VERSION 5.7 ;
  NOWIREEXTENSIONATPIN ON ;
  DIVIDERCHAR "/" ;
  BUSBITCHARS "[]" ;
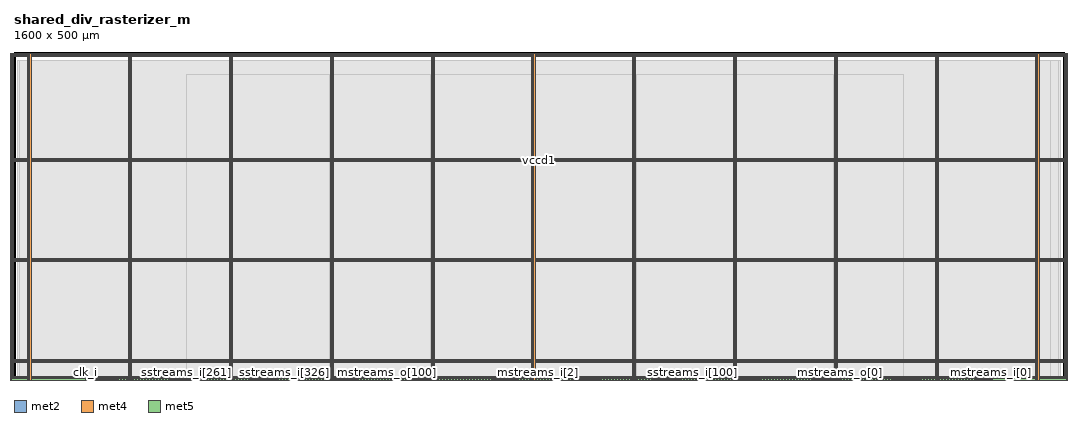
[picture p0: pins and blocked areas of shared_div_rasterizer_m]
MACRO shared_div_rasterizer_m
  CLASS BLOCK ;
  FOREIGN shared_div_rasterizer_m ;
  ORIGIN 0.000 0.000 ;
  SIZE 1600.000 BY 500.000 ;
  PIN clk_i
    DIRECTION INPUT ;
    USE SIGNAL ;
    ANTENNAGATEAREA 0.852000 ;
    PORT
      LAYER met2 ;
        RECT 108.650 0.000 108.930 4.000 ;
    END
  END clk_i
  PIN mstreams_i[0]
    DIRECTION INPUT ;
    USE SIGNAL ;
    ANTENNAGATEAREA 0.196500 ;
    PORT
      LAYER met2 ;
        RECT 1488.650 0.000 1488.930 4.000 ;
    END
  END mstreams_i[0]
  PIN mstreams_i[1]
    DIRECTION INPUT ;
    USE SIGNAL ;
    ANTENNAGATEAREA 0.196500 ;
    PORT
      LAYER met2 ;
        RECT 1490.950 0.000 1491.230 4.000 ;
    END
  END mstreams_i[1]
  PIN mstreams_i[2]
    DIRECTION INPUT ;
    USE SIGNAL ;
    ANTENNAGATEAREA 0.196500 ;
    PORT
      LAYER met2 ;
        RECT 798.650 0.000 798.930 4.000 ;
    END
  END mstreams_i[2]
  PIN mstreams_i[3]
    DIRECTION INPUT ;
    USE SIGNAL ;
    ANTENNAGATEAREA 0.196500 ;
    PORT
      LAYER met2 ;
        RECT 800.950 0.000 801.230 4.000 ;
    END
  END mstreams_i[3]
  PIN mstreams_o[0]
    DIRECTION OUTPUT TRISTATE ;
    USE SIGNAL ;
    ANTENNADIFFAREA 0.795200 ;
    PORT
      LAYER met2 ;
        RECT 1258.650 0.000 1258.930 4.000 ;
    END
  END mstreams_o[0]
  PIN mstreams_o[100]
    DIRECTION OUTPUT TRISTATE ;
    USE SIGNAL ;
    ANTENNADIFFAREA 0.795200 ;
    PORT
      LAYER met2 ;
        RECT 568.650 0.000 568.930 4.000 ;
    END
  END mstreams_o[100]
  PIN mstreams_o[101]
    DIRECTION OUTPUT TRISTATE ;
    USE SIGNAL ;
    ANTENNADIFFAREA 0.795200 ;
    PORT
      LAYER met2 ;
        RECT 570.950 0.000 571.230 4.000 ;
    END
  END mstreams_o[101]
  PIN mstreams_o[102]
    DIRECTION OUTPUT TRISTATE ;
    USE SIGNAL ;
    ANTENNADIFFAREA 0.795200 ;
    PORT
      LAYER met2 ;
        RECT 573.250 0.000 573.530 4.000 ;
    END
  END mstreams_o[102]
  PIN mstreams_o[103]
    DIRECTION OUTPUT TRISTATE ;
    USE SIGNAL ;
    ANTENNADIFFAREA 0.795200 ;
    PORT
      LAYER met2 ;
        RECT 575.550 0.000 575.830 4.000 ;
    END
  END mstreams_o[103]
  PIN mstreams_o[104]
    DIRECTION OUTPUT TRISTATE ;
    USE SIGNAL ;
    ANTENNADIFFAREA 0.795200 ;
    PORT
      LAYER met2 ;
        RECT 577.850 0.000 578.130 4.000 ;
    END
  END mstreams_o[104]
  PIN mstreams_o[105]
    DIRECTION OUTPUT TRISTATE ;
    USE SIGNAL ;
    ANTENNADIFFAREA 0.795200 ;
    PORT
      LAYER met2 ;
        RECT 580.150 0.000 580.430 4.000 ;
    END
  END mstreams_o[105]
  PIN mstreams_o[106]
    DIRECTION OUTPUT TRISTATE ;
    USE SIGNAL ;
    ANTENNADIFFAREA 0.795200 ;
    PORT
      LAYER met2 ;
        RECT 582.450 0.000 582.730 4.000 ;
    END
  END mstreams_o[106]
  PIN mstreams_o[107]
    DIRECTION OUTPUT TRISTATE ;
    USE SIGNAL ;
    ANTENNADIFFAREA 0.795200 ;
    PORT
      LAYER met2 ;
        RECT 584.750 0.000 585.030 4.000 ;
    END
  END mstreams_o[107]
  PIN mstreams_o[108]
    DIRECTION OUTPUT TRISTATE ;
    USE SIGNAL ;
    ANTENNADIFFAREA 0.795200 ;
    PORT
      LAYER met2 ;
        RECT 587.050 0.000 587.330 4.000 ;
    END
  END mstreams_o[108]
  PIN mstreams_o[109]
    DIRECTION OUTPUT TRISTATE ;
    USE SIGNAL ;
    ANTENNADIFFAREA 0.795200 ;
    PORT
      LAYER met2 ;
        RECT 589.350 0.000 589.630 4.000 ;
    END
  END mstreams_o[109]
  PIN mstreams_o[10]
    DIRECTION OUTPUT TRISTATE ;
    USE SIGNAL ;
    ANTENNADIFFAREA 0.795200 ;
    PORT
      LAYER met2 ;
        RECT 1281.650 0.000 1281.930 4.000 ;
    END
  END mstreams_o[10]
  PIN mstreams_o[110]
    DIRECTION OUTPUT TRISTATE ;
    USE SIGNAL ;
    ANTENNADIFFAREA 0.795200 ;
    PORT
      LAYER met2 ;
        RECT 591.650 0.000 591.930 4.000 ;
    END
  END mstreams_o[110]
  PIN mstreams_o[111]
    DIRECTION OUTPUT TRISTATE ;
    USE SIGNAL ;
    ANTENNADIFFAREA 0.795200 ;
    PORT
      LAYER met2 ;
        RECT 593.950 0.000 594.230 4.000 ;
    END
  END mstreams_o[111]
  PIN mstreams_o[112]
    DIRECTION OUTPUT TRISTATE ;
    USE SIGNAL ;
    ANTENNADIFFAREA 0.795200 ;
    PORT
      LAYER met2 ;
        RECT 596.250 0.000 596.530 4.000 ;
    END
  END mstreams_o[112]
  PIN mstreams_o[113]
    DIRECTION OUTPUT TRISTATE ;
    USE SIGNAL ;
    ANTENNADIFFAREA 0.795200 ;
    PORT
      LAYER met2 ;
        RECT 598.550 0.000 598.830 4.000 ;
    END
  END mstreams_o[113]
  PIN mstreams_o[114]
    DIRECTION OUTPUT TRISTATE ;
    USE SIGNAL ;
    ANTENNADIFFAREA 0.795200 ;
    PORT
      LAYER met2 ;
        RECT 600.850 0.000 601.130 4.000 ;
    END
  END mstreams_o[114]
  PIN mstreams_o[115]
    DIRECTION OUTPUT TRISTATE ;
    USE SIGNAL ;
    ANTENNADIFFAREA 0.795200 ;
    PORT
      LAYER met2 ;
        RECT 603.150 0.000 603.430 4.000 ;
    END
  END mstreams_o[115]
  PIN mstreams_o[116]
    DIRECTION OUTPUT TRISTATE ;
    USE SIGNAL ;
    ANTENNADIFFAREA 0.795200 ;
    PORT
      LAYER met2 ;
        RECT 605.450 0.000 605.730 4.000 ;
    END
  END mstreams_o[116]
  PIN mstreams_o[117]
    DIRECTION OUTPUT TRISTATE ;
    USE SIGNAL ;
    ANTENNADIFFAREA 0.795200 ;
    PORT
      LAYER met2 ;
        RECT 607.750 0.000 608.030 4.000 ;
    END
  END mstreams_o[117]
  PIN mstreams_o[118]
    DIRECTION OUTPUT TRISTATE ;
    USE SIGNAL ;
    ANTENNADIFFAREA 0.795200 ;
    PORT
      LAYER met2 ;
        RECT 610.050 0.000 610.330 4.000 ;
    END
  END mstreams_o[118]
  PIN mstreams_o[119]
    DIRECTION OUTPUT TRISTATE ;
    USE SIGNAL ;
    ANTENNADIFFAREA 0.795200 ;
    PORT
      LAYER met2 ;
        RECT 612.350 0.000 612.630 4.000 ;
    END
  END mstreams_o[119]
  PIN mstreams_o[11]
    DIRECTION OUTPUT TRISTATE ;
    USE SIGNAL ;
    ANTENNADIFFAREA 0.795200 ;
    PORT
      LAYER met2 ;
        RECT 1283.950 0.000 1284.230 4.000 ;
    END
  END mstreams_o[11]
  PIN mstreams_o[120]
    DIRECTION OUTPUT TRISTATE ;
    USE SIGNAL ;
    ANTENNADIFFAREA 0.795200 ;
    PORT
      LAYER met2 ;
        RECT 614.650 0.000 614.930 4.000 ;
    END
  END mstreams_o[120]
  PIN mstreams_o[121]
    DIRECTION OUTPUT TRISTATE ;
    USE SIGNAL ;
    ANTENNADIFFAREA 0.795200 ;
    PORT
      LAYER met2 ;
        RECT 616.950 0.000 617.230 4.000 ;
    END
  END mstreams_o[121]
  PIN mstreams_o[122]
    DIRECTION OUTPUT TRISTATE ;
    USE SIGNAL ;
    ANTENNADIFFAREA 0.795200 ;
    PORT
      LAYER met2 ;
        RECT 619.250 0.000 619.530 4.000 ;
    END
  END mstreams_o[122]
  PIN mstreams_o[123]
    DIRECTION OUTPUT TRISTATE ;
    USE SIGNAL ;
    ANTENNADIFFAREA 0.795200 ;
    PORT
      LAYER met2 ;
        RECT 621.550 0.000 621.830 4.000 ;
    END
  END mstreams_o[123]
  PIN mstreams_o[124]
    DIRECTION OUTPUT TRISTATE ;
    USE SIGNAL ;
    ANTENNADIFFAREA 0.795200 ;
    PORT
      LAYER met2 ;
        RECT 623.850 0.000 624.130 4.000 ;
    END
  END mstreams_o[124]
  PIN mstreams_o[125]
    DIRECTION OUTPUT TRISTATE ;
    USE SIGNAL ;
    ANTENNADIFFAREA 0.795200 ;
    PORT
      LAYER met2 ;
        RECT 626.150 0.000 626.430 4.000 ;
    END
  END mstreams_o[125]
  PIN mstreams_o[126]
    DIRECTION OUTPUT TRISTATE ;
    USE SIGNAL ;
    ANTENNADIFFAREA 0.795200 ;
    PORT
      LAYER met2 ;
        RECT 628.450 0.000 628.730 4.000 ;
    END
  END mstreams_o[126]
  PIN mstreams_o[127]
    DIRECTION OUTPUT TRISTATE ;
    USE SIGNAL ;
    ANTENNADIFFAREA 0.795200 ;
    PORT
      LAYER met2 ;
        RECT 630.750 0.000 631.030 4.000 ;
    END
  END mstreams_o[127]
  PIN mstreams_o[128]
    DIRECTION OUTPUT TRISTATE ;
    USE SIGNAL ;
    ANTENNADIFFAREA 0.795200 ;
    PORT
      LAYER met2 ;
        RECT 633.050 0.000 633.330 4.000 ;
    END
  END mstreams_o[128]
  PIN mstreams_o[129]
    DIRECTION OUTPUT TRISTATE ;
    USE SIGNAL ;
    ANTENNADIFFAREA 0.795200 ;
    PORT
      LAYER met2 ;
        RECT 635.350 0.000 635.630 4.000 ;
    END
  END mstreams_o[129]
  PIN mstreams_o[12]
    DIRECTION OUTPUT TRISTATE ;
    USE SIGNAL ;
    ANTENNADIFFAREA 0.795200 ;
    PORT
      LAYER met2 ;
        RECT 1286.250 0.000 1286.530 4.000 ;
    END
  END mstreams_o[12]
  PIN mstreams_o[130]
    DIRECTION OUTPUT TRISTATE ;
    USE SIGNAL ;
    ANTENNADIFFAREA 0.795200 ;
    PORT
      LAYER met2 ;
        RECT 637.650 0.000 637.930 4.000 ;
    END
  END mstreams_o[130]
  PIN mstreams_o[131]
    DIRECTION OUTPUT TRISTATE ;
    USE SIGNAL ;
    ANTENNADIFFAREA 0.795200 ;
    PORT
      LAYER met2 ;
        RECT 639.950 0.000 640.230 4.000 ;
    END
  END mstreams_o[131]
  PIN mstreams_o[132]
    DIRECTION OUTPUT TRISTATE ;
    USE SIGNAL ;
    ANTENNADIFFAREA 0.795200 ;
    PORT
      LAYER met2 ;
        RECT 642.250 0.000 642.530 4.000 ;
    END
  END mstreams_o[132]
  PIN mstreams_o[133]
    DIRECTION OUTPUT TRISTATE ;
    USE SIGNAL ;
    ANTENNADIFFAREA 0.795200 ;
    PORT
      LAYER met2 ;
        RECT 644.550 0.000 644.830 4.000 ;
    END
  END mstreams_o[133]
  PIN mstreams_o[134]
    DIRECTION OUTPUT TRISTATE ;
    USE SIGNAL ;
    ANTENNADIFFAREA 0.795200 ;
    PORT
      LAYER met2 ;
        RECT 646.850 0.000 647.130 4.000 ;
    END
  END mstreams_o[134]
  PIN mstreams_o[135]
    DIRECTION OUTPUT TRISTATE ;
    USE SIGNAL ;
    ANTENNADIFFAREA 0.795200 ;
    PORT
      LAYER met2 ;
        RECT 649.150 0.000 649.430 4.000 ;
    END
  END mstreams_o[135]
  PIN mstreams_o[136]
    DIRECTION OUTPUT TRISTATE ;
    USE SIGNAL ;
    ANTENNADIFFAREA 0.795200 ;
    PORT
      LAYER met2 ;
        RECT 651.450 0.000 651.730 4.000 ;
    END
  END mstreams_o[136]
  PIN mstreams_o[137]
    DIRECTION OUTPUT TRISTATE ;
    USE SIGNAL ;
    ANTENNADIFFAREA 0.795200 ;
    PORT
      LAYER met2 ;
        RECT 653.750 0.000 654.030 4.000 ;
    END
  END mstreams_o[137]
  PIN mstreams_o[138]
    DIRECTION OUTPUT TRISTATE ;
    USE SIGNAL ;
    ANTENNADIFFAREA 0.795200 ;
    PORT
      LAYER met2 ;
        RECT 656.050 0.000 656.330 4.000 ;
    END
  END mstreams_o[138]
  PIN mstreams_o[139]
    DIRECTION OUTPUT TRISTATE ;
    USE SIGNAL ;
    ANTENNADIFFAREA 0.795200 ;
    PORT
      LAYER met2 ;
        RECT 658.350 0.000 658.630 4.000 ;
    END
  END mstreams_o[139]
  PIN mstreams_o[13]
    DIRECTION OUTPUT TRISTATE ;
    USE SIGNAL ;
    ANTENNADIFFAREA 0.795200 ;
    PORT
      LAYER met2 ;
        RECT 1288.550 0.000 1288.830 4.000 ;
    END
  END mstreams_o[13]
  PIN mstreams_o[140]
    DIRECTION OUTPUT TRISTATE ;
    USE SIGNAL ;
    ANTENNADIFFAREA 0.795200 ;
    PORT
      LAYER met2 ;
        RECT 660.650 0.000 660.930 4.000 ;
    END
  END mstreams_o[140]
  PIN mstreams_o[141]
    DIRECTION OUTPUT TRISTATE ;
    USE SIGNAL ;
    ANTENNADIFFAREA 0.795200 ;
    PORT
      LAYER met2 ;
        RECT 662.950 0.000 663.230 4.000 ;
    END
  END mstreams_o[141]
  PIN mstreams_o[142]
    DIRECTION OUTPUT TRISTATE ;
    USE SIGNAL ;
    ANTENNADIFFAREA 0.795200 ;
    PORT
      LAYER met2 ;
        RECT 665.250 0.000 665.530 4.000 ;
    END
  END mstreams_o[142]
  PIN mstreams_o[143]
    DIRECTION OUTPUT TRISTATE ;
    USE SIGNAL ;
    ANTENNADIFFAREA 0.795200 ;
    PORT
      LAYER met2 ;
        RECT 667.550 0.000 667.830 4.000 ;
    END
  END mstreams_o[143]
  PIN mstreams_o[144]
    DIRECTION OUTPUT TRISTATE ;
    USE SIGNAL ;
    ANTENNADIFFAREA 0.795200 ;
    PORT
      LAYER met2 ;
        RECT 669.850 0.000 670.130 4.000 ;
    END
  END mstreams_o[144]
  PIN mstreams_o[145]
    DIRECTION OUTPUT TRISTATE ;
    USE SIGNAL ;
    ANTENNADIFFAREA 0.795200 ;
    PORT
      LAYER met2 ;
        RECT 672.150 0.000 672.430 4.000 ;
    END
  END mstreams_o[145]
  PIN mstreams_o[146]
    DIRECTION OUTPUT TRISTATE ;
    USE SIGNAL ;
    ANTENNADIFFAREA 0.795200 ;
    PORT
      LAYER met2 ;
        RECT 674.450 0.000 674.730 4.000 ;
    END
  END mstreams_o[146]
  PIN mstreams_o[147]
    DIRECTION OUTPUT TRISTATE ;
    USE SIGNAL ;
    ANTENNADIFFAREA 0.795200 ;
    PORT
      LAYER met2 ;
        RECT 676.750 0.000 677.030 4.000 ;
    END
  END mstreams_o[147]
  PIN mstreams_o[148]
    DIRECTION OUTPUT TRISTATE ;
    USE SIGNAL ;
    ANTENNADIFFAREA 0.795200 ;
    PORT
      LAYER met2 ;
        RECT 679.050 0.000 679.330 4.000 ;
    END
  END mstreams_o[148]
  PIN mstreams_o[149]
    DIRECTION OUTPUT TRISTATE ;
    USE SIGNAL ;
    PORT
      LAYER met2 ;
        RECT 681.350 0.000 681.630 4.000 ;
    END
  END mstreams_o[149]
  PIN mstreams_o[14]
    DIRECTION OUTPUT TRISTATE ;
    USE SIGNAL ;
    ANTENNADIFFAREA 0.795200 ;
    PORT
      LAYER met2 ;
        RECT 1290.850 0.000 1291.130 4.000 ;
    END
  END mstreams_o[14]
  PIN mstreams_o[150]
    DIRECTION OUTPUT TRISTATE ;
    USE SIGNAL ;
    ANTENNADIFFAREA 0.795200 ;
    PORT
      LAYER met2 ;
        RECT 683.650 0.000 683.930 4.000 ;
    END
  END mstreams_o[150]
  PIN mstreams_o[151]
    DIRECTION OUTPUT TRISTATE ;
    USE SIGNAL ;
    ANTENNADIFFAREA 0.795200 ;
    PORT
      LAYER met2 ;
        RECT 685.950 0.000 686.230 4.000 ;
    END
  END mstreams_o[151]
  PIN mstreams_o[152]
    DIRECTION OUTPUT TRISTATE ;
    USE SIGNAL ;
    ANTENNADIFFAREA 0.795200 ;
    PORT
      LAYER met2 ;
        RECT 688.250 0.000 688.530 4.000 ;
    END
  END mstreams_o[152]
  PIN mstreams_o[153]
    DIRECTION OUTPUT TRISTATE ;
    USE SIGNAL ;
    ANTENNADIFFAREA 0.795200 ;
    PORT
      LAYER met2 ;
        RECT 690.550 0.000 690.830 4.000 ;
    END
  END mstreams_o[153]
  PIN mstreams_o[154]
    DIRECTION OUTPUT TRISTATE ;
    USE SIGNAL ;
    ANTENNADIFFAREA 0.795200 ;
    PORT
      LAYER met2 ;
        RECT 692.850 0.000 693.130 4.000 ;
    END
  END mstreams_o[154]
  PIN mstreams_o[155]
    DIRECTION OUTPUT TRISTATE ;
    USE SIGNAL ;
    ANTENNADIFFAREA 0.795200 ;
    PORT
      LAYER met2 ;
        RECT 695.150 0.000 695.430 4.000 ;
    END
  END mstreams_o[155]
  PIN mstreams_o[156]
    DIRECTION OUTPUT TRISTATE ;
    USE SIGNAL ;
    ANTENNADIFFAREA 0.795200 ;
    PORT
      LAYER met2 ;
        RECT 697.450 0.000 697.730 4.000 ;
    END
  END mstreams_o[156]
  PIN mstreams_o[157]
    DIRECTION OUTPUT TRISTATE ;
    USE SIGNAL ;
    ANTENNADIFFAREA 0.795200 ;
    PORT
      LAYER met2 ;
        RECT 699.750 0.000 700.030 4.000 ;
    END
  END mstreams_o[157]
  PIN mstreams_o[158]
    DIRECTION OUTPUT TRISTATE ;
    USE SIGNAL ;
    ANTENNADIFFAREA 0.795200 ;
    PORT
      LAYER met2 ;
        RECT 702.050 0.000 702.330 4.000 ;
    END
  END mstreams_o[158]
  PIN mstreams_o[159]
    DIRECTION OUTPUT TRISTATE ;
    USE SIGNAL ;
    ANTENNADIFFAREA 0.795200 ;
    PORT
      LAYER met2 ;
        RECT 704.350 0.000 704.630 4.000 ;
    END
  END mstreams_o[159]
  PIN mstreams_o[15]
    DIRECTION OUTPUT TRISTATE ;
    USE SIGNAL ;
    ANTENNADIFFAREA 0.795200 ;
    PORT
      LAYER met2 ;
        RECT 1293.150 0.000 1293.430 4.000 ;
    END
  END mstreams_o[15]
  PIN mstreams_o[160]
    DIRECTION OUTPUT TRISTATE ;
    USE SIGNAL ;
    ANTENNADIFFAREA 0.795200 ;
    PORT
      LAYER met2 ;
        RECT 706.650 0.000 706.930 4.000 ;
    END
  END mstreams_o[160]
  PIN mstreams_o[161]
    DIRECTION OUTPUT TRISTATE ;
    USE SIGNAL ;
    ANTENNADIFFAREA 0.795200 ;
    PORT
      LAYER met2 ;
        RECT 708.950 0.000 709.230 4.000 ;
    END
  END mstreams_o[161]
  PIN mstreams_o[162]
    DIRECTION OUTPUT TRISTATE ;
    USE SIGNAL ;
    ANTENNADIFFAREA 0.795200 ;
    PORT
      LAYER met2 ;
        RECT 711.250 0.000 711.530 4.000 ;
    END
  END mstreams_o[162]
  PIN mstreams_o[163]
    DIRECTION OUTPUT TRISTATE ;
    USE SIGNAL ;
    ANTENNADIFFAREA 0.795200 ;
    PORT
      LAYER met2 ;
        RECT 713.550 0.000 713.830 4.000 ;
    END
  END mstreams_o[163]
  PIN mstreams_o[164]
    DIRECTION OUTPUT TRISTATE ;
    USE SIGNAL ;
    ANTENNADIFFAREA 0.795200 ;
    PORT
      LAYER met2 ;
        RECT 715.850 0.000 716.130 4.000 ;
    END
  END mstreams_o[164]
  PIN mstreams_o[165]
    DIRECTION OUTPUT TRISTATE ;
    USE SIGNAL ;
    ANTENNADIFFAREA 0.795200 ;
    PORT
      LAYER met2 ;
        RECT 718.150 0.000 718.430 4.000 ;
    END
  END mstreams_o[165]
  PIN mstreams_o[166]
    DIRECTION OUTPUT TRISTATE ;
    USE SIGNAL ;
    ANTENNADIFFAREA 0.795200 ;
    PORT
      LAYER met2 ;
        RECT 720.450 0.000 720.730 4.000 ;
    END
  END mstreams_o[166]
  PIN mstreams_o[167]
    DIRECTION OUTPUT TRISTATE ;
    USE SIGNAL ;
    ANTENNADIFFAREA 0.795200 ;
    PORT
      LAYER met2 ;
        RECT 722.750 0.000 723.030 4.000 ;
    END
  END mstreams_o[167]
  PIN mstreams_o[168]
    DIRECTION OUTPUT TRISTATE ;
    USE SIGNAL ;
    ANTENNADIFFAREA 0.795200 ;
    PORT
      LAYER met2 ;
        RECT 725.050 0.000 725.330 4.000 ;
    END
  END mstreams_o[168]
  PIN mstreams_o[169]
    DIRECTION OUTPUT TRISTATE ;
    USE SIGNAL ;
    ANTENNADIFFAREA 0.795200 ;
    PORT
      LAYER met2 ;
        RECT 727.350 0.000 727.630 4.000 ;
    END
  END mstreams_o[169]
  PIN mstreams_o[16]
    DIRECTION OUTPUT TRISTATE ;
    USE SIGNAL ;
    ANTENNADIFFAREA 0.795200 ;
    PORT
      LAYER met2 ;
        RECT 1295.450 0.000 1295.730 4.000 ;
    END
  END mstreams_o[16]
  PIN mstreams_o[170]
    DIRECTION OUTPUT TRISTATE ;
    USE SIGNAL ;
    ANTENNADIFFAREA 0.795200 ;
    PORT
      LAYER met2 ;
        RECT 729.650 0.000 729.930 4.000 ;
    END
  END mstreams_o[170]
  PIN mstreams_o[171]
    DIRECTION OUTPUT TRISTATE ;
    USE SIGNAL ;
    ANTENNADIFFAREA 0.795200 ;
    PORT
      LAYER met2 ;
        RECT 731.950 0.000 732.230 4.000 ;
    END
  END mstreams_o[171]
  PIN mstreams_o[172]
    DIRECTION OUTPUT TRISTATE ;
    USE SIGNAL ;
    ANTENNADIFFAREA 0.795200 ;
    PORT
      LAYER met2 ;
        RECT 734.250 0.000 734.530 4.000 ;
    END
  END mstreams_o[172]
  PIN mstreams_o[173]
    DIRECTION OUTPUT TRISTATE ;
    USE SIGNAL ;
    ANTENNADIFFAREA 0.795200 ;
    PORT
      LAYER met2 ;
        RECT 736.550 0.000 736.830 4.000 ;
    END
  END mstreams_o[173]
  PIN mstreams_o[174]
    DIRECTION OUTPUT TRISTATE ;
    USE SIGNAL ;
    ANTENNADIFFAREA 0.795200 ;
    PORT
      LAYER met2 ;
        RECT 738.850 0.000 739.130 4.000 ;
    END
  END mstreams_o[174]
  PIN mstreams_o[175]
    DIRECTION OUTPUT TRISTATE ;
    USE SIGNAL ;
    ANTENNADIFFAREA 0.795200 ;
    PORT
      LAYER met2 ;
        RECT 741.150 0.000 741.430 4.000 ;
    END
  END mstreams_o[175]
  PIN mstreams_o[176]
    DIRECTION OUTPUT TRISTATE ;
    USE SIGNAL ;
    ANTENNADIFFAREA 0.795200 ;
    PORT
      LAYER met2 ;
        RECT 743.450 0.000 743.730 4.000 ;
    END
  END mstreams_o[176]
  PIN mstreams_o[177]
    DIRECTION OUTPUT TRISTATE ;
    USE SIGNAL ;
    ANTENNADIFFAREA 0.795200 ;
    PORT
      LAYER met2 ;
        RECT 745.750 0.000 746.030 4.000 ;
    END
  END mstreams_o[177]
  PIN mstreams_o[178]
    DIRECTION OUTPUT TRISTATE ;
    USE SIGNAL ;
    ANTENNADIFFAREA 0.795200 ;
    PORT
      LAYER met2 ;
        RECT 748.050 0.000 748.330 4.000 ;
    END
  END mstreams_o[178]
  PIN mstreams_o[179]
    DIRECTION OUTPUT TRISTATE ;
    USE SIGNAL ;
    ANTENNADIFFAREA 0.795200 ;
    PORT
      LAYER met2 ;
        RECT 750.350 0.000 750.630 4.000 ;
    END
  END mstreams_o[179]
  PIN mstreams_o[17]
    DIRECTION OUTPUT TRISTATE ;
    USE SIGNAL ;
    ANTENNADIFFAREA 0.795200 ;
    PORT
      LAYER met2 ;
        RECT 1297.750 0.000 1298.030 4.000 ;
    END
  END mstreams_o[17]
  PIN mstreams_o[180]
    DIRECTION OUTPUT TRISTATE ;
    USE SIGNAL ;
    ANTENNADIFFAREA 0.795200 ;
    PORT
      LAYER met2 ;
        RECT 752.650 0.000 752.930 4.000 ;
    END
  END mstreams_o[180]
  PIN mstreams_o[181]
    DIRECTION OUTPUT TRISTATE ;
    USE SIGNAL ;
    ANTENNADIFFAREA 0.795200 ;
    PORT
      LAYER met2 ;
        RECT 754.950 0.000 755.230 4.000 ;
    END
  END mstreams_o[181]
  PIN mstreams_o[182]
    DIRECTION OUTPUT TRISTATE ;
    USE SIGNAL ;
    ANTENNADIFFAREA 0.795200 ;
    PORT
      LAYER met2 ;
        RECT 757.250 0.000 757.530 4.000 ;
    END
  END mstreams_o[182]
  PIN mstreams_o[183]
    DIRECTION OUTPUT TRISTATE ;
    USE SIGNAL ;
    ANTENNADIFFAREA 0.795200 ;
    PORT
      LAYER met2 ;
        RECT 759.550 0.000 759.830 4.000 ;
    END
  END mstreams_o[183]
  PIN mstreams_o[184]
    DIRECTION OUTPUT TRISTATE ;
    USE SIGNAL ;
    ANTENNADIFFAREA 0.795200 ;
    PORT
      LAYER met2 ;
        RECT 761.850 0.000 762.130 4.000 ;
    END
  END mstreams_o[184]
  PIN mstreams_o[185]
    DIRECTION OUTPUT TRISTATE ;
    USE SIGNAL ;
    ANTENNADIFFAREA 0.795200 ;
    PORT
      LAYER met2 ;
        RECT 764.150 0.000 764.430 4.000 ;
    END
  END mstreams_o[185]
  PIN mstreams_o[186]
    DIRECTION OUTPUT TRISTATE ;
    USE SIGNAL ;
    ANTENNADIFFAREA 0.795200 ;
    PORT
      LAYER met2 ;
        RECT 766.450 0.000 766.730 4.000 ;
    END
  END mstreams_o[186]
  PIN mstreams_o[187]
    DIRECTION OUTPUT TRISTATE ;
    USE SIGNAL ;
    ANTENNADIFFAREA 0.795200 ;
    PORT
      LAYER met2 ;
        RECT 768.750 0.000 769.030 4.000 ;
    END
  END mstreams_o[187]
  PIN mstreams_o[188]
    DIRECTION OUTPUT TRISTATE ;
    USE SIGNAL ;
    ANTENNADIFFAREA 0.795200 ;
    PORT
      LAYER met2 ;
        RECT 771.050 0.000 771.330 4.000 ;
    END
  END mstreams_o[188]
  PIN mstreams_o[189]
    DIRECTION OUTPUT TRISTATE ;
    USE SIGNAL ;
    ANTENNADIFFAREA 0.795200 ;
    PORT
      LAYER met2 ;
        RECT 773.350 0.000 773.630 4.000 ;
    END
  END mstreams_o[189]
  PIN mstreams_o[18]
    DIRECTION OUTPUT TRISTATE ;
    USE SIGNAL ;
    ANTENNADIFFAREA 0.795200 ;
    PORT
      LAYER met2 ;
        RECT 1300.050 0.000 1300.330 4.000 ;
    END
  END mstreams_o[18]
  PIN mstreams_o[190]
    DIRECTION OUTPUT TRISTATE ;
    USE SIGNAL ;
    ANTENNADIFFAREA 0.795200 ;
    PORT
      LAYER met2 ;
        RECT 775.650 0.000 775.930 4.000 ;
    END
  END mstreams_o[190]
  PIN mstreams_o[191]
    DIRECTION OUTPUT TRISTATE ;
    USE SIGNAL ;
    ANTENNADIFFAREA 0.795200 ;
    PORT
      LAYER met2 ;
        RECT 777.950 0.000 778.230 4.000 ;
    END
  END mstreams_o[191]
  PIN mstreams_o[192]
    DIRECTION OUTPUT TRISTATE ;
    USE SIGNAL ;
    ANTENNADIFFAREA 0.795200 ;
    PORT
      LAYER met2 ;
        RECT 780.250 0.000 780.530 4.000 ;
    END
  END mstreams_o[192]
  PIN mstreams_o[193]
    DIRECTION OUTPUT TRISTATE ;
    USE SIGNAL ;
    ANTENNADIFFAREA 0.795200 ;
    PORT
      LAYER met2 ;
        RECT 782.550 0.000 782.830 4.000 ;
    END
  END mstreams_o[193]
  PIN mstreams_o[194]
    DIRECTION OUTPUT TRISTATE ;
    USE SIGNAL ;
    ANTENNADIFFAREA 0.795200 ;
    PORT
      LAYER met2 ;
        RECT 784.850 0.000 785.130 4.000 ;
    END
  END mstreams_o[194]
  PIN mstreams_o[195]
    DIRECTION OUTPUT TRISTATE ;
    USE SIGNAL ;
    ANTENNADIFFAREA 0.795200 ;
    PORT
      LAYER met2 ;
        RECT 787.150 0.000 787.430 4.000 ;
    END
  END mstreams_o[195]
  PIN mstreams_o[196]
    DIRECTION OUTPUT TRISTATE ;
    USE SIGNAL ;
    ANTENNADIFFAREA 0.795200 ;
    PORT
      LAYER met2 ;
        RECT 789.450 0.000 789.730 4.000 ;
    END
  END mstreams_o[196]
  PIN mstreams_o[197]
    DIRECTION OUTPUT TRISTATE ;
    USE SIGNAL ;
    ANTENNADIFFAREA 0.795200 ;
    PORT
      LAYER met2 ;
        RECT 791.750 0.000 792.030 4.000 ;
    END
  END mstreams_o[197]
  PIN mstreams_o[198]
    DIRECTION OUTPUT TRISTATE ;
    USE SIGNAL ;
    ANTENNADIFFAREA 0.795200 ;
    PORT
      LAYER met2 ;
        RECT 794.050 0.000 794.330 4.000 ;
    END
  END mstreams_o[198]
  PIN mstreams_o[199]
    DIRECTION OUTPUT TRISTATE ;
    USE SIGNAL ;
    PORT
      LAYER met2 ;
        RECT 796.350 0.000 796.630 4.000 ;
    END
  END mstreams_o[199]
  PIN mstreams_o[19]
    DIRECTION OUTPUT TRISTATE ;
    USE SIGNAL ;
    ANTENNADIFFAREA 0.795200 ;
    PORT
      LAYER met2 ;
        RECT 1302.350 0.000 1302.630 4.000 ;
    END
  END mstreams_o[19]
  PIN mstreams_o[1]
    DIRECTION OUTPUT TRISTATE ;
    USE SIGNAL ;
    ANTENNADIFFAREA 0.795200 ;
    PORT
      LAYER met2 ;
        RECT 1260.950 0.000 1261.230 4.000 ;
    END
  END mstreams_o[1]
  PIN mstreams_o[20]
    DIRECTION OUTPUT TRISTATE ;
    USE SIGNAL ;
    ANTENNADIFFAREA 0.795200 ;
    PORT
      LAYER met2 ;
        RECT 1304.650 0.000 1304.930 4.000 ;
    END
  END mstreams_o[20]
  PIN mstreams_o[21]
    DIRECTION OUTPUT TRISTATE ;
    USE SIGNAL ;
    ANTENNADIFFAREA 0.795200 ;
    PORT
      LAYER met2 ;
        RECT 1306.950 0.000 1307.230 4.000 ;
    END
  END mstreams_o[21]
  PIN mstreams_o[22]
    DIRECTION OUTPUT TRISTATE ;
    USE SIGNAL ;
    ANTENNADIFFAREA 0.795200 ;
    PORT
      LAYER met2 ;
        RECT 1309.250 0.000 1309.530 4.000 ;
    END
  END mstreams_o[22]
  PIN mstreams_o[23]
    DIRECTION OUTPUT TRISTATE ;
    USE SIGNAL ;
    ANTENNADIFFAREA 0.795200 ;
    PORT
      LAYER met2 ;
        RECT 1311.550 0.000 1311.830 4.000 ;
    END
  END mstreams_o[23]
  PIN mstreams_o[24]
    DIRECTION OUTPUT TRISTATE ;
    USE SIGNAL ;
    ANTENNADIFFAREA 0.795200 ;
    PORT
      LAYER met2 ;
        RECT 1313.850 0.000 1314.130 4.000 ;
    END
  END mstreams_o[24]
  PIN mstreams_o[25]
    DIRECTION OUTPUT TRISTATE ;
    USE SIGNAL ;
    ANTENNADIFFAREA 0.795200 ;
    PORT
      LAYER met2 ;
        RECT 1316.150 0.000 1316.430 4.000 ;
    END
  END mstreams_o[25]
  PIN mstreams_o[26]
    DIRECTION OUTPUT TRISTATE ;
    USE SIGNAL ;
    ANTENNADIFFAREA 0.795200 ;
    PORT
      LAYER met2 ;
        RECT 1318.450 0.000 1318.730 4.000 ;
    END
  END mstreams_o[26]
  PIN mstreams_o[27]
    DIRECTION OUTPUT TRISTATE ;
    USE SIGNAL ;
    ANTENNADIFFAREA 0.795200 ;
    PORT
      LAYER met2 ;
        RECT 1320.750 0.000 1321.030 4.000 ;
    END
  END mstreams_o[27]
  PIN mstreams_o[28]
    DIRECTION OUTPUT TRISTATE ;
    USE SIGNAL ;
    ANTENNADIFFAREA 0.795200 ;
    PORT
      LAYER met2 ;
        RECT 1323.050 0.000 1323.330 4.000 ;
    END
  END mstreams_o[28]
  PIN mstreams_o[29]
    DIRECTION OUTPUT TRISTATE ;
    USE SIGNAL ;
    ANTENNADIFFAREA 0.795200 ;
    PORT
      LAYER met2 ;
        RECT 1325.350 0.000 1325.630 4.000 ;
    END
  END mstreams_o[29]
  PIN mstreams_o[2]
    DIRECTION OUTPUT TRISTATE ;
    USE SIGNAL ;
    ANTENNADIFFAREA 0.795200 ;
    PORT
      LAYER met2 ;
        RECT 1263.250 0.000 1263.530 4.000 ;
    END
  END mstreams_o[2]
  PIN mstreams_o[30]
    DIRECTION OUTPUT TRISTATE ;
    USE SIGNAL ;
    ANTENNADIFFAREA 0.795200 ;
    PORT
      LAYER met2 ;
        RECT 1327.650 0.000 1327.930 4.000 ;
    END
  END mstreams_o[30]
  PIN mstreams_o[31]
    DIRECTION OUTPUT TRISTATE ;
    USE SIGNAL ;
    ANTENNADIFFAREA 0.795200 ;
    PORT
      LAYER met2 ;
        RECT 1329.950 0.000 1330.230 4.000 ;
    END
  END mstreams_o[31]
  PIN mstreams_o[32]
    DIRECTION OUTPUT TRISTATE ;
    USE SIGNAL ;
    ANTENNADIFFAREA 0.795200 ;
    PORT
      LAYER met2 ;
        RECT 1332.250 0.000 1332.530 4.000 ;
    END
  END mstreams_o[32]
  PIN mstreams_o[33]
    DIRECTION OUTPUT TRISTATE ;
    USE SIGNAL ;
    ANTENNADIFFAREA 0.795200 ;
    PORT
      LAYER met2 ;
        RECT 1334.550 0.000 1334.830 4.000 ;
    END
  END mstreams_o[33]
  PIN mstreams_o[34]
    DIRECTION OUTPUT TRISTATE ;
    USE SIGNAL ;
    ANTENNADIFFAREA 0.795200 ;
    PORT
      LAYER met2 ;
        RECT 1336.850 0.000 1337.130 4.000 ;
    END
  END mstreams_o[34]
  PIN mstreams_o[35]
    DIRECTION OUTPUT TRISTATE ;
    USE SIGNAL ;
    ANTENNADIFFAREA 0.795200 ;
    PORT
      LAYER met2 ;
        RECT 1339.150 0.000 1339.430 4.000 ;
    END
  END mstreams_o[35]
  PIN mstreams_o[36]
    DIRECTION OUTPUT TRISTATE ;
    USE SIGNAL ;
    ANTENNADIFFAREA 0.795200 ;
    PORT
      LAYER met2 ;
        RECT 1341.450 0.000 1341.730 4.000 ;
    END
  END mstreams_o[36]
  PIN mstreams_o[37]
    DIRECTION OUTPUT TRISTATE ;
    USE SIGNAL ;
    ANTENNADIFFAREA 0.795200 ;
    PORT
      LAYER met2 ;
        RECT 1343.750 0.000 1344.030 4.000 ;
    END
  END mstreams_o[37]
  PIN mstreams_o[38]
    DIRECTION OUTPUT TRISTATE ;
    USE SIGNAL ;
    ANTENNADIFFAREA 0.795200 ;
    PORT
      LAYER met2 ;
        RECT 1346.050 0.000 1346.330 4.000 ;
    END
  END mstreams_o[38]
  PIN mstreams_o[39]
    DIRECTION OUTPUT TRISTATE ;
    USE SIGNAL ;
    ANTENNADIFFAREA 0.795200 ;
    PORT
      LAYER met2 ;
        RECT 1348.350 0.000 1348.630 4.000 ;
    END
  END mstreams_o[39]
  PIN mstreams_o[3]
    DIRECTION OUTPUT TRISTATE ;
    USE SIGNAL ;
    ANTENNADIFFAREA 0.795200 ;
    PORT
      LAYER met2 ;
        RECT 1265.550 0.000 1265.830 4.000 ;
    END
  END mstreams_o[3]
  PIN mstreams_o[40]
    DIRECTION OUTPUT TRISTATE ;
    USE SIGNAL ;
    ANTENNADIFFAREA 0.795200 ;
    PORT
      LAYER met2 ;
        RECT 1350.650 0.000 1350.930 4.000 ;
    END
  END mstreams_o[40]
  PIN mstreams_o[41]
    DIRECTION OUTPUT TRISTATE ;
    USE SIGNAL ;
    ANTENNADIFFAREA 0.795200 ;
    PORT
      LAYER met2 ;
        RECT 1352.950 0.000 1353.230 4.000 ;
    END
  END mstreams_o[41]
  PIN mstreams_o[42]
    DIRECTION OUTPUT TRISTATE ;
    USE SIGNAL ;
    ANTENNADIFFAREA 0.795200 ;
    PORT
      LAYER met2 ;
        RECT 1355.250 0.000 1355.530 4.000 ;
    END
  END mstreams_o[42]
  PIN mstreams_o[43]
    DIRECTION OUTPUT TRISTATE ;
    USE SIGNAL ;
    ANTENNADIFFAREA 0.795200 ;
    PORT
      LAYER met2 ;
        RECT 1357.550 0.000 1357.830 4.000 ;
    END
  END mstreams_o[43]
  PIN mstreams_o[44]
    DIRECTION OUTPUT TRISTATE ;
    USE SIGNAL ;
    ANTENNADIFFAREA 0.795200 ;
    PORT
      LAYER met2 ;
        RECT 1359.850 0.000 1360.130 4.000 ;
    END
  END mstreams_o[44]
  PIN mstreams_o[45]
    DIRECTION OUTPUT TRISTATE ;
    USE SIGNAL ;
    ANTENNADIFFAREA 0.795200 ;
    PORT
      LAYER met2 ;
        RECT 1362.150 0.000 1362.430 4.000 ;
    END
  END mstreams_o[45]
  PIN mstreams_o[46]
    DIRECTION OUTPUT TRISTATE ;
    USE SIGNAL ;
    ANTENNADIFFAREA 0.795200 ;
    PORT
      LAYER met2 ;
        RECT 1364.450 0.000 1364.730 4.000 ;
    END
  END mstreams_o[46]
  PIN mstreams_o[47]
    DIRECTION OUTPUT TRISTATE ;
    USE SIGNAL ;
    ANTENNADIFFAREA 0.795200 ;
    PORT
      LAYER met2 ;
        RECT 1366.750 0.000 1367.030 4.000 ;
    END
  END mstreams_o[47]
  PIN mstreams_o[48]
    DIRECTION OUTPUT TRISTATE ;
    USE SIGNAL ;
    ANTENNADIFFAREA 0.795200 ;
    PORT
      LAYER met2 ;
        RECT 1369.050 0.000 1369.330 4.000 ;
    END
  END mstreams_o[48]
  PIN mstreams_o[49]
    DIRECTION OUTPUT TRISTATE ;
    USE SIGNAL ;
    PORT
      LAYER met2 ;
        RECT 1371.350 0.000 1371.630 4.000 ;
    END
  END mstreams_o[49]
  PIN mstreams_o[4]
    DIRECTION OUTPUT TRISTATE ;
    USE SIGNAL ;
    ANTENNADIFFAREA 0.795200 ;
    PORT
      LAYER met2 ;
        RECT 1267.850 0.000 1268.130 4.000 ;
    END
  END mstreams_o[4]
  PIN mstreams_o[50]
    DIRECTION OUTPUT TRISTATE ;
    USE SIGNAL ;
    ANTENNADIFFAREA 0.795200 ;
    PORT
      LAYER met2 ;
        RECT 1373.650 0.000 1373.930 4.000 ;
    END
  END mstreams_o[50]
  PIN mstreams_o[51]
    DIRECTION OUTPUT TRISTATE ;
    USE SIGNAL ;
    ANTENNADIFFAREA 0.795200 ;
    PORT
      LAYER met2 ;
        RECT 1375.950 0.000 1376.230 4.000 ;
    END
  END mstreams_o[51]
  PIN mstreams_o[52]
    DIRECTION OUTPUT TRISTATE ;
    USE SIGNAL ;
    ANTENNADIFFAREA 0.795200 ;
    PORT
      LAYER met2 ;
        RECT 1378.250 0.000 1378.530 4.000 ;
    END
  END mstreams_o[52]
  PIN mstreams_o[53]
    DIRECTION OUTPUT TRISTATE ;
    USE SIGNAL ;
    ANTENNADIFFAREA 0.795200 ;
    PORT
      LAYER met2 ;
        RECT 1380.550 0.000 1380.830 4.000 ;
    END
  END mstreams_o[53]
  PIN mstreams_o[54]
    DIRECTION OUTPUT TRISTATE ;
    USE SIGNAL ;
    ANTENNADIFFAREA 0.795200 ;
    PORT
      LAYER met2 ;
        RECT 1382.850 0.000 1383.130 4.000 ;
    END
  END mstreams_o[54]
  PIN mstreams_o[55]
    DIRECTION OUTPUT TRISTATE ;
    USE SIGNAL ;
    ANTENNADIFFAREA 0.795200 ;
    PORT
      LAYER met2 ;
        RECT 1385.150 0.000 1385.430 4.000 ;
    END
  END mstreams_o[55]
  PIN mstreams_o[56]
    DIRECTION OUTPUT TRISTATE ;
    USE SIGNAL ;
    ANTENNADIFFAREA 0.795200 ;
    PORT
      LAYER met2 ;
        RECT 1387.450 0.000 1387.730 4.000 ;
    END
  END mstreams_o[56]
  PIN mstreams_o[57]
    DIRECTION OUTPUT TRISTATE ;
    USE SIGNAL ;
    ANTENNADIFFAREA 0.795200 ;
    PORT
      LAYER met2 ;
        RECT 1389.750 0.000 1390.030 4.000 ;
    END
  END mstreams_o[57]
  PIN mstreams_o[58]
    DIRECTION OUTPUT TRISTATE ;
    USE SIGNAL ;
    ANTENNADIFFAREA 0.795200 ;
    PORT
      LAYER met2 ;
        RECT 1392.050 0.000 1392.330 4.000 ;
    END
  END mstreams_o[58]
  PIN mstreams_o[59]
    DIRECTION OUTPUT TRISTATE ;
    USE SIGNAL ;
    ANTENNADIFFAREA 0.795200 ;
    PORT
      LAYER met2 ;
        RECT 1394.350 0.000 1394.630 4.000 ;
    END
  END mstreams_o[59]
  PIN mstreams_o[5]
    DIRECTION OUTPUT TRISTATE ;
    USE SIGNAL ;
    ANTENNADIFFAREA 0.795200 ;
    PORT
      LAYER met2 ;
        RECT 1270.150 0.000 1270.430 4.000 ;
    END
  END mstreams_o[5]
  PIN mstreams_o[60]
    DIRECTION OUTPUT TRISTATE ;
    USE SIGNAL ;
    ANTENNADIFFAREA 0.795200 ;
    PORT
      LAYER met2 ;
        RECT 1396.650 0.000 1396.930 4.000 ;
    END
  END mstreams_o[60]
  PIN mstreams_o[61]
    DIRECTION OUTPUT TRISTATE ;
    USE SIGNAL ;
    ANTENNADIFFAREA 0.795200 ;
    PORT
      LAYER met2 ;
        RECT 1398.950 0.000 1399.230 4.000 ;
    END
  END mstreams_o[61]
  PIN mstreams_o[62]
    DIRECTION OUTPUT TRISTATE ;
    USE SIGNAL ;
    ANTENNADIFFAREA 0.795200 ;
    PORT
      LAYER met2 ;
        RECT 1401.250 0.000 1401.530 4.000 ;
    END
  END mstreams_o[62]
  PIN mstreams_o[63]
    DIRECTION OUTPUT TRISTATE ;
    USE SIGNAL ;
    ANTENNADIFFAREA 0.795200 ;
    PORT
      LAYER met2 ;
        RECT 1403.550 0.000 1403.830 4.000 ;
    END
  END mstreams_o[63]
  PIN mstreams_o[64]
    DIRECTION OUTPUT TRISTATE ;
    USE SIGNAL ;
    ANTENNADIFFAREA 0.795200 ;
    PORT
      LAYER met2 ;
        RECT 1405.850 0.000 1406.130 4.000 ;
    END
  END mstreams_o[64]
  PIN mstreams_o[65]
    DIRECTION OUTPUT TRISTATE ;
    USE SIGNAL ;
    ANTENNADIFFAREA 0.795200 ;
    PORT
      LAYER met2 ;
        RECT 1408.150 0.000 1408.430 4.000 ;
    END
  END mstreams_o[65]
  PIN mstreams_o[66]
    DIRECTION OUTPUT TRISTATE ;
    USE SIGNAL ;
    ANTENNADIFFAREA 0.795200 ;
    PORT
      LAYER met2 ;
        RECT 1410.450 0.000 1410.730 4.000 ;
    END
  END mstreams_o[66]
  PIN mstreams_o[67]
    DIRECTION OUTPUT TRISTATE ;
    USE SIGNAL ;
    ANTENNADIFFAREA 0.795200 ;
    PORT
      LAYER met2 ;
        RECT 1412.750 0.000 1413.030 4.000 ;
    END
  END mstreams_o[67]
  PIN mstreams_o[68]
    DIRECTION OUTPUT TRISTATE ;
    USE SIGNAL ;
    ANTENNADIFFAREA 0.795200 ;
    PORT
      LAYER met2 ;
        RECT 1415.050 0.000 1415.330 4.000 ;
    END
  END mstreams_o[68]
  PIN mstreams_o[69]
    DIRECTION OUTPUT TRISTATE ;
    USE SIGNAL ;
    ANTENNADIFFAREA 0.795200 ;
    PORT
      LAYER met2 ;
        RECT 1417.350 0.000 1417.630 4.000 ;
    END
  END mstreams_o[69]
  PIN mstreams_o[6]
    DIRECTION OUTPUT TRISTATE ;
    USE SIGNAL ;
    ANTENNADIFFAREA 0.795200 ;
    PORT
      LAYER met2 ;
        RECT 1272.450 0.000 1272.730 4.000 ;
    END
  END mstreams_o[6]
  PIN mstreams_o[70]
    DIRECTION OUTPUT TRISTATE ;
    USE SIGNAL ;
    ANTENNADIFFAREA 0.795200 ;
    PORT
      LAYER met2 ;
        RECT 1419.650 0.000 1419.930 4.000 ;
    END
  END mstreams_o[70]
  PIN mstreams_o[71]
    DIRECTION OUTPUT TRISTATE ;
    USE SIGNAL ;
    ANTENNADIFFAREA 0.795200 ;
    PORT
      LAYER met2 ;
        RECT 1421.950 0.000 1422.230 4.000 ;
    END
  END mstreams_o[71]
  PIN mstreams_o[72]
    DIRECTION OUTPUT TRISTATE ;
    USE SIGNAL ;
    ANTENNADIFFAREA 0.795200 ;
    PORT
      LAYER met2 ;
        RECT 1424.250 0.000 1424.530 4.000 ;
    END
  END mstreams_o[72]
  PIN mstreams_o[73]
    DIRECTION OUTPUT TRISTATE ;
    USE SIGNAL ;
    ANTENNADIFFAREA 0.795200 ;
    PORT
      LAYER met2 ;
        RECT 1426.550 0.000 1426.830 4.000 ;
    END
  END mstreams_o[73]
  PIN mstreams_o[74]
    DIRECTION OUTPUT TRISTATE ;
    USE SIGNAL ;
    ANTENNADIFFAREA 0.795200 ;
    PORT
      LAYER met2 ;
        RECT 1428.850 0.000 1429.130 4.000 ;
    END
  END mstreams_o[74]
  PIN mstreams_o[75]
    DIRECTION OUTPUT TRISTATE ;
    USE SIGNAL ;
    ANTENNADIFFAREA 0.795200 ;
    PORT
      LAYER met2 ;
        RECT 1431.150 0.000 1431.430 4.000 ;
    END
  END mstreams_o[75]
  PIN mstreams_o[76]
    DIRECTION OUTPUT TRISTATE ;
    USE SIGNAL ;
    ANTENNADIFFAREA 0.795200 ;
    PORT
      LAYER met2 ;
        RECT 1433.450 0.000 1433.730 4.000 ;
    END
  END mstreams_o[76]
  PIN mstreams_o[77]
    DIRECTION OUTPUT TRISTATE ;
    USE SIGNAL ;
    ANTENNADIFFAREA 0.795200 ;
    PORT
      LAYER met2 ;
        RECT 1435.750 0.000 1436.030 4.000 ;
    END
  END mstreams_o[77]
  PIN mstreams_o[78]
    DIRECTION OUTPUT TRISTATE ;
    USE SIGNAL ;
    ANTENNADIFFAREA 0.795200 ;
    PORT
      LAYER met2 ;
        RECT 1438.050 0.000 1438.330 4.000 ;
    END
  END mstreams_o[78]
  PIN mstreams_o[79]
    DIRECTION OUTPUT TRISTATE ;
    USE SIGNAL ;
    ANTENNADIFFAREA 0.795200 ;
    PORT
      LAYER met2 ;
        RECT 1440.350 0.000 1440.630 4.000 ;
    END
  END mstreams_o[79]
  PIN mstreams_o[7]
    DIRECTION OUTPUT TRISTATE ;
    USE SIGNAL ;
    ANTENNADIFFAREA 0.795200 ;
    PORT
      LAYER met2 ;
        RECT 1274.750 0.000 1275.030 4.000 ;
    END
  END mstreams_o[7]
  PIN mstreams_o[80]
    DIRECTION OUTPUT TRISTATE ;
    USE SIGNAL ;
    ANTENNADIFFAREA 0.795200 ;
    PORT
      LAYER met2 ;
        RECT 1442.650 0.000 1442.930 4.000 ;
    END
  END mstreams_o[80]
  PIN mstreams_o[81]
    DIRECTION OUTPUT TRISTATE ;
    USE SIGNAL ;
    ANTENNADIFFAREA 0.795200 ;
    PORT
      LAYER met2 ;
        RECT 1444.950 0.000 1445.230 4.000 ;
    END
  END mstreams_o[81]
  PIN mstreams_o[82]
    DIRECTION OUTPUT TRISTATE ;
    USE SIGNAL ;
    ANTENNADIFFAREA 0.795200 ;
    PORT
      LAYER met2 ;
        RECT 1447.250 0.000 1447.530 4.000 ;
    END
  END mstreams_o[82]
  PIN mstreams_o[83]
    DIRECTION OUTPUT TRISTATE ;
    USE SIGNAL ;
    ANTENNADIFFAREA 0.795200 ;
    PORT
      LAYER met2 ;
        RECT 1449.550 0.000 1449.830 4.000 ;
    END
  END mstreams_o[83]
  PIN mstreams_o[84]
    DIRECTION OUTPUT TRISTATE ;
    USE SIGNAL ;
    ANTENNADIFFAREA 0.795200 ;
    PORT
      LAYER met2 ;
        RECT 1451.850 0.000 1452.130 4.000 ;
    END
  END mstreams_o[84]
  PIN mstreams_o[85]
    DIRECTION OUTPUT TRISTATE ;
    USE SIGNAL ;
    ANTENNADIFFAREA 0.795200 ;
    PORT
      LAYER met2 ;
        RECT 1454.150 0.000 1454.430 4.000 ;
    END
  END mstreams_o[85]
  PIN mstreams_o[86]
    DIRECTION OUTPUT TRISTATE ;
    USE SIGNAL ;
    ANTENNADIFFAREA 0.795200 ;
    PORT
      LAYER met2 ;
        RECT 1456.450 0.000 1456.730 4.000 ;
    END
  END mstreams_o[86]
  PIN mstreams_o[87]
    DIRECTION OUTPUT TRISTATE ;
    USE SIGNAL ;
    ANTENNADIFFAREA 0.795200 ;
    PORT
      LAYER met2 ;
        RECT 1458.750 0.000 1459.030 4.000 ;
    END
  END mstreams_o[87]
  PIN mstreams_o[88]
    DIRECTION OUTPUT TRISTATE ;
    USE SIGNAL ;
    ANTENNADIFFAREA 0.795200 ;
    PORT
      LAYER met2 ;
        RECT 1461.050 0.000 1461.330 4.000 ;
    END
  END mstreams_o[88]
  PIN mstreams_o[89]
    DIRECTION OUTPUT TRISTATE ;
    USE SIGNAL ;
    ANTENNADIFFAREA 0.795200 ;
    PORT
      LAYER met2 ;
        RECT 1463.350 0.000 1463.630 4.000 ;
    END
  END mstreams_o[89]
  PIN mstreams_o[8]
    DIRECTION OUTPUT TRISTATE ;
    USE SIGNAL ;
    ANTENNADIFFAREA 0.795200 ;
    PORT
      LAYER met2 ;
        RECT 1277.050 0.000 1277.330 4.000 ;
    END
  END mstreams_o[8]
  PIN mstreams_o[90]
    DIRECTION OUTPUT TRISTATE ;
    USE SIGNAL ;
    ANTENNADIFFAREA 0.795200 ;
    PORT
      LAYER met2 ;
        RECT 1465.650 0.000 1465.930 4.000 ;
    END
  END mstreams_o[90]
  PIN mstreams_o[91]
    DIRECTION OUTPUT TRISTATE ;
    USE SIGNAL ;
    ANTENNADIFFAREA 0.795200 ;
    PORT
      LAYER met2 ;
        RECT 1467.950 0.000 1468.230 4.000 ;
    END
  END mstreams_o[91]
  PIN mstreams_o[92]
    DIRECTION OUTPUT TRISTATE ;
    USE SIGNAL ;
    ANTENNADIFFAREA 0.795200 ;
    PORT
      LAYER met2 ;
        RECT 1470.250 0.000 1470.530 4.000 ;
    END
  END mstreams_o[92]
  PIN mstreams_o[93]
    DIRECTION OUTPUT TRISTATE ;
    USE SIGNAL ;
    ANTENNADIFFAREA 0.795200 ;
    PORT
      LAYER met2 ;
        RECT 1472.550 0.000 1472.830 4.000 ;
    END
  END mstreams_o[93]
  PIN mstreams_o[94]
    DIRECTION OUTPUT TRISTATE ;
    USE SIGNAL ;
    ANTENNADIFFAREA 0.795200 ;
    PORT
      LAYER met2 ;
        RECT 1474.850 0.000 1475.130 4.000 ;
    END
  END mstreams_o[94]
  PIN mstreams_o[95]
    DIRECTION OUTPUT TRISTATE ;
    USE SIGNAL ;
    ANTENNADIFFAREA 0.795200 ;
    PORT
      LAYER met2 ;
        RECT 1477.150 0.000 1477.430 4.000 ;
    END
  END mstreams_o[95]
  PIN mstreams_o[96]
    DIRECTION OUTPUT TRISTATE ;
    USE SIGNAL ;
    ANTENNADIFFAREA 0.795200 ;
    PORT
      LAYER met2 ;
        RECT 1479.450 0.000 1479.730 4.000 ;
    END
  END mstreams_o[96]
  PIN mstreams_o[97]
    DIRECTION OUTPUT TRISTATE ;
    USE SIGNAL ;
    ANTENNADIFFAREA 0.795200 ;
    PORT
      LAYER met2 ;
        RECT 1481.750 0.000 1482.030 4.000 ;
    END
  END mstreams_o[97]
  PIN mstreams_o[98]
    DIRECTION OUTPUT TRISTATE ;
    USE SIGNAL ;
    ANTENNADIFFAREA 0.795200 ;
    PORT
      LAYER met2 ;
        RECT 1484.050 0.000 1484.330 4.000 ;
    END
  END mstreams_o[98]
  PIN mstreams_o[99]
    DIRECTION OUTPUT TRISTATE ;
    USE SIGNAL ;
    PORT
      LAYER met2 ;
        RECT 1486.350 0.000 1486.630 4.000 ;
    END
  END mstreams_o[99]
  PIN mstreams_o[9]
    DIRECTION OUTPUT TRISTATE ;
    USE SIGNAL ;
    ANTENNADIFFAREA 0.795200 ;
    PORT
      LAYER met2 ;
        RECT 1279.350 0.000 1279.630 4.000 ;
    END
  END mstreams_o[9]
  PIN nrst_i
    DIRECTION INPUT ;
    USE SIGNAL ;
    ANTENNAGATEAREA 0.852000 ;
    PORT
      LAYER met2 ;
        RECT 110.950 0.000 111.230 4.000 ;
    END
  END nrst_i
  PIN sstreams_i[0]
    DIRECTION INPUT ;
    USE SIGNAL ;
    ANTENNAGATEAREA 0.196500 ;
    PORT
      LAYER met2 ;
        RECT 803.250 0.000 803.530 4.000 ;
    END
  END sstreams_i[0]
  PIN sstreams_i[100]
    DIRECTION INPUT ;
    USE SIGNAL ;
    ANTENNAGATEAREA 0.426000 ;
    PORT
      LAYER met2 ;
        RECT 1033.250 0.000 1033.530 4.000 ;
    END
  END sstreams_i[100]
  PIN sstreams_i[101]
    DIRECTION INPUT ;
    USE SIGNAL ;
    ANTENNAGATEAREA 0.426000 ;
    PORT
      LAYER met2 ;
        RECT 1035.550 0.000 1035.830 4.000 ;
    END
  END sstreams_i[101]
  PIN sstreams_i[102]
    DIRECTION INPUT ;
    USE SIGNAL ;
    ANTENNAGATEAREA 0.426000 ;
    PORT
      LAYER met2 ;
        RECT 1037.850 0.000 1038.130 4.000 ;
    END
  END sstreams_i[102]
  PIN sstreams_i[103]
    DIRECTION INPUT ;
    USE SIGNAL ;
    ANTENNAGATEAREA 0.426000 ;
    PORT
      LAYER met2 ;
        RECT 1040.150 0.000 1040.430 4.000 ;
    END
  END sstreams_i[103]
  PIN sstreams_i[104]
    DIRECTION INPUT ;
    USE SIGNAL ;
    ANTENNAGATEAREA 0.495000 ;
    PORT
      LAYER met2 ;
        RECT 1042.450 0.000 1042.730 4.000 ;
    END
  END sstreams_i[104]
  PIN sstreams_i[105]
    DIRECTION INPUT ;
    USE SIGNAL ;
    ANTENNAGATEAREA 0.426000 ;
    PORT
      LAYER met2 ;
        RECT 1044.750 0.000 1045.030 4.000 ;
    END
  END sstreams_i[105]
  PIN sstreams_i[106]
    DIRECTION INPUT ;
    USE SIGNAL ;
    ANTENNAGATEAREA 0.426000 ;
    PORT
      LAYER met2 ;
        RECT 1047.050 0.000 1047.330 4.000 ;
    END
  END sstreams_i[106]
  PIN sstreams_i[107]
    DIRECTION INPUT ;
    USE SIGNAL ;
    ANTENNAGATEAREA 0.426000 ;
    PORT
      LAYER met2 ;
        RECT 1049.350 0.000 1049.630 4.000 ;
    END
  END sstreams_i[107]
  PIN sstreams_i[108]
    DIRECTION INPUT ;
    USE SIGNAL ;
    ANTENNAGATEAREA 0.426000 ;
    PORT
      LAYER met2 ;
        RECT 1051.650 0.000 1051.930 4.000 ;
    END
  END sstreams_i[108]
  PIN sstreams_i[109]
    DIRECTION INPUT ;
    USE SIGNAL ;
    ANTENNAGATEAREA 0.426000 ;
    PORT
      LAYER met2 ;
        RECT 1053.950 0.000 1054.230 4.000 ;
    END
  END sstreams_i[109]
  PIN sstreams_i[10]
    DIRECTION INPUT ;
    USE SIGNAL ;
    ANTENNAGATEAREA 0.196500 ;
    PORT
      LAYER met2 ;
        RECT 826.250 0.000 826.530 4.000 ;
    END
  END sstreams_i[10]
  PIN sstreams_i[110]
    DIRECTION INPUT ;
    USE SIGNAL ;
    ANTENNAGATEAREA 0.426000 ;
    PORT
      LAYER met2 ;
        RECT 1056.250 0.000 1056.530 4.000 ;
    END
  END sstreams_i[110]
  PIN sstreams_i[111]
    DIRECTION INPUT ;
    USE SIGNAL ;
    ANTENNAGATEAREA 0.426000 ;
    PORT
      LAYER met2 ;
        RECT 1058.550 0.000 1058.830 4.000 ;
    END
  END sstreams_i[111]
  PIN sstreams_i[112]
    DIRECTION INPUT ;
    USE SIGNAL ;
    ANTENNAGATEAREA 0.426000 ;
    PORT
      LAYER met2 ;
        RECT 1060.850 0.000 1061.130 4.000 ;
    END
  END sstreams_i[112]
  PIN sstreams_i[113]
    DIRECTION INPUT ;
    USE SIGNAL ;
    ANTENNAGATEAREA 0.426000 ;
    PORT
      LAYER met2 ;
        RECT 1063.150 0.000 1063.430 4.000 ;
    END
  END sstreams_i[113]
  PIN sstreams_i[114]
    DIRECTION INPUT ;
    USE SIGNAL ;
    ANTENNAGATEAREA 0.426000 ;
    PORT
      LAYER met2 ;
        RECT 1065.450 0.000 1065.730 4.000 ;
    END
  END sstreams_i[114]
  PIN sstreams_i[115]
    DIRECTION INPUT ;
    USE SIGNAL ;
    ANTENNAGATEAREA 0.426000 ;
    PORT
      LAYER met2 ;
        RECT 1067.750 0.000 1068.030 4.000 ;
    END
  END sstreams_i[115]
  PIN sstreams_i[116]
    DIRECTION INPUT ;
    USE SIGNAL ;
    ANTENNAGATEAREA 0.426000 ;
    PORT
      LAYER met2 ;
        RECT 1070.050 0.000 1070.330 4.000 ;
    END
  END sstreams_i[116]
  PIN sstreams_i[117]
    DIRECTION INPUT ;
    USE SIGNAL ;
    ANTENNAGATEAREA 0.426000 ;
    PORT
      LAYER met2 ;
        RECT 1072.350 0.000 1072.630 4.000 ;
    END
  END sstreams_i[117]
  PIN sstreams_i[118]
    DIRECTION INPUT ;
    USE SIGNAL ;
    ANTENNAGATEAREA 0.426000 ;
    PORT
      LAYER met2 ;
        RECT 1074.650 0.000 1074.930 4.000 ;
    END
  END sstreams_i[118]
  PIN sstreams_i[119]
    DIRECTION INPUT ;
    USE SIGNAL ;
    ANTENNAGATEAREA 0.426000 ;
    PORT
      LAYER met2 ;
        RECT 1076.950 0.000 1077.230 4.000 ;
    END
  END sstreams_i[119]
  PIN sstreams_i[11]
    DIRECTION INPUT ;
    USE SIGNAL ;
    ANTENNAGATEAREA 0.196500 ;
    PORT
      LAYER met2 ;
        RECT 828.550 0.000 828.830 4.000 ;
    END
  END sstreams_i[11]
  PIN sstreams_i[120]
    DIRECTION INPUT ;
    USE SIGNAL ;
    ANTENNAGATEAREA 0.426000 ;
    PORT
      LAYER met2 ;
        RECT 1079.250 0.000 1079.530 4.000 ;
    END
  END sstreams_i[120]
  PIN sstreams_i[121]
    DIRECTION INPUT ;
    USE SIGNAL ;
    ANTENNAGATEAREA 0.426000 ;
    PORT
      LAYER met2 ;
        RECT 1081.550 0.000 1081.830 4.000 ;
    END
  END sstreams_i[121]
  PIN sstreams_i[122]
    DIRECTION INPUT ;
    USE SIGNAL ;
    ANTENNAGATEAREA 0.426000 ;
    PORT
      LAYER met2 ;
        RECT 1083.850 0.000 1084.130 4.000 ;
    END
  END sstreams_i[122]
  PIN sstreams_i[123]
    DIRECTION INPUT ;
    USE SIGNAL ;
    ANTENNAGATEAREA 0.426000 ;
    PORT
      LAYER met2 ;
        RECT 1086.150 0.000 1086.430 4.000 ;
    END
  END sstreams_i[123]
  PIN sstreams_i[124]
    DIRECTION INPUT ;
    USE SIGNAL ;
    ANTENNAGATEAREA 0.426000 ;
    PORT
      LAYER met2 ;
        RECT 1088.450 0.000 1088.730 4.000 ;
    END
  END sstreams_i[124]
  PIN sstreams_i[125]
    DIRECTION INPUT ;
    USE SIGNAL ;
    ANTENNAGATEAREA 0.426000 ;
    PORT
      LAYER met2 ;
        RECT 1090.750 0.000 1091.030 4.000 ;
    END
  END sstreams_i[125]
  PIN sstreams_i[126]
    DIRECTION INPUT ;
    USE SIGNAL ;
    ANTENNAGATEAREA 0.426000 ;
    PORT
      LAYER met2 ;
        RECT 1093.050 0.000 1093.330 4.000 ;
    END
  END sstreams_i[126]
  PIN sstreams_i[127]
    DIRECTION INPUT ;
    USE SIGNAL ;
    ANTENNAGATEAREA 0.426000 ;
    PORT
      LAYER met2 ;
        RECT 1095.350 0.000 1095.630 4.000 ;
    END
  END sstreams_i[127]
  PIN sstreams_i[128]
    DIRECTION INPUT ;
    USE SIGNAL ;
    ANTENNAGATEAREA 0.247500 ;
    PORT
      LAYER met2 ;
        RECT 1097.650 0.000 1097.930 4.000 ;
    END
  END sstreams_i[128]
  PIN sstreams_i[129]
    DIRECTION INPUT ;
    USE SIGNAL ;
    ANTENNAGATEAREA 0.426000 ;
    PORT
      LAYER met2 ;
        RECT 1099.950 0.000 1100.230 4.000 ;
    END
  END sstreams_i[129]
  PIN sstreams_i[12]
    DIRECTION INPUT ;
    USE SIGNAL ;
    ANTENNAGATEAREA 0.196500 ;
    PORT
      LAYER met2 ;
        RECT 830.850 0.000 831.130 4.000 ;
    END
  END sstreams_i[12]
  PIN sstreams_i[130]
    DIRECTION INPUT ;
    USE SIGNAL ;
    ANTENNAGATEAREA 0.426000 ;
    PORT
      LAYER met2 ;
        RECT 1102.250 0.000 1102.530 4.000 ;
    END
  END sstreams_i[130]
  PIN sstreams_i[131]
    DIRECTION INPUT ;
    USE SIGNAL ;
    ANTENNAGATEAREA 0.426000 ;
    PORT
      LAYER met2 ;
        RECT 1104.550 0.000 1104.830 4.000 ;
    END
  END sstreams_i[131]
  PIN sstreams_i[132]
    DIRECTION INPUT ;
    USE SIGNAL ;
    ANTENNAGATEAREA 0.426000 ;
    PORT
      LAYER met2 ;
        RECT 1106.850 0.000 1107.130 4.000 ;
    END
  END sstreams_i[132]
  PIN sstreams_i[133]
    DIRECTION INPUT ;
    USE SIGNAL ;
    ANTENNAGATEAREA 0.426000 ;
    PORT
      LAYER met2 ;
        RECT 1109.150 0.000 1109.430 4.000 ;
    END
  END sstreams_i[133]
  PIN sstreams_i[134]
    DIRECTION INPUT ;
    USE SIGNAL ;
    ANTENNAGATEAREA 0.426000 ;
    PORT
      LAYER met2 ;
        RECT 1111.450 0.000 1111.730 4.000 ;
    END
  END sstreams_i[134]
  PIN sstreams_i[135]
    DIRECTION INPUT ;
    USE SIGNAL ;
    ANTENNAGATEAREA 0.426000 ;
    PORT
      LAYER met2 ;
        RECT 1113.750 0.000 1114.030 4.000 ;
    END
  END sstreams_i[135]
  PIN sstreams_i[136]
    DIRECTION INPUT ;
    USE SIGNAL ;
    ANTENNAGATEAREA 0.426000 ;
    PORT
      LAYER met2 ;
        RECT 1116.050 0.000 1116.330 4.000 ;
    END
  END sstreams_i[136]
  PIN sstreams_i[137]
    DIRECTION INPUT ;
    USE SIGNAL ;
    ANTENNAGATEAREA 0.426000 ;
    PORT
      LAYER met2 ;
        RECT 1118.350 0.000 1118.630 4.000 ;
    END
  END sstreams_i[137]
  PIN sstreams_i[138]
    DIRECTION INPUT ;
    USE SIGNAL ;
    ANTENNAGATEAREA 0.247500 ;
    PORT
      LAYER met2 ;
        RECT 1120.650 0.000 1120.930 4.000 ;
    END
  END sstreams_i[138]
  PIN sstreams_i[139]
    DIRECTION INPUT ;
    USE SIGNAL ;
    ANTENNAGATEAREA 0.426000 ;
    PORT
      LAYER met2 ;
        RECT 1122.950 0.000 1123.230 4.000 ;
    END
  END sstreams_i[139]
  PIN sstreams_i[13]
    DIRECTION INPUT ;
    USE SIGNAL ;
    ANTENNAGATEAREA 0.196500 ;
    PORT
      LAYER met2 ;
        RECT 833.150 0.000 833.430 4.000 ;
    END
  END sstreams_i[13]
  PIN sstreams_i[140]
    DIRECTION INPUT ;
    USE SIGNAL ;
    ANTENNAGATEAREA 0.426000 ;
    PORT
      LAYER met2 ;
        RECT 1125.250 0.000 1125.530 4.000 ;
    END
  END sstreams_i[140]
  PIN sstreams_i[141]
    DIRECTION INPUT ;
    USE SIGNAL ;
    ANTENNAGATEAREA 0.426000 ;
    PORT
      LAYER met2 ;
        RECT 1127.550 0.000 1127.830 4.000 ;
    END
  END sstreams_i[141]
  PIN sstreams_i[142]
    DIRECTION INPUT ;
    USE SIGNAL ;
    ANTENNAGATEAREA 0.426000 ;
    PORT
      LAYER met2 ;
        RECT 1129.850 0.000 1130.130 4.000 ;
    END
  END sstreams_i[142]
  PIN sstreams_i[143]
    DIRECTION INPUT ;
    USE SIGNAL ;
    ANTENNAGATEAREA 0.426000 ;
    PORT
      LAYER met2 ;
        RECT 1132.150 0.000 1132.430 4.000 ;
    END
  END sstreams_i[143]
  PIN sstreams_i[144]
    DIRECTION INPUT ;
    USE SIGNAL ;
    ANTENNAGATEAREA 0.426000 ;
    PORT
      LAYER met2 ;
        RECT 1134.450 0.000 1134.730 4.000 ;
    END
  END sstreams_i[144]
  PIN sstreams_i[145]
    DIRECTION INPUT ;
    USE SIGNAL ;
    ANTENNAGATEAREA 0.426000 ;
    PORT
      LAYER met2 ;
        RECT 1136.750 0.000 1137.030 4.000 ;
    END
  END sstreams_i[145]
  PIN sstreams_i[146]
    DIRECTION INPUT ;
    USE SIGNAL ;
    ANTENNAGATEAREA 0.213000 ;
    PORT
      LAYER met2 ;
        RECT 1139.050 0.000 1139.330 4.000 ;
    END
  END sstreams_i[146]
  PIN sstreams_i[147]
    DIRECTION INPUT ;
    USE SIGNAL ;
    ANTENNAGATEAREA 0.213000 ;
    PORT
      LAYER met2 ;
        RECT 1141.350 0.000 1141.630 4.000 ;
    END
  END sstreams_i[147]
  PIN sstreams_i[148]
    DIRECTION INPUT ;
    USE SIGNAL ;
    ANTENNAGATEAREA 0.213000 ;
    PORT
      LAYER met2 ;
        RECT 1143.650 0.000 1143.930 4.000 ;
    END
  END sstreams_i[148]
  PIN sstreams_i[149]
    DIRECTION INPUT ;
    USE SIGNAL ;
    ANTENNAGATEAREA 0.213000 ;
    PORT
      LAYER met2 ;
        RECT 1145.950 0.000 1146.230 4.000 ;
    END
  END sstreams_i[149]
  PIN sstreams_i[14]
    DIRECTION INPUT ;
    USE SIGNAL ;
    ANTENNAGATEAREA 0.196500 ;
    PORT
      LAYER met2 ;
        RECT 835.450 0.000 835.730 4.000 ;
    END
  END sstreams_i[14]
  PIN sstreams_i[150]
    DIRECTION INPUT ;
    USE SIGNAL ;
    ANTENNAGATEAREA 0.213000 ;
    PORT
      LAYER met2 ;
        RECT 1148.250 0.000 1148.530 4.000 ;
    END
  END sstreams_i[150]
  PIN sstreams_i[151]
    DIRECTION INPUT ;
    USE SIGNAL ;
    ANTENNAGATEAREA 0.213000 ;
    PORT
      LAYER met2 ;
        RECT 1150.550 0.000 1150.830 4.000 ;
    END
  END sstreams_i[151]
  PIN sstreams_i[152]
    DIRECTION INPUT ;
    USE SIGNAL ;
    ANTENNAGATEAREA 0.213000 ;
    PORT
      LAYER met2 ;
        RECT 1152.850 0.000 1153.130 4.000 ;
    END
  END sstreams_i[152]
  PIN sstreams_i[153]
    DIRECTION INPUT ;
    USE SIGNAL ;
    ANTENNAGATEAREA 0.213000 ;
    PORT
      LAYER met2 ;
        RECT 1155.150 0.000 1155.430 4.000 ;
    END
  END sstreams_i[153]
  PIN sstreams_i[154]
    DIRECTION INPUT ;
    USE SIGNAL ;
    ANTENNAGATEAREA 0.213000 ;
    PORT
      LAYER met2 ;
        RECT 1157.450 0.000 1157.730 4.000 ;
    END
  END sstreams_i[154]
  PIN sstreams_i[155]
    DIRECTION INPUT ;
    USE SIGNAL ;
    ANTENNAGATEAREA 0.213000 ;
    PORT
      LAYER met2 ;
        RECT 1159.750 0.000 1160.030 4.000 ;
    END
  END sstreams_i[155]
  PIN sstreams_i[156]
    DIRECTION INPUT ;
    USE SIGNAL ;
    ANTENNAGATEAREA 0.213000 ;
    PORT
      LAYER met2 ;
        RECT 1162.050 0.000 1162.330 4.000 ;
    END
  END sstreams_i[156]
  PIN sstreams_i[157]
    DIRECTION INPUT ;
    USE SIGNAL ;
    ANTENNAGATEAREA 0.213000 ;
    PORT
      LAYER met2 ;
        RECT 1164.350 0.000 1164.630 4.000 ;
    END
  END sstreams_i[157]
  PIN sstreams_i[158]
    DIRECTION INPUT ;
    USE SIGNAL ;
    ANTENNAGATEAREA 0.213000 ;
    PORT
      LAYER met2 ;
        RECT 1166.650 0.000 1166.930 4.000 ;
    END
  END sstreams_i[158]
  PIN sstreams_i[159]
    DIRECTION INPUT ;
    USE SIGNAL ;
    ANTENNAGATEAREA 0.247500 ;
    PORT
      LAYER met2 ;
        RECT 1168.950 0.000 1169.230 4.000 ;
    END
  END sstreams_i[159]
  PIN sstreams_i[15]
    DIRECTION INPUT ;
    USE SIGNAL ;
    ANTENNAGATEAREA 0.196500 ;
    PORT
      LAYER met2 ;
        RECT 837.750 0.000 838.030 4.000 ;
    END
  END sstreams_i[15]
  PIN sstreams_i[160]
    DIRECTION INPUT ;
    USE SIGNAL ;
    ANTENNAGATEAREA 0.247500 ;
    PORT
      LAYER met2 ;
        RECT 1171.250 0.000 1171.530 4.000 ;
    END
  END sstreams_i[160]
  PIN sstreams_i[161]
    DIRECTION INPUT ;
    USE SIGNAL ;
    ANTENNAGATEAREA 0.247500 ;
    PORT
      LAYER met2 ;
        RECT 1173.550 0.000 1173.830 4.000 ;
    END
  END sstreams_i[161]
  PIN sstreams_i[162]
    DIRECTION INPUT ;
    USE SIGNAL ;
    ANTENNAGATEAREA 0.247500 ;
    PORT
      LAYER met2 ;
        RECT 1175.850 0.000 1176.130 4.000 ;
    END
  END sstreams_i[162]
  PIN sstreams_i[163]
    DIRECTION INPUT ;
    USE SIGNAL ;
    ANTENNAGATEAREA 0.247500 ;
    PORT
      LAYER met2 ;
        RECT 1178.150 0.000 1178.430 4.000 ;
    END
  END sstreams_i[163]
  PIN sstreams_i[164]
    DIRECTION INPUT ;
    USE SIGNAL ;
    ANTENNAGATEAREA 0.247500 ;
    PORT
      LAYER met2 ;
        RECT 1180.450 0.000 1180.730 4.000 ;
    END
  END sstreams_i[164]
  PIN sstreams_i[165]
    DIRECTION INPUT ;
    USE SIGNAL ;
    ANTENNAGATEAREA 0.247500 ;
    PORT
      LAYER met2 ;
        RECT 1182.750 0.000 1183.030 4.000 ;
    END
  END sstreams_i[165]
  PIN sstreams_i[166]
    DIRECTION INPUT ;
    USE SIGNAL ;
    ANTENNAGATEAREA 0.247500 ;
    PORT
      LAYER met2 ;
        RECT 1185.050 0.000 1185.330 4.000 ;
    END
  END sstreams_i[166]
  PIN sstreams_i[167]
    DIRECTION INPUT ;
    USE SIGNAL ;
    ANTENNAGATEAREA 0.247500 ;
    PORT
      LAYER met2 ;
        RECT 1187.350 0.000 1187.630 4.000 ;
    END
  END sstreams_i[167]
  PIN sstreams_i[168]
    DIRECTION INPUT ;
    USE SIGNAL ;
    ANTENNAGATEAREA 0.247500 ;
    PORT
      LAYER met2 ;
        RECT 1189.650 0.000 1189.930 4.000 ;
    END
  END sstreams_i[168]
  PIN sstreams_i[169]
    DIRECTION INPUT ;
    USE SIGNAL ;
    ANTENNAGATEAREA 0.247500 ;
    PORT
      LAYER met2 ;
        RECT 1191.950 0.000 1192.230 4.000 ;
    END
  END sstreams_i[169]
  PIN sstreams_i[16]
    DIRECTION INPUT ;
    USE SIGNAL ;
    ANTENNAGATEAREA 0.196500 ;
    PORT
      LAYER met2 ;
        RECT 840.050 0.000 840.330 4.000 ;
    END
  END sstreams_i[16]
  PIN sstreams_i[170]
    DIRECTION INPUT ;
    USE SIGNAL ;
    ANTENNAGATEAREA 0.247500 ;
    PORT
      LAYER met2 ;
        RECT 1194.250 0.000 1194.530 4.000 ;
    END
  END sstreams_i[170]
  PIN sstreams_i[171]
    DIRECTION INPUT ;
    USE SIGNAL ;
    ANTENNAGATEAREA 0.426000 ;
    PORT
      LAYER met2 ;
        RECT 1196.550 0.000 1196.830 4.000 ;
    END
  END sstreams_i[171]
  PIN sstreams_i[172]
    DIRECTION INPUT ;
    USE SIGNAL ;
    ANTENNAGATEAREA 0.426000 ;
    PORT
      LAYER met2 ;
        RECT 1198.850 0.000 1199.130 4.000 ;
    END
  END sstreams_i[172]
  PIN sstreams_i[173]
    DIRECTION INPUT ;
    USE SIGNAL ;
    ANTENNAGATEAREA 0.426000 ;
    PORT
      LAYER met2 ;
        RECT 1201.150 0.000 1201.430 4.000 ;
    END
  END sstreams_i[173]
  PIN sstreams_i[174]
    DIRECTION INPUT ;
    USE SIGNAL ;
    ANTENNAGATEAREA 0.247500 ;
    PORT
      LAYER met2 ;
        RECT 1203.450 0.000 1203.730 4.000 ;
    END
  END sstreams_i[174]
  PIN sstreams_i[175]
    DIRECTION INPUT ;
    USE SIGNAL ;
    ANTENNAGATEAREA 0.426000 ;
    PORT
      LAYER met2 ;
        RECT 1205.750 0.000 1206.030 4.000 ;
    END
  END sstreams_i[175]
  PIN sstreams_i[176]
    DIRECTION INPUT ;
    USE SIGNAL ;
    ANTENNAGATEAREA 0.247500 ;
    PORT
      LAYER met2 ;
        RECT 1208.050 0.000 1208.330 4.000 ;
    END
  END sstreams_i[176]
  PIN sstreams_i[177]
    DIRECTION INPUT ;
    USE SIGNAL ;
    ANTENNAGATEAREA 0.426000 ;
    PORT
      LAYER met2 ;
        RECT 1210.350 0.000 1210.630 4.000 ;
    END
  END sstreams_i[177]
  PIN sstreams_i[178]
    DIRECTION INPUT ;
    USE SIGNAL ;
    ANTENNAGATEAREA 0.426000 ;
    PORT
      LAYER met2 ;
        RECT 1212.650 0.000 1212.930 4.000 ;
    END
  END sstreams_i[178]
  PIN sstreams_i[179]
    DIRECTION INPUT ;
    USE SIGNAL ;
    ANTENNAGATEAREA 0.426000 ;
    PORT
      LAYER met2 ;
        RECT 1214.950 0.000 1215.230 4.000 ;
    END
  END sstreams_i[179]
  PIN sstreams_i[17]
    DIRECTION INPUT ;
    USE SIGNAL ;
    ANTENNAGATEAREA 0.196500 ;
    PORT
      LAYER met2 ;
        RECT 842.350 0.000 842.630 4.000 ;
    END
  END sstreams_i[17]
  PIN sstreams_i[180]
    DIRECTION INPUT ;
    USE SIGNAL ;
    ANTENNAGATEAREA 0.247500 ;
    PORT
      LAYER met2 ;
        RECT 1217.250 0.000 1217.530 4.000 ;
    END
  END sstreams_i[180]
  PIN sstreams_i[181]
    DIRECTION INPUT ;
    USE SIGNAL ;
    ANTENNAGATEAREA 0.247500 ;
    PORT
      LAYER met2 ;
        RECT 1219.550 0.000 1219.830 4.000 ;
    END
  END sstreams_i[181]
  PIN sstreams_i[182]
    DIRECTION INPUT ;
    USE SIGNAL ;
    ANTENNAGATEAREA 0.247500 ;
    PORT
      LAYER met2 ;
        RECT 1221.850 0.000 1222.130 4.000 ;
    END
  END sstreams_i[182]
  PIN sstreams_i[183]
    DIRECTION INPUT ;
    USE SIGNAL ;
    ANTENNAGATEAREA 0.247500 ;
    PORT
      LAYER met2 ;
        RECT 1224.150 0.000 1224.430 4.000 ;
    END
  END sstreams_i[183]
  PIN sstreams_i[184]
    DIRECTION INPUT ;
    USE SIGNAL ;
    ANTENNAGATEAREA 0.247500 ;
    PORT
      LAYER met2 ;
        RECT 1226.450 0.000 1226.730 4.000 ;
    END
  END sstreams_i[184]
  PIN sstreams_i[185]
    DIRECTION INPUT ;
    USE SIGNAL ;
    ANTENNAGATEAREA 0.426000 ;
    PORT
      LAYER met2 ;
        RECT 1228.750 0.000 1229.030 4.000 ;
    END
  END sstreams_i[185]
  PIN sstreams_i[186]
    DIRECTION INPUT ;
    USE SIGNAL ;
    ANTENNAGATEAREA 0.247500 ;
    PORT
      LAYER met2 ;
        RECT 1231.050 0.000 1231.330 4.000 ;
    END
  END sstreams_i[186]
  PIN sstreams_i[187]
    DIRECTION INPUT ;
    USE SIGNAL ;
    ANTENNAGATEAREA 0.426000 ;
    PORT
      LAYER met2 ;
        RECT 1233.350 0.000 1233.630 4.000 ;
    END
  END sstreams_i[187]
  PIN sstreams_i[188]
    DIRECTION INPUT ;
    USE SIGNAL ;
    ANTENNAGATEAREA 0.426000 ;
    PORT
      LAYER met2 ;
        RECT 1235.650 0.000 1235.930 4.000 ;
    END
  END sstreams_i[188]
  PIN sstreams_i[189]
    DIRECTION INPUT ;
    USE SIGNAL ;
    ANTENNAGATEAREA 0.426000 ;
    PORT
      LAYER met2 ;
        RECT 1237.950 0.000 1238.230 4.000 ;
    END
  END sstreams_i[189]
  PIN sstreams_i[18]
    DIRECTION INPUT ;
    USE SIGNAL ;
    ANTENNAGATEAREA 0.196500 ;
    PORT
      LAYER met2 ;
        RECT 844.650 0.000 844.930 4.000 ;
    END
  END sstreams_i[18]
  PIN sstreams_i[190]
    DIRECTION INPUT ;
    USE SIGNAL ;
    ANTENNAGATEAREA 0.426000 ;
    PORT
      LAYER met2 ;
        RECT 1240.250 0.000 1240.530 4.000 ;
    END
  END sstreams_i[190]
  PIN sstreams_i[191]
    DIRECTION INPUT ;
    USE SIGNAL ;
    ANTENNAGATEAREA 0.426000 ;
    PORT
      LAYER met2 ;
        RECT 1242.550 0.000 1242.830 4.000 ;
    END
  END sstreams_i[191]
  PIN sstreams_i[192]
    DIRECTION INPUT ;
    USE SIGNAL ;
    ANTENNAGATEAREA 0.426000 ;
    PORT
      LAYER met2 ;
        RECT 1244.850 0.000 1245.130 4.000 ;
    END
  END sstreams_i[192]
  PIN sstreams_i[193]
    DIRECTION INPUT ;
    USE SIGNAL ;
    ANTENNAGATEAREA 0.426000 ;
    PORT
      LAYER met2 ;
        RECT 1247.150 0.000 1247.430 4.000 ;
    END
  END sstreams_i[193]
  PIN sstreams_i[194]
    DIRECTION INPUT ;
    USE SIGNAL ;
    ANTENNAGATEAREA 0.990000 ;
    PORT
      LAYER met2 ;
        RECT 1249.450 0.000 1249.730 4.000 ;
    END
  END sstreams_i[194]
  PIN sstreams_i[195]
    DIRECTION INPUT ;
    USE SIGNAL ;
    ANTENNAGATEAREA 0.426000 ;
    PORT
      LAYER met2 ;
        RECT 1251.750 0.000 1252.030 4.000 ;
    END
  END sstreams_i[195]
  PIN sstreams_i[196]
    DIRECTION INPUT ;
    USE SIGNAL ;
    ANTENNAGATEAREA 0.213000 ;
    PORT
      LAYER met2 ;
        RECT 113.250 0.000 113.530 4.000 ;
    END
  END sstreams_i[196]
  PIN sstreams_i[197]
    DIRECTION INPUT ;
    USE SIGNAL ;
    ANTENNAGATEAREA 0.213000 ;
    PORT
      LAYER met2 ;
        RECT 115.550 0.000 115.830 4.000 ;
    END
  END sstreams_i[197]
  PIN sstreams_i[198]
    DIRECTION INPUT ;
    USE SIGNAL ;
    ANTENNAGATEAREA 0.126000 ;
    PORT
      LAYER met2 ;
        RECT 117.850 0.000 118.130 4.000 ;
    END
  END sstreams_i[198]
  PIN sstreams_i[199]
    DIRECTION INPUT ;
    USE SIGNAL ;
    ANTENNAGATEAREA 0.213000 ;
    PORT
      LAYER met2 ;
        RECT 120.150 0.000 120.430 4.000 ;
    END
  END sstreams_i[199]
  PIN sstreams_i[19]
    DIRECTION INPUT ;
    USE SIGNAL ;
    ANTENNAGATEAREA 0.196500 ;
    PORT
      LAYER met2 ;
        RECT 846.950 0.000 847.230 4.000 ;
    END
  END sstreams_i[19]
  PIN sstreams_i[1]
    DIRECTION INPUT ;
    USE SIGNAL ;
    ANTENNAGATEAREA 0.196500 ;
    PORT
      LAYER met2 ;
        RECT 805.550 0.000 805.830 4.000 ;
    END
  END sstreams_i[1]
  PIN sstreams_i[200]
    DIRECTION INPUT ;
    USE SIGNAL ;
    ANTENNAGATEAREA 0.213000 ;
    PORT
      LAYER met2 ;
        RECT 122.450 0.000 122.730 4.000 ;
    END
  END sstreams_i[200]
  PIN sstreams_i[201]
    DIRECTION INPUT ;
    USE SIGNAL ;
    ANTENNAGATEAREA 0.213000 ;
    PORT
      LAYER met2 ;
        RECT 124.750 0.000 125.030 4.000 ;
    END
  END sstreams_i[201]
  PIN sstreams_i[202]
    DIRECTION INPUT ;
    USE SIGNAL ;
    ANTENNAGATEAREA 0.213000 ;
    PORT
      LAYER met2 ;
        RECT 127.050 0.000 127.330 4.000 ;
    END
  END sstreams_i[202]
  PIN sstreams_i[203]
    DIRECTION INPUT ;
    USE SIGNAL ;
    ANTENNAGATEAREA 0.213000 ;
    PORT
      LAYER met2 ;
        RECT 129.350 0.000 129.630 4.000 ;
    END
  END sstreams_i[203]
  PIN sstreams_i[204]
    DIRECTION INPUT ;
    USE SIGNAL ;
    ANTENNAGATEAREA 0.213000 ;
    PORT
      LAYER met2 ;
        RECT 131.650 0.000 131.930 4.000 ;
    END
  END sstreams_i[204]
  PIN sstreams_i[205]
    DIRECTION INPUT ;
    USE SIGNAL ;
    ANTENNAGATEAREA 0.213000 ;
    PORT
      LAYER met2 ;
        RECT 133.950 0.000 134.230 4.000 ;
    END
  END sstreams_i[205]
  PIN sstreams_i[206]
    DIRECTION INPUT ;
    USE SIGNAL ;
    ANTENNAGATEAREA 0.213000 ;
    PORT
      LAYER met2 ;
        RECT 136.250 0.000 136.530 4.000 ;
    END
  END sstreams_i[206]
  PIN sstreams_i[207]
    DIRECTION INPUT ;
    USE SIGNAL ;
    ANTENNAGATEAREA 0.213000 ;
    PORT
      LAYER met2 ;
        RECT 138.550 0.000 138.830 4.000 ;
    END
  END sstreams_i[207]
  PIN sstreams_i[208]
    DIRECTION INPUT ;
    USE SIGNAL ;
    ANTENNAGATEAREA 0.213000 ;
    PORT
      LAYER met2 ;
        RECT 140.850 0.000 141.130 4.000 ;
    END
  END sstreams_i[208]
  PIN sstreams_i[209]
    DIRECTION INPUT ;
    USE SIGNAL ;
    ANTENNAGATEAREA 0.213000 ;
    PORT
      LAYER met2 ;
        RECT 143.150 0.000 143.430 4.000 ;
    END
  END sstreams_i[209]
  PIN sstreams_i[20]
    DIRECTION INPUT ;
    USE SIGNAL ;
    ANTENNAGATEAREA 0.196500 ;
    PORT
      LAYER met2 ;
        RECT 849.250 0.000 849.530 4.000 ;
    END
  END sstreams_i[20]
  PIN sstreams_i[210]
    DIRECTION INPUT ;
    USE SIGNAL ;
    ANTENNAGATEAREA 0.213000 ;
    PORT
      LAYER met2 ;
        RECT 145.450 0.000 145.730 4.000 ;
    END
  END sstreams_i[210]
  PIN sstreams_i[211]
    DIRECTION INPUT ;
    USE SIGNAL ;
    ANTENNAGATEAREA 0.213000 ;
    PORT
      LAYER met2 ;
        RECT 147.750 0.000 148.030 4.000 ;
    END
  END sstreams_i[211]
  PIN sstreams_i[212]
    DIRECTION INPUT ;
    USE SIGNAL ;
    ANTENNAGATEAREA 0.213000 ;
    PORT
      LAYER met2 ;
        RECT 150.050 0.000 150.330 4.000 ;
    END
  END sstreams_i[212]
  PIN sstreams_i[213]
    DIRECTION INPUT ;
    USE SIGNAL ;
    ANTENNAGATEAREA 0.213000 ;
    PORT
      LAYER met2 ;
        RECT 152.350 0.000 152.630 4.000 ;
    END
  END sstreams_i[213]
  PIN sstreams_i[214]
    DIRECTION INPUT ;
    USE SIGNAL ;
    ANTENNAGATEAREA 0.213000 ;
    PORT
      LAYER met2 ;
        RECT 154.650 0.000 154.930 4.000 ;
    END
  END sstreams_i[214]
  PIN sstreams_i[215]
    DIRECTION INPUT ;
    USE SIGNAL ;
    ANTENNAGATEAREA 0.213000 ;
    PORT
      LAYER met2 ;
        RECT 156.950 0.000 157.230 4.000 ;
    END
  END sstreams_i[215]
  PIN sstreams_i[216]
    DIRECTION INPUT ;
    USE SIGNAL ;
    ANTENNAGATEAREA 0.213000 ;
    PORT
      LAYER met2 ;
        RECT 159.250 0.000 159.530 4.000 ;
    END
  END sstreams_i[216]
  PIN sstreams_i[217]
    DIRECTION INPUT ;
    USE SIGNAL ;
    ANTENNAGATEAREA 0.213000 ;
    PORT
      LAYER met2 ;
        RECT 161.550 0.000 161.830 4.000 ;
    END
  END sstreams_i[217]
  PIN sstreams_i[218]
    DIRECTION INPUT ;
    USE SIGNAL ;
    ANTENNAGATEAREA 0.213000 ;
    PORT
      LAYER met2 ;
        RECT 163.850 0.000 164.130 4.000 ;
    END
  END sstreams_i[218]
  PIN sstreams_i[219]
    DIRECTION INPUT ;
    USE SIGNAL ;
    ANTENNAGATEAREA 0.213000 ;
    PORT
      LAYER met2 ;
        RECT 166.150 0.000 166.430 4.000 ;
    END
  END sstreams_i[219]
  PIN sstreams_i[21]
    DIRECTION INPUT ;
    USE SIGNAL ;
    ANTENNAGATEAREA 0.196500 ;
    PORT
      LAYER met2 ;
        RECT 851.550 0.000 851.830 4.000 ;
    END
  END sstreams_i[21]
  PIN sstreams_i[220]
    DIRECTION INPUT ;
    USE SIGNAL ;
    ANTENNAGATEAREA 0.213000 ;
    PORT
      LAYER met2 ;
        RECT 168.450 0.000 168.730 4.000 ;
    END
  END sstreams_i[220]
  PIN sstreams_i[221]
    DIRECTION INPUT ;
    USE SIGNAL ;
    ANTENNAGATEAREA 0.213000 ;
    PORT
      LAYER met2 ;
        RECT 170.750 0.000 171.030 4.000 ;
    END
  END sstreams_i[221]
  PIN sstreams_i[222]
    DIRECTION INPUT ;
    USE SIGNAL ;
    ANTENNAGATEAREA 0.213000 ;
    PORT
      LAYER met2 ;
        RECT 173.050 0.000 173.330 4.000 ;
    END
  END sstreams_i[222]
  PIN sstreams_i[223]
    DIRECTION INPUT ;
    USE SIGNAL ;
    ANTENNAGATEAREA 0.213000 ;
    PORT
      LAYER met2 ;
        RECT 175.350 0.000 175.630 4.000 ;
    END
  END sstreams_i[223]
  PIN sstreams_i[224]
    DIRECTION INPUT ;
    USE SIGNAL ;
    ANTENNAGATEAREA 0.213000 ;
    PORT
      LAYER met2 ;
        RECT 177.650 0.000 177.930 4.000 ;
    END
  END sstreams_i[224]
  PIN sstreams_i[225]
    DIRECTION INPUT ;
    USE SIGNAL ;
    ANTENNAGATEAREA 0.213000 ;
    PORT
      LAYER met2 ;
        RECT 179.950 0.000 180.230 4.000 ;
    END
  END sstreams_i[225]
  PIN sstreams_i[226]
    DIRECTION INPUT ;
    USE SIGNAL ;
    ANTENNAGATEAREA 0.213000 ;
    PORT
      LAYER met2 ;
        RECT 182.250 0.000 182.530 4.000 ;
    END
  END sstreams_i[226]
  PIN sstreams_i[227]
    DIRECTION INPUT ;
    USE SIGNAL ;
    ANTENNAGATEAREA 0.213000 ;
    PORT
      LAYER met2 ;
        RECT 184.550 0.000 184.830 4.000 ;
    END
  END sstreams_i[227]
  PIN sstreams_i[228]
    DIRECTION INPUT ;
    USE SIGNAL ;
    ANTENNAGATEAREA 0.213000 ;
    PORT
      LAYER met2 ;
        RECT 186.850 0.000 187.130 4.000 ;
    END
  END sstreams_i[228]
  PIN sstreams_i[229]
    DIRECTION INPUT ;
    USE SIGNAL ;
    ANTENNAGATEAREA 0.213000 ;
    PORT
      LAYER met2 ;
        RECT 189.150 0.000 189.430 4.000 ;
    END
  END sstreams_i[229]
  PIN sstreams_i[22]
    DIRECTION INPUT ;
    USE SIGNAL ;
    ANTENNAGATEAREA 0.196500 ;
    PORT
      LAYER met2 ;
        RECT 853.850 0.000 854.130 4.000 ;
    END
  END sstreams_i[22]
  PIN sstreams_i[230]
    DIRECTION INPUT ;
    USE SIGNAL ;
    ANTENNAGATEAREA 0.213000 ;
    PORT
      LAYER met2 ;
        RECT 191.450 0.000 191.730 4.000 ;
    END
  END sstreams_i[230]
  PIN sstreams_i[231]
    DIRECTION INPUT ;
    USE SIGNAL ;
    ANTENNAGATEAREA 0.213000 ;
    PORT
      LAYER met2 ;
        RECT 193.750 0.000 194.030 4.000 ;
    END
  END sstreams_i[231]
  PIN sstreams_i[232]
    DIRECTION INPUT ;
    USE SIGNAL ;
    ANTENNAGATEAREA 0.213000 ;
    PORT
      LAYER met2 ;
        RECT 196.050 0.000 196.330 4.000 ;
    END
  END sstreams_i[232]
  PIN sstreams_i[233]
    DIRECTION INPUT ;
    USE SIGNAL ;
    ANTENNAGATEAREA 0.213000 ;
    PORT
      LAYER met2 ;
        RECT 198.350 0.000 198.630 4.000 ;
    END
  END sstreams_i[233]
  PIN sstreams_i[234]
    DIRECTION INPUT ;
    USE SIGNAL ;
    ANTENNAGATEAREA 0.213000 ;
    PORT
      LAYER met2 ;
        RECT 200.650 0.000 200.930 4.000 ;
    END
  END sstreams_i[234]
  PIN sstreams_i[235]
    DIRECTION INPUT ;
    USE SIGNAL ;
    ANTENNAGATEAREA 0.213000 ;
    PORT
      LAYER met2 ;
        RECT 202.950 0.000 203.230 4.000 ;
    END
  END sstreams_i[235]
  PIN sstreams_i[236]
    DIRECTION INPUT ;
    USE SIGNAL ;
    ANTENNAGATEAREA 0.159000 ;
    PORT
      LAYER met2 ;
        RECT 205.250 0.000 205.530 4.000 ;
    END
  END sstreams_i[236]
  PIN sstreams_i[237]
    DIRECTION INPUT ;
    USE SIGNAL ;
    ANTENNAGATEAREA 0.159000 ;
    PORT
      LAYER met2 ;
        RECT 207.550 0.000 207.830 4.000 ;
    END
  END sstreams_i[237]
  PIN sstreams_i[238]
    DIRECTION INPUT ;
    USE SIGNAL ;
    ANTENNAGATEAREA 0.159000 ;
    PORT
      LAYER met2 ;
        RECT 209.850 0.000 210.130 4.000 ;
    END
  END sstreams_i[238]
  PIN sstreams_i[239]
    DIRECTION INPUT ;
    USE SIGNAL ;
    ANTENNAGATEAREA 0.213000 ;
    PORT
      LAYER met2 ;
        RECT 212.150 0.000 212.430 4.000 ;
    END
  END sstreams_i[239]
  PIN sstreams_i[23]
    DIRECTION INPUT ;
    USE SIGNAL ;
    ANTENNAGATEAREA 0.196500 ;
    PORT
      LAYER met2 ;
        RECT 856.150 0.000 856.430 4.000 ;
    END
  END sstreams_i[23]
  PIN sstreams_i[240]
    DIRECTION INPUT ;
    USE SIGNAL ;
    ANTENNAGATEAREA 0.159000 ;
    PORT
      LAYER met2 ;
        RECT 214.450 0.000 214.730 4.000 ;
    END
  END sstreams_i[240]
  PIN sstreams_i[241]
    DIRECTION INPUT ;
    USE SIGNAL ;
    ANTENNAGATEAREA 0.213000 ;
    PORT
      LAYER met2 ;
        RECT 216.750 0.000 217.030 4.000 ;
    END
  END sstreams_i[241]
  PIN sstreams_i[242]
    DIRECTION INPUT ;
    USE SIGNAL ;
    ANTENNAGATEAREA 0.159000 ;
    PORT
      LAYER met2 ;
        RECT 219.050 0.000 219.330 4.000 ;
    END
  END sstreams_i[242]
  PIN sstreams_i[243]
    DIRECTION INPUT ;
    USE SIGNAL ;
    ANTENNAGATEAREA 0.159000 ;
    PORT
      LAYER met2 ;
        RECT 221.350 0.000 221.630 4.000 ;
    END
  END sstreams_i[243]
  PIN sstreams_i[244]
    DIRECTION INPUT ;
    USE SIGNAL ;
    ANTENNAGATEAREA 0.247500 ;
    PORT
      LAYER met2 ;
        RECT 223.650 0.000 223.930 4.000 ;
    END
  END sstreams_i[244]
  PIN sstreams_i[245]
    DIRECTION INPUT ;
    USE SIGNAL ;
    ANTENNAGATEAREA 0.247500 ;
    PORT
      LAYER met2 ;
        RECT 225.950 0.000 226.230 4.000 ;
    END
  END sstreams_i[245]
  PIN sstreams_i[246]
    DIRECTION INPUT ;
    USE SIGNAL ;
    ANTENNAGATEAREA 0.247500 ;
    PORT
      LAYER met2 ;
        RECT 228.250 0.000 228.530 4.000 ;
    END
  END sstreams_i[246]
  PIN sstreams_i[247]
    DIRECTION INPUT ;
    USE SIGNAL ;
    ANTENNAGATEAREA 0.247500 ;
    PORT
      LAYER met2 ;
        RECT 230.550 0.000 230.830 4.000 ;
    END
  END sstreams_i[247]
  PIN sstreams_i[248]
    DIRECTION INPUT ;
    USE SIGNAL ;
    ANTENNAGATEAREA 0.247500 ;
    PORT
      LAYER met2 ;
        RECT 232.850 0.000 233.130 4.000 ;
    END
  END sstreams_i[248]
  PIN sstreams_i[249]
    DIRECTION INPUT ;
    USE SIGNAL ;
    ANTENNAGATEAREA 0.247500 ;
    PORT
      LAYER met2 ;
        RECT 235.150 0.000 235.430 4.000 ;
    END
  END sstreams_i[249]
  PIN sstreams_i[24]
    DIRECTION INPUT ;
    USE SIGNAL ;
    ANTENNAGATEAREA 0.196500 ;
    PORT
      LAYER met2 ;
        RECT 858.450 0.000 858.730 4.000 ;
    END
  END sstreams_i[24]
  PIN sstreams_i[250]
    DIRECTION INPUT ;
    USE SIGNAL ;
    ANTENNAGATEAREA 0.247500 ;
    PORT
      LAYER met2 ;
        RECT 237.450 0.000 237.730 4.000 ;
    END
  END sstreams_i[250]
  PIN sstreams_i[251]
    DIRECTION INPUT ;
    USE SIGNAL ;
    ANTENNAGATEAREA 0.247500 ;
    PORT
      LAYER met2 ;
        RECT 239.750 0.000 240.030 4.000 ;
    END
  END sstreams_i[251]
  PIN sstreams_i[252]
    DIRECTION INPUT ;
    USE SIGNAL ;
    ANTENNAGATEAREA 0.213000 ;
    PORT
      LAYER met2 ;
        RECT 242.050 0.000 242.330 4.000 ;
    END
  END sstreams_i[252]
  PIN sstreams_i[253]
    DIRECTION INPUT ;
    USE SIGNAL ;
    ANTENNAGATEAREA 0.213000 ;
    PORT
      LAYER met2 ;
        RECT 244.350 0.000 244.630 4.000 ;
    END
  END sstreams_i[253]
  PIN sstreams_i[254]
    DIRECTION INPUT ;
    USE SIGNAL ;
    ANTENNAGATEAREA 0.213000 ;
    PORT
      LAYER met2 ;
        RECT 246.650 0.000 246.930 4.000 ;
    END
  END sstreams_i[254]
  PIN sstreams_i[255]
    DIRECTION INPUT ;
    USE SIGNAL ;
    ANTENNAGATEAREA 0.213000 ;
    PORT
      LAYER met2 ;
        RECT 248.950 0.000 249.230 4.000 ;
    END
  END sstreams_i[255]
  PIN sstreams_i[256]
    DIRECTION INPUT ;
    USE SIGNAL ;
    ANTENNAGATEAREA 0.213000 ;
    PORT
      LAYER met2 ;
        RECT 251.250 0.000 251.530 4.000 ;
    END
  END sstreams_i[256]
  PIN sstreams_i[257]
    DIRECTION INPUT ;
    USE SIGNAL ;
    ANTENNAGATEAREA 0.213000 ;
    PORT
      LAYER met2 ;
        RECT 253.550 0.000 253.830 4.000 ;
    END
  END sstreams_i[257]
  PIN sstreams_i[258]
    DIRECTION INPUT ;
    USE SIGNAL ;
    ANTENNAGATEAREA 0.213000 ;
    PORT
      LAYER met2 ;
        RECT 255.850 0.000 256.130 4.000 ;
    END
  END sstreams_i[258]
  PIN sstreams_i[259]
    DIRECTION INPUT ;
    USE SIGNAL ;
    ANTENNAGATEAREA 0.213000 ;
    PORT
      LAYER met2 ;
        RECT 258.150 0.000 258.430 4.000 ;
    END
  END sstreams_i[259]
  PIN sstreams_i[25]
    DIRECTION INPUT ;
    USE SIGNAL ;
    ANTENNAGATEAREA 0.196500 ;
    PORT
      LAYER met2 ;
        RECT 860.750 0.000 861.030 4.000 ;
    END
  END sstreams_i[25]
  PIN sstreams_i[260]
    DIRECTION INPUT ;
    USE SIGNAL ;
    ANTENNAGATEAREA 0.213000 ;
    PORT
      LAYER met2 ;
        RECT 260.450 0.000 260.730 4.000 ;
    END
  END sstreams_i[260]
  PIN sstreams_i[261]
    DIRECTION INPUT ;
    USE SIGNAL ;
    ANTENNAGATEAREA 0.159000 ;
    PORT
      LAYER met2 ;
        RECT 262.750 0.000 263.030 4.000 ;
    END
  END sstreams_i[261]
  PIN sstreams_i[262]
    DIRECTION INPUT ;
    USE SIGNAL ;
    ANTENNAGATEAREA 0.159000 ;
    PORT
      LAYER met2 ;
        RECT 265.050 0.000 265.330 4.000 ;
    END
  END sstreams_i[262]
  PIN sstreams_i[263]
    DIRECTION INPUT ;
    USE SIGNAL ;
    ANTENNAGATEAREA 0.159000 ;
    PORT
      LAYER met2 ;
        RECT 267.350 0.000 267.630 4.000 ;
    END
  END sstreams_i[263]
  PIN sstreams_i[264]
    DIRECTION INPUT ;
    USE SIGNAL ;
    ANTENNAGATEAREA 0.159000 ;
    PORT
      LAYER met2 ;
        RECT 269.650 0.000 269.930 4.000 ;
    END
  END sstreams_i[264]
  PIN sstreams_i[265]
    DIRECTION INPUT ;
    USE SIGNAL ;
    ANTENNAGATEAREA 0.213000 ;
    PORT
      LAYER met2 ;
        RECT 271.950 0.000 272.230 4.000 ;
    END
  END sstreams_i[265]
  PIN sstreams_i[266]
    DIRECTION INPUT ;
    USE SIGNAL ;
    ANTENNAGATEAREA 0.159000 ;
    PORT
      LAYER met2 ;
        RECT 274.250 0.000 274.530 4.000 ;
    END
  END sstreams_i[266]
  PIN sstreams_i[267]
    DIRECTION INPUT ;
    USE SIGNAL ;
    ANTENNAGATEAREA 0.159000 ;
    PORT
      LAYER met2 ;
        RECT 276.550 0.000 276.830 4.000 ;
    END
  END sstreams_i[267]
  PIN sstreams_i[268]
    DIRECTION INPUT ;
    USE SIGNAL ;
    ANTENNAGATEAREA 0.213000 ;
    PORT
      LAYER met2 ;
        RECT 278.850 0.000 279.130 4.000 ;
    END
  END sstreams_i[268]
  PIN sstreams_i[269]
    DIRECTION INPUT ;
    USE SIGNAL ;
    ANTENNAGATEAREA 0.213000 ;
    PORT
      LAYER met2 ;
        RECT 281.150 0.000 281.430 4.000 ;
    END
  END sstreams_i[269]
  PIN sstreams_i[26]
    DIRECTION INPUT ;
    USE SIGNAL ;
    ANTENNAGATEAREA 0.196500 ;
    PORT
      LAYER met2 ;
        RECT 863.050 0.000 863.330 4.000 ;
    END
  END sstreams_i[26]
  PIN sstreams_i[270]
    DIRECTION INPUT ;
    USE SIGNAL ;
    ANTENNAGATEAREA 0.213000 ;
    PORT
      LAYER met2 ;
        RECT 283.450 0.000 283.730 4.000 ;
    END
  END sstreams_i[270]
  PIN sstreams_i[271]
    DIRECTION INPUT ;
    USE SIGNAL ;
    ANTENNAGATEAREA 0.213000 ;
    PORT
      LAYER met2 ;
        RECT 285.750 0.000 286.030 4.000 ;
    END
  END sstreams_i[271]
  PIN sstreams_i[272]
    DIRECTION INPUT ;
    USE SIGNAL ;
    ANTENNAGATEAREA 0.213000 ;
    PORT
      LAYER met2 ;
        RECT 288.050 0.000 288.330 4.000 ;
    END
  END sstreams_i[272]
  PIN sstreams_i[273]
    DIRECTION INPUT ;
    USE SIGNAL ;
    ANTENNAGATEAREA 0.213000 ;
    PORT
      LAYER met2 ;
        RECT 290.350 0.000 290.630 4.000 ;
    END
  END sstreams_i[273]
  PIN sstreams_i[274]
    DIRECTION INPUT ;
    USE SIGNAL ;
    ANTENNAGATEAREA 0.213000 ;
    PORT
      LAYER met2 ;
        RECT 292.650 0.000 292.930 4.000 ;
    END
  END sstreams_i[274]
  PIN sstreams_i[275]
    DIRECTION INPUT ;
    USE SIGNAL ;
    ANTENNAGATEAREA 0.213000 ;
    PORT
      LAYER met2 ;
        RECT 294.950 0.000 295.230 4.000 ;
    END
  END sstreams_i[275]
  PIN sstreams_i[276]
    DIRECTION INPUT ;
    USE SIGNAL ;
    ANTENNAGATEAREA 0.213000 ;
    PORT
      LAYER met2 ;
        RECT 297.250 0.000 297.530 4.000 ;
    END
  END sstreams_i[276]
  PIN sstreams_i[277]
    DIRECTION INPUT ;
    USE SIGNAL ;
    ANTENNAGATEAREA 0.213000 ;
    PORT
      LAYER met2 ;
        RECT 299.550 0.000 299.830 4.000 ;
    END
  END sstreams_i[277]
  PIN sstreams_i[278]
    DIRECTION INPUT ;
    USE SIGNAL ;
    ANTENNAGATEAREA 0.213000 ;
    PORT
      LAYER met2 ;
        RECT 301.850 0.000 302.130 4.000 ;
    END
  END sstreams_i[278]
  PIN sstreams_i[279]
    DIRECTION INPUT ;
    USE SIGNAL ;
    ANTENNAGATEAREA 0.213000 ;
    PORT
      LAYER met2 ;
        RECT 304.150 0.000 304.430 4.000 ;
    END
  END sstreams_i[279]
  PIN sstreams_i[27]
    DIRECTION INPUT ;
    USE SIGNAL ;
    ANTENNAGATEAREA 0.196500 ;
    PORT
      LAYER met2 ;
        RECT 865.350 0.000 865.630 4.000 ;
    END
  END sstreams_i[27]
  PIN sstreams_i[280]
    DIRECTION INPUT ;
    USE SIGNAL ;
    ANTENNAGATEAREA 0.213000 ;
    PORT
      LAYER met2 ;
        RECT 306.450 0.000 306.730 4.000 ;
    END
  END sstreams_i[280]
  PIN sstreams_i[281]
    DIRECTION INPUT ;
    USE SIGNAL ;
    ANTENNAGATEAREA 0.213000 ;
    PORT
      LAYER met2 ;
        RECT 308.750 0.000 309.030 4.000 ;
    END
  END sstreams_i[281]
  PIN sstreams_i[282]
    DIRECTION INPUT ;
    USE SIGNAL ;
    ANTENNAGATEAREA 0.213000 ;
    PORT
      LAYER met2 ;
        RECT 311.050 0.000 311.330 4.000 ;
    END
  END sstreams_i[282]
  PIN sstreams_i[283]
    DIRECTION INPUT ;
    USE SIGNAL ;
    ANTENNAGATEAREA 0.213000 ;
    PORT
      LAYER met2 ;
        RECT 313.350 0.000 313.630 4.000 ;
    END
  END sstreams_i[283]
  PIN sstreams_i[284]
    DIRECTION INPUT ;
    USE SIGNAL ;
    ANTENNAGATEAREA 0.126000 ;
    PORT
      LAYER met2 ;
        RECT 315.650 0.000 315.930 4.000 ;
    END
  END sstreams_i[284]
  PIN sstreams_i[285]
    DIRECTION INPUT ;
    USE SIGNAL ;
    ANTENNAGATEAREA 0.213000 ;
    PORT
      LAYER met2 ;
        RECT 317.950 0.000 318.230 4.000 ;
    END
  END sstreams_i[285]
  PIN sstreams_i[286]
    DIRECTION INPUT ;
    USE SIGNAL ;
    ANTENNAGATEAREA 0.159000 ;
    PORT
      LAYER met2 ;
        RECT 320.250 0.000 320.530 4.000 ;
    END
  END sstreams_i[286]
  PIN sstreams_i[287]
    DIRECTION INPUT ;
    USE SIGNAL ;
    ANTENNAGATEAREA 0.159000 ;
    PORT
      LAYER met2 ;
        RECT 322.550 0.000 322.830 4.000 ;
    END
  END sstreams_i[287]
  PIN sstreams_i[288]
    DIRECTION INPUT ;
    USE SIGNAL ;
    ANTENNAGATEAREA 0.159000 ;
    PORT
      LAYER met2 ;
        RECT 324.850 0.000 325.130 4.000 ;
    END
  END sstreams_i[288]
  PIN sstreams_i[289]
    DIRECTION INPUT ;
    USE SIGNAL ;
    ANTENNAGATEAREA 0.213000 ;
    PORT
      LAYER met2 ;
        RECT 327.150 0.000 327.430 4.000 ;
    END
  END sstreams_i[289]
  PIN sstreams_i[28]
    DIRECTION INPUT ;
    USE SIGNAL ;
    ANTENNAGATEAREA 0.196500 ;
    PORT
      LAYER met2 ;
        RECT 867.650 0.000 867.930 4.000 ;
    END
  END sstreams_i[28]
  PIN sstreams_i[290]
    DIRECTION INPUT ;
    USE SIGNAL ;
    ANTENNAGATEAREA 0.213000 ;
    PORT
      LAYER met2 ;
        RECT 329.450 0.000 329.730 4.000 ;
    END
  END sstreams_i[290]
  PIN sstreams_i[291]
    DIRECTION INPUT ;
    USE SIGNAL ;
    ANTENNAGATEAREA 0.213000 ;
    PORT
      LAYER met2 ;
        RECT 331.750 0.000 332.030 4.000 ;
    END
  END sstreams_i[291]
  PIN sstreams_i[292]
    DIRECTION INPUT ;
    USE SIGNAL ;
    ANTENNAGATEAREA 0.213000 ;
    PORT
      LAYER met2 ;
        RECT 334.050 0.000 334.330 4.000 ;
    END
  END sstreams_i[292]
  PIN sstreams_i[293]
    DIRECTION INPUT ;
    USE SIGNAL ;
    ANTENNAGATEAREA 0.159000 ;
    PORT
      LAYER met2 ;
        RECT 336.350 0.000 336.630 4.000 ;
    END
  END sstreams_i[293]
  PIN sstreams_i[294]
    DIRECTION INPUT ;
    USE SIGNAL ;
    ANTENNAGATEAREA 0.196500 ;
    PORT
      LAYER met2 ;
        RECT 338.650 0.000 338.930 4.000 ;
    END
  END sstreams_i[294]
  PIN sstreams_i[295]
    DIRECTION INPUT ;
    USE SIGNAL ;
    ANTENNAGATEAREA 0.196500 ;
    PORT
      LAYER met2 ;
        RECT 340.950 0.000 341.230 4.000 ;
    END
  END sstreams_i[295]
  PIN sstreams_i[296]
    DIRECTION INPUT ;
    USE SIGNAL ;
    ANTENNAGATEAREA 0.196500 ;
    PORT
      LAYER met2 ;
        RECT 343.250 0.000 343.530 4.000 ;
    END
  END sstreams_i[296]
  PIN sstreams_i[297]
    DIRECTION INPUT ;
    USE SIGNAL ;
    ANTENNAGATEAREA 0.196500 ;
    PORT
      LAYER met2 ;
        RECT 345.550 0.000 345.830 4.000 ;
    END
  END sstreams_i[297]
  PIN sstreams_i[298]
    DIRECTION INPUT ;
    USE SIGNAL ;
    ANTENNAGATEAREA 0.196500 ;
    PORT
      LAYER met2 ;
        RECT 347.850 0.000 348.130 4.000 ;
    END
  END sstreams_i[298]
  PIN sstreams_i[299]
    DIRECTION INPUT ;
    USE SIGNAL ;
    ANTENNAGATEAREA 0.196500 ;
    PORT
      LAYER met2 ;
        RECT 350.150 0.000 350.430 4.000 ;
    END
  END sstreams_i[299]
  PIN sstreams_i[29]
    DIRECTION INPUT ;
    USE SIGNAL ;
    ANTENNAGATEAREA 0.196500 ;
    PORT
      LAYER met2 ;
        RECT 869.950 0.000 870.230 4.000 ;
    END
  END sstreams_i[29]
  PIN sstreams_i[2]
    DIRECTION INPUT ;
    USE SIGNAL ;
    ANTENNAGATEAREA 0.196500 ;
    PORT
      LAYER met2 ;
        RECT 807.850 0.000 808.130 4.000 ;
    END
  END sstreams_i[2]
  PIN sstreams_i[300]
    DIRECTION INPUT ;
    USE SIGNAL ;
    ANTENNAGATEAREA 0.196500 ;
    PORT
      LAYER met2 ;
        RECT 352.450 0.000 352.730 4.000 ;
    END
  END sstreams_i[300]
  PIN sstreams_i[301]
    DIRECTION INPUT ;
    USE SIGNAL ;
    ANTENNAGATEAREA 0.196500 ;
    PORT
      LAYER met2 ;
        RECT 354.750 0.000 355.030 4.000 ;
    END
  END sstreams_i[301]
  PIN sstreams_i[302]
    DIRECTION INPUT ;
    USE SIGNAL ;
    ANTENNAGATEAREA 0.196500 ;
    PORT
      LAYER met2 ;
        RECT 357.050 0.000 357.330 4.000 ;
    END
  END sstreams_i[302]
  PIN sstreams_i[303]
    DIRECTION INPUT ;
    USE SIGNAL ;
    ANTENNAGATEAREA 0.196500 ;
    PORT
      LAYER met2 ;
        RECT 359.350 0.000 359.630 4.000 ;
    END
  END sstreams_i[303]
  PIN sstreams_i[304]
    DIRECTION INPUT ;
    USE SIGNAL ;
    ANTENNAGATEAREA 0.196500 ;
    PORT
      LAYER met2 ;
        RECT 361.650 0.000 361.930 4.000 ;
    END
  END sstreams_i[304]
  PIN sstreams_i[305]
    DIRECTION INPUT ;
    USE SIGNAL ;
    ANTENNAGATEAREA 0.196500 ;
    PORT
      LAYER met2 ;
        RECT 363.950 0.000 364.230 4.000 ;
    END
  END sstreams_i[305]
  PIN sstreams_i[306]
    DIRECTION INPUT ;
    USE SIGNAL ;
    ANTENNAGATEAREA 0.196500 ;
    PORT
      LAYER met2 ;
        RECT 366.250 0.000 366.530 4.000 ;
    END
  END sstreams_i[306]
  PIN sstreams_i[307]
    DIRECTION INPUT ;
    USE SIGNAL ;
    ANTENNAGATEAREA 0.196500 ;
    PORT
      LAYER met2 ;
        RECT 368.550 0.000 368.830 4.000 ;
    END
  END sstreams_i[307]
  PIN sstreams_i[308]
    DIRECTION INPUT ;
    USE SIGNAL ;
    ANTENNAGATEAREA 0.196500 ;
    PORT
      LAYER met2 ;
        RECT 370.850 0.000 371.130 4.000 ;
    END
  END sstreams_i[308]
  PIN sstreams_i[309]
    DIRECTION INPUT ;
    USE SIGNAL ;
    ANTENNAGATEAREA 0.196500 ;
    PORT
      LAYER met2 ;
        RECT 373.150 0.000 373.430 4.000 ;
    END
  END sstreams_i[309]
  PIN sstreams_i[30]
    DIRECTION INPUT ;
    USE SIGNAL ;
    ANTENNAGATEAREA 0.196500 ;
    PORT
      LAYER met2 ;
        RECT 872.250 0.000 872.530 4.000 ;
    END
  END sstreams_i[30]
  PIN sstreams_i[310]
    DIRECTION INPUT ;
    USE SIGNAL ;
    ANTENNAGATEAREA 0.196500 ;
    PORT
      LAYER met2 ;
        RECT 375.450 0.000 375.730 4.000 ;
    END
  END sstreams_i[310]
  PIN sstreams_i[311]
    DIRECTION INPUT ;
    USE SIGNAL ;
    ANTENNAGATEAREA 0.196500 ;
    PORT
      LAYER met2 ;
        RECT 377.750 0.000 378.030 4.000 ;
    END
  END sstreams_i[311]
  PIN sstreams_i[312]
    DIRECTION INPUT ;
    USE SIGNAL ;
    ANTENNAGATEAREA 0.196500 ;
    PORT
      LAYER met2 ;
        RECT 380.050 0.000 380.330 4.000 ;
    END
  END sstreams_i[312]
  PIN sstreams_i[313]
    DIRECTION INPUT ;
    USE SIGNAL ;
    ANTENNAGATEAREA 0.196500 ;
    PORT
      LAYER met2 ;
        RECT 382.350 0.000 382.630 4.000 ;
    END
  END sstreams_i[313]
  PIN sstreams_i[314]
    DIRECTION INPUT ;
    USE SIGNAL ;
    ANTENNAGATEAREA 0.196500 ;
    PORT
      LAYER met2 ;
        RECT 384.650 0.000 384.930 4.000 ;
    END
  END sstreams_i[314]
  PIN sstreams_i[315]
    DIRECTION INPUT ;
    USE SIGNAL ;
    ANTENNAGATEAREA 0.196500 ;
    PORT
      LAYER met2 ;
        RECT 386.950 0.000 387.230 4.000 ;
    END
  END sstreams_i[315]
  PIN sstreams_i[316]
    DIRECTION INPUT ;
    USE SIGNAL ;
    ANTENNAGATEAREA 0.196500 ;
    PORT
      LAYER met2 ;
        RECT 389.250 0.000 389.530 4.000 ;
    END
  END sstreams_i[316]
  PIN sstreams_i[317]
    DIRECTION INPUT ;
    USE SIGNAL ;
    ANTENNAGATEAREA 0.196500 ;
    PORT
      LAYER met2 ;
        RECT 391.550 0.000 391.830 4.000 ;
    END
  END sstreams_i[317]
  PIN sstreams_i[318]
    DIRECTION INPUT ;
    USE SIGNAL ;
    ANTENNAGATEAREA 0.196500 ;
    PORT
      LAYER met2 ;
        RECT 393.850 0.000 394.130 4.000 ;
    END
  END sstreams_i[318]
  PIN sstreams_i[319]
    DIRECTION INPUT ;
    USE SIGNAL ;
    ANTENNAGATEAREA 0.196500 ;
    PORT
      LAYER met2 ;
        RECT 396.150 0.000 396.430 4.000 ;
    END
  END sstreams_i[319]
  PIN sstreams_i[31]
    DIRECTION INPUT ;
    USE SIGNAL ;
    ANTENNAGATEAREA 0.196500 ;
    PORT
      LAYER met2 ;
        RECT 874.550 0.000 874.830 4.000 ;
    END
  END sstreams_i[31]
  PIN sstreams_i[320]
    DIRECTION INPUT ;
    USE SIGNAL ;
    ANTENNAGATEAREA 0.196500 ;
    PORT
      LAYER met2 ;
        RECT 398.450 0.000 398.730 4.000 ;
    END
  END sstreams_i[320]
  PIN sstreams_i[321]
    DIRECTION INPUT ;
    USE SIGNAL ;
    ANTENNAGATEAREA 0.196500 ;
    PORT
      LAYER met2 ;
        RECT 400.750 0.000 401.030 4.000 ;
    END
  END sstreams_i[321]
  PIN sstreams_i[322]
    DIRECTION INPUT ;
    USE SIGNAL ;
    ANTENNAGATEAREA 0.196500 ;
    PORT
      LAYER met2 ;
        RECT 403.050 0.000 403.330 4.000 ;
    END
  END sstreams_i[322]
  PIN sstreams_i[323]
    DIRECTION INPUT ;
    USE SIGNAL ;
    ANTENNAGATEAREA 0.196500 ;
    PORT
      LAYER met2 ;
        RECT 405.350 0.000 405.630 4.000 ;
    END
  END sstreams_i[323]
  PIN sstreams_i[324]
    DIRECTION INPUT ;
    USE SIGNAL ;
    ANTENNAGATEAREA 0.196500 ;
    PORT
      LAYER met2 ;
        RECT 407.650 0.000 407.930 4.000 ;
    END
  END sstreams_i[324]
  PIN sstreams_i[325]
    DIRECTION INPUT ;
    USE SIGNAL ;
    ANTENNAGATEAREA 0.196500 ;
    PORT
      LAYER met2 ;
        RECT 409.950 0.000 410.230 4.000 ;
    END
  END sstreams_i[325]
  PIN sstreams_i[326]
    DIRECTION INPUT ;
    USE SIGNAL ;
    ANTENNAGATEAREA 0.196500 ;
    PORT
      LAYER met2 ;
        RECT 412.250 0.000 412.530 4.000 ;
    END
  END sstreams_i[326]
  PIN sstreams_i[327]
    DIRECTION INPUT ;
    USE SIGNAL ;
    ANTENNAGATEAREA 0.196500 ;
    PORT
      LAYER met2 ;
        RECT 414.550 0.000 414.830 4.000 ;
    END
  END sstreams_i[327]
  PIN sstreams_i[328]
    DIRECTION INPUT ;
    USE SIGNAL ;
    ANTENNAGATEAREA 0.196500 ;
    PORT
      LAYER met2 ;
        RECT 416.850 0.000 417.130 4.000 ;
    END
  END sstreams_i[328]
  PIN sstreams_i[329]
    DIRECTION INPUT ;
    USE SIGNAL ;
    ANTENNAGATEAREA 0.196500 ;
    PORT
      LAYER met2 ;
        RECT 419.150 0.000 419.430 4.000 ;
    END
  END sstreams_i[329]
  PIN sstreams_i[32]
    DIRECTION INPUT ;
    USE SIGNAL ;
    ANTENNAGATEAREA 0.196500 ;
    PORT
      LAYER met2 ;
        RECT 876.850 0.000 877.130 4.000 ;
    END
  END sstreams_i[32]
  PIN sstreams_i[330]
    DIRECTION INPUT ;
    USE SIGNAL ;
    ANTENNAGATEAREA 0.196500 ;
    PORT
      LAYER met2 ;
        RECT 421.450 0.000 421.730 4.000 ;
    END
  END sstreams_i[330]
  PIN sstreams_i[331]
    DIRECTION INPUT ;
    USE SIGNAL ;
    ANTENNAGATEAREA 0.196500 ;
    PORT
      LAYER met2 ;
        RECT 423.750 0.000 424.030 4.000 ;
    END
  END sstreams_i[331]
  PIN sstreams_i[332]
    DIRECTION INPUT ;
    USE SIGNAL ;
    ANTENNAGATEAREA 0.196500 ;
    PORT
      LAYER met2 ;
        RECT 426.050 0.000 426.330 4.000 ;
    END
  END sstreams_i[332]
  PIN sstreams_i[333]
    DIRECTION INPUT ;
    USE SIGNAL ;
    ANTENNAGATEAREA 0.196500 ;
    PORT
      LAYER met2 ;
        RECT 428.350 0.000 428.630 4.000 ;
    END
  END sstreams_i[333]
  PIN sstreams_i[334]
    DIRECTION INPUT ;
    USE SIGNAL ;
    ANTENNAGATEAREA 0.196500 ;
    PORT
      LAYER met2 ;
        RECT 430.650 0.000 430.930 4.000 ;
    END
  END sstreams_i[334]
  PIN sstreams_i[335]
    DIRECTION INPUT ;
    USE SIGNAL ;
    ANTENNAGATEAREA 0.196500 ;
    PORT
      LAYER met2 ;
        RECT 432.950 0.000 433.230 4.000 ;
    END
  END sstreams_i[335]
  PIN sstreams_i[336]
    DIRECTION INPUT ;
    USE SIGNAL ;
    ANTENNAGATEAREA 0.196500 ;
    PORT
      LAYER met2 ;
        RECT 435.250 0.000 435.530 4.000 ;
    END
  END sstreams_i[336]
  PIN sstreams_i[337]
    DIRECTION INPUT ;
    USE SIGNAL ;
    ANTENNAGATEAREA 0.196500 ;
    PORT
      LAYER met2 ;
        RECT 437.550 0.000 437.830 4.000 ;
    END
  END sstreams_i[337]
  PIN sstreams_i[338]
    DIRECTION INPUT ;
    USE SIGNAL ;
    ANTENNAGATEAREA 0.196500 ;
    PORT
      LAYER met2 ;
        RECT 439.850 0.000 440.130 4.000 ;
    END
  END sstreams_i[338]
  PIN sstreams_i[339]
    DIRECTION INPUT ;
    USE SIGNAL ;
    ANTENNAGATEAREA 0.196500 ;
    PORT
      LAYER met2 ;
        RECT 442.150 0.000 442.430 4.000 ;
    END
  END sstreams_i[339]
  PIN sstreams_i[33]
    DIRECTION INPUT ;
    USE SIGNAL ;
    ANTENNAGATEAREA 0.196500 ;
    PORT
      LAYER met2 ;
        RECT 879.150 0.000 879.430 4.000 ;
    END
  END sstreams_i[33]
  PIN sstreams_i[340]
    DIRECTION INPUT ;
    USE SIGNAL ;
    ANTENNAGATEAREA 0.196500 ;
    PORT
      LAYER met2 ;
        RECT 444.450 0.000 444.730 4.000 ;
    END
  END sstreams_i[340]
  PIN sstreams_i[341]
    DIRECTION INPUT ;
    USE SIGNAL ;
    ANTENNAGATEAREA 0.196500 ;
    PORT
      LAYER met2 ;
        RECT 446.750 0.000 447.030 4.000 ;
    END
  END sstreams_i[341]
  PIN sstreams_i[342]
    DIRECTION INPUT ;
    USE SIGNAL ;
    ANTENNAGATEAREA 0.159000 ;
    PORT
      LAYER met2 ;
        RECT 449.050 0.000 449.330 4.000 ;
    END
  END sstreams_i[342]
  PIN sstreams_i[343]
    DIRECTION INPUT ;
    USE SIGNAL ;
    ANTENNAGATEAREA 0.159000 ;
    PORT
      LAYER met2 ;
        RECT 451.350 0.000 451.630 4.000 ;
    END
  END sstreams_i[343]
  PIN sstreams_i[344]
    DIRECTION INPUT ;
    USE SIGNAL ;
    ANTENNAGATEAREA 0.213000 ;
    PORT
      LAYER met2 ;
        RECT 453.650 0.000 453.930 4.000 ;
    END
  END sstreams_i[344]
  PIN sstreams_i[345]
    DIRECTION INPUT ;
    USE SIGNAL ;
    ANTENNAGATEAREA 0.213000 ;
    PORT
      LAYER met2 ;
        RECT 455.950 0.000 456.230 4.000 ;
    END
  END sstreams_i[345]
  PIN sstreams_i[346]
    DIRECTION INPUT ;
    USE SIGNAL ;
    ANTENNAGATEAREA 0.159000 ;
    PORT
      LAYER met2 ;
        RECT 458.250 0.000 458.530 4.000 ;
    END
  END sstreams_i[346]
  PIN sstreams_i[347]
    DIRECTION INPUT ;
    USE SIGNAL ;
    ANTENNAGATEAREA 0.159000 ;
    PORT
      LAYER met2 ;
        RECT 460.550 0.000 460.830 4.000 ;
    END
  END sstreams_i[347]
  PIN sstreams_i[348]
    DIRECTION INPUT ;
    USE SIGNAL ;
    ANTENNAGATEAREA 0.159000 ;
    PORT
      LAYER met2 ;
        RECT 462.850 0.000 463.130 4.000 ;
    END
  END sstreams_i[348]
  PIN sstreams_i[349]
    DIRECTION INPUT ;
    USE SIGNAL ;
    ANTENNAGATEAREA 0.159000 ;
    PORT
      LAYER met2 ;
        RECT 465.150 0.000 465.430 4.000 ;
    END
  END sstreams_i[349]
  PIN sstreams_i[34]
    DIRECTION INPUT ;
    USE SIGNAL ;
    ANTENNAGATEAREA 0.196500 ;
    PORT
      LAYER met2 ;
        RECT 881.450 0.000 881.730 4.000 ;
    END
  END sstreams_i[34]
  PIN sstreams_i[350]
    DIRECTION INPUT ;
    USE SIGNAL ;
    ANTENNAGATEAREA 0.159000 ;
    PORT
      LAYER met2 ;
        RECT 467.450 0.000 467.730 4.000 ;
    END
  END sstreams_i[350]
  PIN sstreams_i[351]
    DIRECTION INPUT ;
    USE SIGNAL ;
    ANTENNAGATEAREA 0.159000 ;
    PORT
      LAYER met2 ;
        RECT 469.750 0.000 470.030 4.000 ;
    END
  END sstreams_i[351]
  PIN sstreams_i[352]
    DIRECTION INPUT ;
    USE SIGNAL ;
    ANTENNAGATEAREA 0.213000 ;
    PORT
      LAYER met2 ;
        RECT 472.050 0.000 472.330 4.000 ;
    END
  END sstreams_i[352]
  PIN sstreams_i[353]
    DIRECTION INPUT ;
    USE SIGNAL ;
    ANTENNAGATEAREA 0.159000 ;
    PORT
      LAYER met2 ;
        RECT 474.350 0.000 474.630 4.000 ;
    END
  END sstreams_i[353]
  PIN sstreams_i[354]
    DIRECTION INPUT ;
    USE SIGNAL ;
    ANTENNAGATEAREA 0.213000 ;
    PORT
      LAYER met2 ;
        RECT 476.650 0.000 476.930 4.000 ;
    END
  END sstreams_i[354]
  PIN sstreams_i[355]
    DIRECTION INPUT ;
    USE SIGNAL ;
    ANTENNAGATEAREA 0.159000 ;
    PORT
      LAYER met2 ;
        RECT 478.950 0.000 479.230 4.000 ;
    END
  END sstreams_i[355]
  PIN sstreams_i[356]
    DIRECTION INPUT ;
    USE SIGNAL ;
    ANTENNAGATEAREA 0.213000 ;
    PORT
      LAYER met2 ;
        RECT 481.250 0.000 481.530 4.000 ;
    END
  END sstreams_i[356]
  PIN sstreams_i[357]
    DIRECTION INPUT ;
    USE SIGNAL ;
    ANTENNAGATEAREA 0.213000 ;
    PORT
      LAYER met2 ;
        RECT 483.550 0.000 483.830 4.000 ;
    END
  END sstreams_i[357]
  PIN sstreams_i[358]
    DIRECTION INPUT ;
    USE SIGNAL ;
    ANTENNAGATEAREA 0.126000 ;
    PORT
      LAYER met2 ;
        RECT 485.850 0.000 486.130 4.000 ;
    END
  END sstreams_i[358]
  PIN sstreams_i[359]
    DIRECTION INPUT ;
    USE SIGNAL ;
    ANTENNAGATEAREA 0.196500 ;
    PORT
      LAYER met2 ;
        RECT 488.150 0.000 488.430 4.000 ;
    END
  END sstreams_i[359]
  PIN sstreams_i[35]
    DIRECTION INPUT ;
    USE SIGNAL ;
    ANTENNAGATEAREA 0.196500 ;
    PORT
      LAYER met2 ;
        RECT 883.750 0.000 884.030 4.000 ;
    END
  END sstreams_i[35]
  PIN sstreams_i[360]
    DIRECTION INPUT ;
    USE SIGNAL ;
    ANTENNAGATEAREA 0.196500 ;
    PORT
      LAYER met2 ;
        RECT 490.450 0.000 490.730 4.000 ;
    END
  END sstreams_i[360]
  PIN sstreams_i[361]
    DIRECTION INPUT ;
    USE SIGNAL ;
    ANTENNAGATEAREA 0.196500 ;
    PORT
      LAYER met2 ;
        RECT 492.750 0.000 493.030 4.000 ;
    END
  END sstreams_i[361]
  PIN sstreams_i[362]
    DIRECTION INPUT ;
    USE SIGNAL ;
    ANTENNAGATEAREA 0.196500 ;
    PORT
      LAYER met2 ;
        RECT 495.050 0.000 495.330 4.000 ;
    END
  END sstreams_i[362]
  PIN sstreams_i[363]
    DIRECTION INPUT ;
    USE SIGNAL ;
    ANTENNAGATEAREA 0.196500 ;
    PORT
      LAYER met2 ;
        RECT 497.350 0.000 497.630 4.000 ;
    END
  END sstreams_i[363]
  PIN sstreams_i[364]
    DIRECTION INPUT ;
    USE SIGNAL ;
    ANTENNAGATEAREA 0.196500 ;
    PORT
      LAYER met2 ;
        RECT 499.650 0.000 499.930 4.000 ;
    END
  END sstreams_i[364]
  PIN sstreams_i[365]
    DIRECTION INPUT ;
    USE SIGNAL ;
    ANTENNAGATEAREA 0.196500 ;
    PORT
      LAYER met2 ;
        RECT 501.950 0.000 502.230 4.000 ;
    END
  END sstreams_i[365]
  PIN sstreams_i[366]
    DIRECTION INPUT ;
    USE SIGNAL ;
    ANTENNAGATEAREA 0.196500 ;
    PORT
      LAYER met2 ;
        RECT 504.250 0.000 504.530 4.000 ;
    END
  END sstreams_i[366]
  PIN sstreams_i[367]
    DIRECTION INPUT ;
    USE SIGNAL ;
    ANTENNAGATEAREA 0.196500 ;
    PORT
      LAYER met2 ;
        RECT 506.550 0.000 506.830 4.000 ;
    END
  END sstreams_i[367]
  PIN sstreams_i[368]
    DIRECTION INPUT ;
    USE SIGNAL ;
    ANTENNAGATEAREA 0.196500 ;
    PORT
      LAYER met2 ;
        RECT 508.850 0.000 509.130 4.000 ;
    END
  END sstreams_i[368]
  PIN sstreams_i[369]
    DIRECTION INPUT ;
    USE SIGNAL ;
    ANTENNAGATEAREA 0.196500 ;
    PORT
      LAYER met2 ;
        RECT 511.150 0.000 511.430 4.000 ;
    END
  END sstreams_i[369]
  PIN sstreams_i[36]
    DIRECTION INPUT ;
    USE SIGNAL ;
    ANTENNAGATEAREA 0.196500 ;
    PORT
      LAYER met2 ;
        RECT 886.050 0.000 886.330 4.000 ;
    END
  END sstreams_i[36]
  PIN sstreams_i[370]
    DIRECTION INPUT ;
    USE SIGNAL ;
    ANTENNAGATEAREA 0.196500 ;
    PORT
      LAYER met2 ;
        RECT 513.450 0.000 513.730 4.000 ;
    END
  END sstreams_i[370]
  PIN sstreams_i[371]
    DIRECTION INPUT ;
    USE SIGNAL ;
    ANTENNAGATEAREA 0.196500 ;
    PORT
      LAYER met2 ;
        RECT 515.750 0.000 516.030 4.000 ;
    END
  END sstreams_i[371]
  PIN sstreams_i[372]
    DIRECTION INPUT ;
    USE SIGNAL ;
    ANTENNAGATEAREA 0.196500 ;
    PORT
      LAYER met2 ;
        RECT 518.050 0.000 518.330 4.000 ;
    END
  END sstreams_i[372]
  PIN sstreams_i[373]
    DIRECTION INPUT ;
    USE SIGNAL ;
    ANTENNAGATEAREA 0.196500 ;
    PORT
      LAYER met2 ;
        RECT 520.350 0.000 520.630 4.000 ;
    END
  END sstreams_i[373]
  PIN sstreams_i[374]
    DIRECTION INPUT ;
    USE SIGNAL ;
    ANTENNAGATEAREA 0.196500 ;
    PORT
      LAYER met2 ;
        RECT 522.650 0.000 522.930 4.000 ;
    END
  END sstreams_i[374]
  PIN sstreams_i[375]
    DIRECTION INPUT ;
    USE SIGNAL ;
    ANTENNAGATEAREA 0.196500 ;
    PORT
      LAYER met2 ;
        RECT 524.950 0.000 525.230 4.000 ;
    END
  END sstreams_i[375]
  PIN sstreams_i[376]
    DIRECTION INPUT ;
    USE SIGNAL ;
    ANTENNAGATEAREA 0.196500 ;
    PORT
      LAYER met2 ;
        RECT 527.250 0.000 527.530 4.000 ;
    END
  END sstreams_i[376]
  PIN sstreams_i[377]
    DIRECTION INPUT ;
    USE SIGNAL ;
    ANTENNAGATEAREA 0.196500 ;
    PORT
      LAYER met2 ;
        RECT 529.550 0.000 529.830 4.000 ;
    END
  END sstreams_i[377]
  PIN sstreams_i[378]
    DIRECTION INPUT ;
    USE SIGNAL ;
    ANTENNAGATEAREA 0.196500 ;
    PORT
      LAYER met2 ;
        RECT 531.850 0.000 532.130 4.000 ;
    END
  END sstreams_i[378]
  PIN sstreams_i[379]
    DIRECTION INPUT ;
    USE SIGNAL ;
    ANTENNAGATEAREA 0.196500 ;
    PORT
      LAYER met2 ;
        RECT 534.150 0.000 534.430 4.000 ;
    END
  END sstreams_i[379]
  PIN sstreams_i[37]
    DIRECTION INPUT ;
    USE SIGNAL ;
    ANTENNAGATEAREA 0.196500 ;
    PORT
      LAYER met2 ;
        RECT 888.350 0.000 888.630 4.000 ;
    END
  END sstreams_i[37]
  PIN sstreams_i[380]
    DIRECTION INPUT ;
    USE SIGNAL ;
    ANTENNAGATEAREA 0.196500 ;
    PORT
      LAYER met2 ;
        RECT 536.450 0.000 536.730 4.000 ;
    END
  END sstreams_i[380]
  PIN sstreams_i[381]
    DIRECTION INPUT ;
    USE SIGNAL ;
    ANTENNAGATEAREA 0.196500 ;
    PORT
      LAYER met2 ;
        RECT 538.750 0.000 539.030 4.000 ;
    END
  END sstreams_i[381]
  PIN sstreams_i[382]
    DIRECTION INPUT ;
    USE SIGNAL ;
    ANTENNAGATEAREA 0.196500 ;
    PORT
      LAYER met2 ;
        RECT 541.050 0.000 541.330 4.000 ;
    END
  END sstreams_i[382]
  PIN sstreams_i[383]
    DIRECTION INPUT ;
    USE SIGNAL ;
    ANTENNAGATEAREA 0.196500 ;
    PORT
      LAYER met2 ;
        RECT 543.350 0.000 543.630 4.000 ;
    END
  END sstreams_i[383]
  PIN sstreams_i[384]
    DIRECTION INPUT ;
    USE SIGNAL ;
    ANTENNAGATEAREA 0.196500 ;
    PORT
      LAYER met2 ;
        RECT 545.650 0.000 545.930 4.000 ;
    END
  END sstreams_i[384]
  PIN sstreams_i[385]
    DIRECTION INPUT ;
    USE SIGNAL ;
    ANTENNAGATEAREA 0.196500 ;
    PORT
      LAYER met2 ;
        RECT 547.950 0.000 548.230 4.000 ;
    END
  END sstreams_i[385]
  PIN sstreams_i[386]
    DIRECTION INPUT ;
    USE SIGNAL ;
    ANTENNAGATEAREA 0.196500 ;
    PORT
      LAYER met2 ;
        RECT 550.250 0.000 550.530 4.000 ;
    END
  END sstreams_i[386]
  PIN sstreams_i[387]
    DIRECTION INPUT ;
    USE SIGNAL ;
    ANTENNAGATEAREA 0.196500 ;
    PORT
      LAYER met2 ;
        RECT 552.550 0.000 552.830 4.000 ;
    END
  END sstreams_i[387]
  PIN sstreams_i[388]
    DIRECTION INPUT ;
    USE SIGNAL ;
    ANTENNAGATEAREA 0.196500 ;
    PORT
      LAYER met2 ;
        RECT 554.850 0.000 555.130 4.000 ;
    END
  END sstreams_i[388]
  PIN sstreams_i[389]
    DIRECTION INPUT ;
    USE SIGNAL ;
    ANTENNAGATEAREA 0.196500 ;
    PORT
      LAYER met2 ;
        RECT 557.150 0.000 557.430 4.000 ;
    END
  END sstreams_i[389]
  PIN sstreams_i[38]
    DIRECTION INPUT ;
    USE SIGNAL ;
    ANTENNAGATEAREA 0.196500 ;
    PORT
      LAYER met2 ;
        RECT 890.650 0.000 890.930 4.000 ;
    END
  END sstreams_i[38]
  PIN sstreams_i[390]
    DIRECTION INPUT ;
    USE SIGNAL ;
    ANTENNAGATEAREA 0.213000 ;
    PORT
      LAYER met2 ;
        RECT 559.450 0.000 559.730 4.000 ;
    END
  END sstreams_i[390]
  PIN sstreams_i[391]
    DIRECTION INPUT ;
    USE SIGNAL ;
    ANTENNAGATEAREA 0.196500 ;
    PORT
      LAYER met2 ;
        RECT 561.750 0.000 562.030 4.000 ;
    END
  END sstreams_i[391]
  PIN sstreams_i[39]
    DIRECTION INPUT ;
    USE SIGNAL ;
    ANTENNAGATEAREA 0.196500 ;
    PORT
      LAYER met2 ;
        RECT 892.950 0.000 893.230 4.000 ;
    END
  END sstreams_i[39]
  PIN sstreams_i[3]
    DIRECTION INPUT ;
    USE SIGNAL ;
    ANTENNAGATEAREA 0.196500 ;
    PORT
      LAYER met2 ;
        RECT 810.150 0.000 810.430 4.000 ;
    END
  END sstreams_i[3]
  PIN sstreams_i[40]
    DIRECTION INPUT ;
    USE SIGNAL ;
    ANTENNAGATEAREA 0.196500 ;
    PORT
      LAYER met2 ;
        RECT 895.250 0.000 895.530 4.000 ;
    END
  END sstreams_i[40]
  PIN sstreams_i[41]
    DIRECTION INPUT ;
    USE SIGNAL ;
    ANTENNAGATEAREA 0.196500 ;
    PORT
      LAYER met2 ;
        RECT 897.550 0.000 897.830 4.000 ;
    END
  END sstreams_i[41]
  PIN sstreams_i[42]
    DIRECTION INPUT ;
    USE SIGNAL ;
    ANTENNAGATEAREA 0.196500 ;
    PORT
      LAYER met2 ;
        RECT 899.850 0.000 900.130 4.000 ;
    END
  END sstreams_i[42]
  PIN sstreams_i[43]
    DIRECTION INPUT ;
    USE SIGNAL ;
    ANTENNAGATEAREA 0.196500 ;
    PORT
      LAYER met2 ;
        RECT 902.150 0.000 902.430 4.000 ;
    END
  END sstreams_i[43]
  PIN sstreams_i[44]
    DIRECTION INPUT ;
    USE SIGNAL ;
    ANTENNAGATEAREA 0.196500 ;
    PORT
      LAYER met2 ;
        RECT 904.450 0.000 904.730 4.000 ;
    END
  END sstreams_i[44]
  PIN sstreams_i[45]
    DIRECTION INPUT ;
    USE SIGNAL ;
    ANTENNAGATEAREA 0.196500 ;
    PORT
      LAYER met2 ;
        RECT 906.750 0.000 907.030 4.000 ;
    END
  END sstreams_i[45]
  PIN sstreams_i[46]
    DIRECTION INPUT ;
    USE SIGNAL ;
    ANTENNAGATEAREA 0.196500 ;
    PORT
      LAYER met2 ;
        RECT 909.050 0.000 909.330 4.000 ;
    END
  END sstreams_i[46]
  PIN sstreams_i[47]
    DIRECTION INPUT ;
    USE SIGNAL ;
    ANTENNAGATEAREA 0.196500 ;
    PORT
      LAYER met2 ;
        RECT 911.350 0.000 911.630 4.000 ;
    END
  END sstreams_i[47]
  PIN sstreams_i[48]
    DIRECTION INPUT ;
    USE SIGNAL ;
    ANTENNAGATEAREA 0.196500 ;
    PORT
      LAYER met2 ;
        RECT 913.650 0.000 913.930 4.000 ;
    END
  END sstreams_i[48]
  PIN sstreams_i[49]
    DIRECTION INPUT ;
    USE SIGNAL ;
    ANTENNAGATEAREA 0.196500 ;
    PORT
      LAYER met2 ;
        RECT 915.950 0.000 916.230 4.000 ;
    END
  END sstreams_i[49]
  PIN sstreams_i[4]
    DIRECTION INPUT ;
    USE SIGNAL ;
    ANTENNAGATEAREA 0.196500 ;
    PORT
      LAYER met2 ;
        RECT 812.450 0.000 812.730 4.000 ;
    END
  END sstreams_i[4]
  PIN sstreams_i[50]
    DIRECTION INPUT ;
    USE SIGNAL ;
    ANTENNAGATEAREA 0.196500 ;
    PORT
      LAYER met2 ;
        RECT 918.250 0.000 918.530 4.000 ;
    END
  END sstreams_i[50]
  PIN sstreams_i[51]
    DIRECTION INPUT ;
    USE SIGNAL ;
    ANTENNAGATEAREA 0.196500 ;
    PORT
      LAYER met2 ;
        RECT 920.550 0.000 920.830 4.000 ;
    END
  END sstreams_i[51]
  PIN sstreams_i[52]
    DIRECTION INPUT ;
    USE SIGNAL ;
    ANTENNAGATEAREA 0.196500 ;
    PORT
      LAYER met2 ;
        RECT 922.850 0.000 923.130 4.000 ;
    END
  END sstreams_i[52]
  PIN sstreams_i[53]
    DIRECTION INPUT ;
    USE SIGNAL ;
    ANTENNAGATEAREA 0.196500 ;
    PORT
      LAYER met2 ;
        RECT 925.150 0.000 925.430 4.000 ;
    END
  END sstreams_i[53]
  PIN sstreams_i[54]
    DIRECTION INPUT ;
    USE SIGNAL ;
    ANTENNAGATEAREA 0.196500 ;
    PORT
      LAYER met2 ;
        RECT 927.450 0.000 927.730 4.000 ;
    END
  END sstreams_i[54]
  PIN sstreams_i[55]
    DIRECTION INPUT ;
    USE SIGNAL ;
    ANTENNAGATEAREA 0.196500 ;
    PORT
      LAYER met2 ;
        RECT 929.750 0.000 930.030 4.000 ;
    END
  END sstreams_i[55]
  PIN sstreams_i[56]
    DIRECTION INPUT ;
    USE SIGNAL ;
    ANTENNAGATEAREA 0.196500 ;
    PORT
      LAYER met2 ;
        RECT 932.050 0.000 932.330 4.000 ;
    END
  END sstreams_i[56]
  PIN sstreams_i[57]
    DIRECTION INPUT ;
    USE SIGNAL ;
    ANTENNAGATEAREA 0.196500 ;
    PORT
      LAYER met2 ;
        RECT 934.350 0.000 934.630 4.000 ;
    END
  END sstreams_i[57]
  PIN sstreams_i[58]
    DIRECTION INPUT ;
    USE SIGNAL ;
    ANTENNAGATEAREA 0.196500 ;
    PORT
      LAYER met2 ;
        RECT 936.650 0.000 936.930 4.000 ;
    END
  END sstreams_i[58]
  PIN sstreams_i[59]
    DIRECTION INPUT ;
    USE SIGNAL ;
    ANTENNAGATEAREA 0.196500 ;
    PORT
      LAYER met2 ;
        RECT 938.950 0.000 939.230 4.000 ;
    END
  END sstreams_i[59]
  PIN sstreams_i[5]
    DIRECTION INPUT ;
    USE SIGNAL ;
    ANTENNAGATEAREA 0.196500 ;
    PORT
      LAYER met2 ;
        RECT 814.750 0.000 815.030 4.000 ;
    END
  END sstreams_i[5]
  PIN sstreams_i[60]
    DIRECTION INPUT ;
    USE SIGNAL ;
    ANTENNAGATEAREA 0.196500 ;
    PORT
      LAYER met2 ;
        RECT 941.250 0.000 941.530 4.000 ;
    END
  END sstreams_i[60]
  PIN sstreams_i[61]
    DIRECTION INPUT ;
    USE SIGNAL ;
    ANTENNAGATEAREA 0.196500 ;
    PORT
      LAYER met2 ;
        RECT 943.550 0.000 943.830 4.000 ;
    END
  END sstreams_i[61]
  PIN sstreams_i[62]
    DIRECTION INPUT ;
    USE SIGNAL ;
    ANTENNAGATEAREA 0.196500 ;
    PORT
      LAYER met2 ;
        RECT 945.850 0.000 946.130 4.000 ;
    END
  END sstreams_i[62]
  PIN sstreams_i[63]
    DIRECTION INPUT ;
    USE SIGNAL ;
    ANTENNAGATEAREA 0.196500 ;
    PORT
      LAYER met2 ;
        RECT 948.150 0.000 948.430 4.000 ;
    END
  END sstreams_i[63]
  PIN sstreams_i[64]
    DIRECTION INPUT ;
    USE SIGNAL ;
    ANTENNAGATEAREA 0.196500 ;
    PORT
      LAYER met2 ;
        RECT 950.450 0.000 950.730 4.000 ;
    END
  END sstreams_i[64]
  PIN sstreams_i[65]
    DIRECTION INPUT ;
    USE SIGNAL ;
    ANTENNAGATEAREA 0.196500 ;
    PORT
      LAYER met2 ;
        RECT 952.750 0.000 953.030 4.000 ;
    END
  END sstreams_i[65]
  PIN sstreams_i[66]
    DIRECTION INPUT ;
    USE SIGNAL ;
    ANTENNAGATEAREA 0.196500 ;
    PORT
      LAYER met2 ;
        RECT 955.050 0.000 955.330 4.000 ;
    END
  END sstreams_i[66]
  PIN sstreams_i[67]
    DIRECTION INPUT ;
    USE SIGNAL ;
    ANTENNAGATEAREA 0.196500 ;
    PORT
      LAYER met2 ;
        RECT 957.350 0.000 957.630 4.000 ;
    END
  END sstreams_i[67]
  PIN sstreams_i[68]
    DIRECTION INPUT ;
    USE SIGNAL ;
    ANTENNAGATEAREA 0.196500 ;
    PORT
      LAYER met2 ;
        RECT 959.650 0.000 959.930 4.000 ;
    END
  END sstreams_i[68]
  PIN sstreams_i[69]
    DIRECTION INPUT ;
    USE SIGNAL ;
    ANTENNAGATEAREA 0.196500 ;
    PORT
      LAYER met2 ;
        RECT 961.950 0.000 962.230 4.000 ;
    END
  END sstreams_i[69]
  PIN sstreams_i[6]
    DIRECTION INPUT ;
    USE SIGNAL ;
    ANTENNAGATEAREA 0.196500 ;
    PORT
      LAYER met2 ;
        RECT 817.050 0.000 817.330 4.000 ;
    END
  END sstreams_i[6]
  PIN sstreams_i[70]
    DIRECTION INPUT ;
    USE SIGNAL ;
    ANTENNAGATEAREA 0.247500 ;
    PORT
      LAYER met2 ;
        RECT 964.250 0.000 964.530 4.000 ;
    END
  END sstreams_i[70]
  PIN sstreams_i[71]
    DIRECTION INPUT ;
    USE SIGNAL ;
    ANTENNAGATEAREA 0.247500 ;
    PORT
      LAYER met2 ;
        RECT 966.550 0.000 966.830 4.000 ;
    END
  END sstreams_i[71]
  PIN sstreams_i[72]
    DIRECTION INPUT ;
    USE SIGNAL ;
    ANTENNAGATEAREA 0.247500 ;
    PORT
      LAYER met2 ;
        RECT 968.850 0.000 969.130 4.000 ;
    END
  END sstreams_i[72]
  PIN sstreams_i[73]
    DIRECTION INPUT ;
    USE SIGNAL ;
    ANTENNAGATEAREA 0.247500 ;
    PORT
      LAYER met2 ;
        RECT 971.150 0.000 971.430 4.000 ;
    END
  END sstreams_i[73]
  PIN sstreams_i[74]
    DIRECTION INPUT ;
    USE SIGNAL ;
    ANTENNAGATEAREA 0.213000 ;
    PORT
      LAYER met2 ;
        RECT 973.450 0.000 973.730 4.000 ;
    END
  END sstreams_i[74]
  PIN sstreams_i[75]
    DIRECTION INPUT ;
    USE SIGNAL ;
    ANTENNAGATEAREA 0.247500 ;
    PORT
      LAYER met2 ;
        RECT 975.750 0.000 976.030 4.000 ;
    END
  END sstreams_i[75]
  PIN sstreams_i[76]
    DIRECTION INPUT ;
    USE SIGNAL ;
    ANTENNAGATEAREA 0.247500 ;
    PORT
      LAYER met2 ;
        RECT 978.050 0.000 978.330 4.000 ;
    END
  END sstreams_i[76]
  PIN sstreams_i[77]
    DIRECTION INPUT ;
    USE SIGNAL ;
    ANTENNAGATEAREA 0.247500 ;
    PORT
      LAYER met2 ;
        RECT 980.350 0.000 980.630 4.000 ;
    END
  END sstreams_i[77]
  PIN sstreams_i[78]
    DIRECTION INPUT ;
    USE SIGNAL ;
    ANTENNAGATEAREA 0.213000 ;
    PORT
      LAYER met2 ;
        RECT 982.650 0.000 982.930 4.000 ;
    END
  END sstreams_i[78]
  PIN sstreams_i[79]
    DIRECTION INPUT ;
    USE SIGNAL ;
    ANTENNAGATEAREA 0.213000 ;
    PORT
      LAYER met2 ;
        RECT 984.950 0.000 985.230 4.000 ;
    END
  END sstreams_i[79]
  PIN sstreams_i[7]
    DIRECTION INPUT ;
    USE SIGNAL ;
    ANTENNAGATEAREA 0.196500 ;
    PORT
      LAYER met2 ;
        RECT 819.350 0.000 819.630 4.000 ;
    END
  END sstreams_i[7]
  PIN sstreams_i[80]
    DIRECTION INPUT ;
    USE SIGNAL ;
    ANTENNAGATEAREA 0.213000 ;
    PORT
      LAYER met2 ;
        RECT 987.250 0.000 987.530 4.000 ;
    END
  END sstreams_i[80]
  PIN sstreams_i[81]
    DIRECTION INPUT ;
    USE SIGNAL ;
    ANTENNAGATEAREA 0.196500 ;
    PORT
      LAYER met2 ;
        RECT 989.550 0.000 989.830 4.000 ;
    END
  END sstreams_i[81]
  PIN sstreams_i[82]
    DIRECTION INPUT ;
    USE SIGNAL ;
    ANTENNAGATEAREA 0.159000 ;
    PORT
      LAYER met2 ;
        RECT 991.850 0.000 992.130 4.000 ;
    END
  END sstreams_i[82]
  PIN sstreams_i[83]
    DIRECTION INPUT ;
    USE SIGNAL ;
    ANTENNAGATEAREA 0.159000 ;
    PORT
      LAYER met2 ;
        RECT 994.150 0.000 994.430 4.000 ;
    END
  END sstreams_i[83]
  PIN sstreams_i[84]
    DIRECTION INPUT ;
    USE SIGNAL ;
    ANTENNAGATEAREA 0.247500 ;
    PORT
      LAYER met2 ;
        RECT 996.450 0.000 996.730 4.000 ;
    END
  END sstreams_i[84]
  PIN sstreams_i[85]
    DIRECTION INPUT ;
    USE SIGNAL ;
    ANTENNAGATEAREA 0.213000 ;
    PORT
      LAYER met2 ;
        RECT 998.750 0.000 999.030 4.000 ;
    END
  END sstreams_i[85]
  PIN sstreams_i[86]
    DIRECTION INPUT ;
    USE SIGNAL ;
    ANTENNAGATEAREA 0.213000 ;
    PORT
      LAYER met2 ;
        RECT 1001.050 0.000 1001.330 4.000 ;
    END
  END sstreams_i[86]
  PIN sstreams_i[87]
    DIRECTION INPUT ;
    USE SIGNAL ;
    ANTENNAGATEAREA 0.213000 ;
    PORT
      LAYER met2 ;
        RECT 1003.350 0.000 1003.630 4.000 ;
    END
  END sstreams_i[87]
  PIN sstreams_i[88]
    DIRECTION INPUT ;
    USE SIGNAL ;
    ANTENNAGATEAREA 0.247500 ;
    PORT
      LAYER met2 ;
        RECT 1005.650 0.000 1005.930 4.000 ;
    END
  END sstreams_i[88]
  PIN sstreams_i[89]
    DIRECTION INPUT ;
    USE SIGNAL ;
    ANTENNAGATEAREA 0.213000 ;
    PORT
      LAYER met2 ;
        RECT 1007.950 0.000 1008.230 4.000 ;
    END
  END sstreams_i[89]
  PIN sstreams_i[8]
    DIRECTION INPUT ;
    USE SIGNAL ;
    ANTENNAGATEAREA 0.196500 ;
    PORT
      LAYER met2 ;
        RECT 821.650 0.000 821.930 4.000 ;
    END
  END sstreams_i[8]
  PIN sstreams_i[90]
    DIRECTION INPUT ;
    USE SIGNAL ;
    ANTENNAGATEAREA 0.213000 ;
    PORT
      LAYER met2 ;
        RECT 1010.250 0.000 1010.530 4.000 ;
    END
  END sstreams_i[90]
  PIN sstreams_i[91]
    DIRECTION INPUT ;
    USE SIGNAL ;
    ANTENNAGATEAREA 0.213000 ;
    PORT
      LAYER met2 ;
        RECT 1012.550 0.000 1012.830 4.000 ;
    END
  END sstreams_i[91]
  PIN sstreams_i[92]
    DIRECTION INPUT ;
    USE SIGNAL ;
    ANTENNAGATEAREA 0.213000 ;
    PORT
      LAYER met2 ;
        RECT 1014.850 0.000 1015.130 4.000 ;
    END
  END sstreams_i[92]
  PIN sstreams_i[93]
    DIRECTION INPUT ;
    USE SIGNAL ;
    ANTENNAGATEAREA 0.159000 ;
    PORT
      LAYER met2 ;
        RECT 1017.150 0.000 1017.430 4.000 ;
    END
  END sstreams_i[93]
  PIN sstreams_i[94]
    DIRECTION INPUT ;
    USE SIGNAL ;
    ANTENNAGATEAREA 0.213000 ;
    PORT
      LAYER met2 ;
        RECT 1019.450 0.000 1019.730 4.000 ;
    END
  END sstreams_i[94]
  PIN sstreams_i[95]
    DIRECTION INPUT ;
    USE SIGNAL ;
    ANTENNAGATEAREA 0.213000 ;
    PORT
      LAYER met2 ;
        RECT 1021.750 0.000 1022.030 4.000 ;
    END
  END sstreams_i[95]
  PIN sstreams_i[96]
    DIRECTION INPUT ;
    USE SIGNAL ;
    ANTENNAGATEAREA 0.495000 ;
    PORT
      LAYER met2 ;
        RECT 1024.050 0.000 1024.330 4.000 ;
    END
  END sstreams_i[96]
  PIN sstreams_i[97]
    DIRECTION INPUT ;
    USE SIGNAL ;
    ANTENNAGATEAREA 0.213000 ;
    PORT
      LAYER met2 ;
        RECT 1026.350 0.000 1026.630 4.000 ;
    END
  END sstreams_i[97]
  PIN sstreams_i[98]
    DIRECTION INPUT ;
    USE SIGNAL ;
    ANTENNAGATEAREA 0.426000 ;
    PORT
      LAYER met2 ;
        RECT 1028.650 0.000 1028.930 4.000 ;
    END
  END sstreams_i[98]
  PIN sstreams_i[99]
    DIRECTION INPUT ;
    USE SIGNAL ;
    ANTENNAGATEAREA 0.426000 ;
    PORT
      LAYER met2 ;
        RECT 1030.950 0.000 1031.230 4.000 ;
    END
  END sstreams_i[99]
  PIN sstreams_i[9]
    DIRECTION INPUT ;
    USE SIGNAL ;
    ANTENNAGATEAREA 0.196500 ;
    PORT
      LAYER met2 ;
        RECT 823.950 0.000 824.230 4.000 ;
    END
  END sstreams_i[9]
  PIN sstreams_o[0]
    DIRECTION OUTPUT TRISTATE ;
    USE SIGNAL ;
    ANTENNADIFFAREA 0.795200 ;
    PORT
      LAYER met2 ;
        RECT 1254.050 0.000 1254.330 4.000 ;
    END
  END sstreams_o[0]
  PIN sstreams_o[1]
    DIRECTION OUTPUT TRISTATE ;
    USE SIGNAL ;
    ANTENNADIFFAREA 0.795200 ;
    PORT
      LAYER met2 ;
        RECT 1256.350 0.000 1256.630 4.000 ;
    END
  END sstreams_o[1]
  PIN sstreams_o[2]
    DIRECTION OUTPUT TRISTATE ;
    USE SIGNAL ;
    ANTENNADIFFAREA 0.795200 ;
    PORT
      LAYER met2 ;
        RECT 564.050 0.000 564.330 4.000 ;
    END
  END sstreams_o[2]
  PIN sstreams_o[3]
    DIRECTION OUTPUT TRISTATE ;
    USE SIGNAL ;
    ANTENNADIFFAREA 0.795200 ;
    PORT
      LAYER met2 ;
        RECT 566.350 0.000 566.630 4.000 ;
    END
  END sstreams_o[3]
  PIN vccd1
    DIRECTION INOUT ;
    USE POWER ;
    PORT
      LAYER met4 ;
        RECT -2.080 3.280 -0.480 494.480 ;
    END
    PORT
      LAYER met5 ;
        RECT -2.080 3.280 1601.960 4.880 ;
    END
    PORT
      LAYER met5 ;
        RECT -2.080 492.880 1601.960 494.480 ;
    END
    PORT
      LAYER met4 ;
        RECT 1600.360 3.280 1601.960 494.480 ;
    END
    PORT
      LAYER met4 ;
        RECT 21.040 -0.020 22.640 497.780 ;
    END
    PORT
      LAYER met4 ;
        RECT 174.640 -0.020 176.240 497.780 ;
    END
    PORT
      LAYER met4 ;
        RECT 328.240 -0.020 329.840 497.780 ;
    END
    PORT
      LAYER met4 ;
        RECT 481.840 -0.020 483.440 497.780 ;
    END
    PORT
      LAYER met4 ;
        RECT 635.440 -0.020 637.040 497.780 ;
    END
    PORT
      LAYER met4 ;
        RECT 789.040 -0.020 790.640 497.780 ;
    END
    PORT
      LAYER met4 ;
        RECT 942.640 -0.020 944.240 497.780 ;
    END
    PORT
      LAYER met4 ;
        RECT 1096.240 -0.020 1097.840 497.780 ;
    END
    PORT
      LAYER met4 ;
        RECT 1249.840 -0.020 1251.440 497.780 ;
    END
    PORT
      LAYER met4 ;
        RECT 1403.440 -0.020 1405.040 497.780 ;
    END
    PORT
      LAYER met4 ;
        RECT 1557.040 -0.020 1558.640 497.780 ;
    END
    PORT
      LAYER met5 ;
        RECT -5.380 26.730 1605.260 28.330 ;
    END
    PORT
      LAYER met5 ;
        RECT -5.380 179.910 1605.260 181.510 ;
    END
    PORT
      LAYER met5 ;
        RECT -5.380 333.090 1605.260 334.690 ;
    END
  END vccd1
  PIN vssd1
    DIRECTION INOUT ;
    USE GROUND ;
    PORT
      LAYER met4 ;
        RECT -5.380 -0.020 -3.780 497.780 ;
    END
    PORT
      LAYER met5 ;
        RECT -5.380 -0.020 1605.260 1.580 ;
    END
    PORT
      LAYER met5 ;
        RECT -5.380 496.180 1605.260 497.780 ;
    END
    PORT
      LAYER met4 ;
        RECT 1603.660 -0.020 1605.260 497.780 ;
    END
    PORT
      LAYER met4 ;
        RECT 24.340 -0.020 25.940 497.780 ;
    END
    PORT
      LAYER met4 ;
        RECT 177.940 -0.020 179.540 497.780 ;
    END
    PORT
      LAYER met4 ;
        RECT 331.540 -0.020 333.140 497.780 ;
    END
    PORT
      LAYER met4 ;
        RECT 485.140 -0.020 486.740 497.780 ;
    END
    PORT
      LAYER met4 ;
        RECT 638.740 -0.020 640.340 497.780 ;
    END
    PORT
      LAYER met4 ;
        RECT 792.340 -0.020 793.940 497.780 ;
    END
    PORT
      LAYER met4 ;
        RECT 945.940 -0.020 947.540 497.780 ;
    END
    PORT
      LAYER met4 ;
        RECT 1099.540 -0.020 1101.140 497.780 ;
    END
    PORT
      LAYER met4 ;
        RECT 1253.140 -0.020 1254.740 497.780 ;
    END
    PORT
      LAYER met4 ;
        RECT 1406.740 -0.020 1408.340 497.780 ;
    END
    PORT
      LAYER met4 ;
        RECT 1560.340 -0.020 1561.940 497.780 ;
    END
    PORT
      LAYER met5 ;
        RECT -5.380 30.030 1605.260 31.630 ;
    END
    PORT
      LAYER met5 ;
        RECT -5.380 183.210 1605.260 184.810 ;
    END
    PORT
      LAYER met5 ;
        RECT -5.380 336.390 1605.260 337.990 ;
    END
  END vssd1
  OBS
      LAYER li1 ;
        RECT 5.520 10.795 1594.360 486.965 ;
      LAYER met1 ;
        RECT 5.520 0.040 1594.360 487.120 ;
      LAYER met2 ;
        RECT 7.920 4.280 1591.960 487.065 ;
        RECT 7.920 0.010 108.370 4.280 ;
        RECT 109.210 0.010 110.670 4.280 ;
        RECT 111.510 0.010 112.970 4.280 ;
        RECT 113.810 0.010 115.270 4.280 ;
        RECT 116.110 0.010 117.570 4.280 ;
        RECT 118.410 0.010 119.870 4.280 ;
        RECT 120.710 0.010 122.170 4.280 ;
        RECT 123.010 0.010 124.470 4.280 ;
        RECT 125.310 0.010 126.770 4.280 ;
        RECT 127.610 0.010 129.070 4.280 ;
        RECT 129.910 0.010 131.370 4.280 ;
        RECT 132.210 0.010 133.670 4.280 ;
        RECT 134.510 0.010 135.970 4.280 ;
        RECT 136.810 0.010 138.270 4.280 ;
        RECT 139.110 0.010 140.570 4.280 ;
        RECT 141.410 0.010 142.870 4.280 ;
        RECT 143.710 0.010 145.170 4.280 ;
        RECT 146.010 0.010 147.470 4.280 ;
        RECT 148.310 0.010 149.770 4.280 ;
        RECT 150.610 0.010 152.070 4.280 ;
        RECT 152.910 0.010 154.370 4.280 ;
        RECT 155.210 0.010 156.670 4.280 ;
        RECT 157.510 0.010 158.970 4.280 ;
        RECT 159.810 0.010 161.270 4.280 ;
        RECT 162.110 0.010 163.570 4.280 ;
        RECT 164.410 0.010 165.870 4.280 ;
        RECT 166.710 0.010 168.170 4.280 ;
        RECT 169.010 0.010 170.470 4.280 ;
        RECT 171.310 0.010 172.770 4.280 ;
        RECT 173.610 0.010 175.070 4.280 ;
        RECT 175.910 0.010 177.370 4.280 ;
        RECT 178.210 0.010 179.670 4.280 ;
        RECT 180.510 0.010 181.970 4.280 ;
        RECT 182.810 0.010 184.270 4.280 ;
        RECT 185.110 0.010 186.570 4.280 ;
        RECT 187.410 0.010 188.870 4.280 ;
        RECT 189.710 0.010 191.170 4.280 ;
        RECT 192.010 0.010 193.470 4.280 ;
        RECT 194.310 0.010 195.770 4.280 ;
        RECT 196.610 0.010 198.070 4.280 ;
        RECT 198.910 0.010 200.370 4.280 ;
        RECT 201.210 0.010 202.670 4.280 ;
        RECT 203.510 0.010 204.970 4.280 ;
        RECT 205.810 0.010 207.270 4.280 ;
        RECT 208.110 0.010 209.570 4.280 ;
        RECT 210.410 0.010 211.870 4.280 ;
        RECT 212.710 0.010 214.170 4.280 ;
        RECT 215.010 0.010 216.470 4.280 ;
        RECT 217.310 0.010 218.770 4.280 ;
        RECT 219.610 0.010 221.070 4.280 ;
        RECT 221.910 0.010 223.370 4.280 ;
        RECT 224.210 0.010 225.670 4.280 ;
        RECT 226.510 0.010 227.970 4.280 ;
        RECT 228.810 0.010 230.270 4.280 ;
        RECT 231.110 0.010 232.570 4.280 ;
        RECT 233.410 0.010 234.870 4.280 ;
        RECT 235.710 0.010 237.170 4.280 ;
        RECT 238.010 0.010 239.470 4.280 ;
        RECT 240.310 0.010 241.770 4.280 ;
        RECT 242.610 0.010 244.070 4.280 ;
        RECT 244.910 0.010 246.370 4.280 ;
        RECT 247.210 0.010 248.670 4.280 ;
        RECT 249.510 0.010 250.970 4.280 ;
        RECT 251.810 0.010 253.270 4.280 ;
        RECT 254.110 0.010 255.570 4.280 ;
        RECT 256.410 0.010 257.870 4.280 ;
        RECT 258.710 0.010 260.170 4.280 ;
        RECT 261.010 0.010 262.470 4.280 ;
        RECT 263.310 0.010 264.770 4.280 ;
        RECT 265.610 0.010 267.070 4.280 ;
        RECT 267.910 0.010 269.370 4.280 ;
        RECT 270.210 0.010 271.670 4.280 ;
        RECT 272.510 0.010 273.970 4.280 ;
        RECT 274.810 0.010 276.270 4.280 ;
        RECT 277.110 0.010 278.570 4.280 ;
        RECT 279.410 0.010 280.870 4.280 ;
        RECT 281.710 0.010 283.170 4.280 ;
        RECT 284.010 0.010 285.470 4.280 ;
        RECT 286.310 0.010 287.770 4.280 ;
        RECT 288.610 0.010 290.070 4.280 ;
        RECT 290.910 0.010 292.370 4.280 ;
        RECT 293.210 0.010 294.670 4.280 ;
        RECT 295.510 0.010 296.970 4.280 ;
        RECT 297.810 0.010 299.270 4.280 ;
        RECT 300.110 0.010 301.570 4.280 ;
        RECT 302.410 0.010 303.870 4.280 ;
        RECT 304.710 0.010 306.170 4.280 ;
        RECT 307.010 0.010 308.470 4.280 ;
        RECT 309.310 0.010 310.770 4.280 ;
        RECT 311.610 0.010 313.070 4.280 ;
        RECT 313.910 0.010 315.370 4.280 ;
        RECT 316.210 0.010 317.670 4.280 ;
        RECT 318.510 0.010 319.970 4.280 ;
        RECT 320.810 0.010 322.270 4.280 ;
        RECT 323.110 0.010 324.570 4.280 ;
        RECT 325.410 0.010 326.870 4.280 ;
        RECT 327.710 0.010 329.170 4.280 ;
        RECT 330.010 0.010 331.470 4.280 ;
        RECT 332.310 0.010 333.770 4.280 ;
        RECT 334.610 0.010 336.070 4.280 ;
        RECT 336.910 0.010 338.370 4.280 ;
        RECT 339.210 0.010 340.670 4.280 ;
        RECT 341.510 0.010 342.970 4.280 ;
        RECT 343.810 0.010 345.270 4.280 ;
        RECT 346.110 0.010 347.570 4.280 ;
        RECT 348.410 0.010 349.870 4.280 ;
        RECT 350.710 0.010 352.170 4.280 ;
        RECT 353.010 0.010 354.470 4.280 ;
        RECT 355.310 0.010 356.770 4.280 ;
        RECT 357.610 0.010 359.070 4.280 ;
        RECT 359.910 0.010 361.370 4.280 ;
        RECT 362.210 0.010 363.670 4.280 ;
        RECT 364.510 0.010 365.970 4.280 ;
        RECT 366.810 0.010 368.270 4.280 ;
        RECT 369.110 0.010 370.570 4.280 ;
        RECT 371.410 0.010 372.870 4.280 ;
        RECT 373.710 0.010 375.170 4.280 ;
        RECT 376.010 0.010 377.470 4.280 ;
        RECT 378.310 0.010 379.770 4.280 ;
        RECT 380.610 0.010 382.070 4.280 ;
        RECT 382.910 0.010 384.370 4.280 ;
        RECT 385.210 0.010 386.670 4.280 ;
        RECT 387.510 0.010 388.970 4.280 ;
        RECT 389.810 0.010 391.270 4.280 ;
        RECT 392.110 0.010 393.570 4.280 ;
        RECT 394.410 0.010 395.870 4.280 ;
        RECT 396.710 0.010 398.170 4.280 ;
        RECT 399.010 0.010 400.470 4.280 ;
        RECT 401.310 0.010 402.770 4.280 ;
        RECT 403.610 0.010 405.070 4.280 ;
        RECT 405.910 0.010 407.370 4.280 ;
        RECT 408.210 0.010 409.670 4.280 ;
        RECT 410.510 0.010 411.970 4.280 ;
        RECT 412.810 0.010 414.270 4.280 ;
        RECT 415.110 0.010 416.570 4.280 ;
        RECT 417.410 0.010 418.870 4.280 ;
        RECT 419.710 0.010 421.170 4.280 ;
        RECT 422.010 0.010 423.470 4.280 ;
        RECT 424.310 0.010 425.770 4.280 ;
        RECT 426.610 0.010 428.070 4.280 ;
        RECT 428.910 0.010 430.370 4.280 ;
        RECT 431.210 0.010 432.670 4.280 ;
        RECT 433.510 0.010 434.970 4.280 ;
        RECT 435.810 0.010 437.270 4.280 ;
        RECT 438.110 0.010 439.570 4.280 ;
        RECT 440.410 0.010 441.870 4.280 ;
        RECT 442.710 0.010 444.170 4.280 ;
        RECT 445.010 0.010 446.470 4.280 ;
        RECT 447.310 0.010 448.770 4.280 ;
        RECT 449.610 0.010 451.070 4.280 ;
        RECT 451.910 0.010 453.370 4.280 ;
        RECT 454.210 0.010 455.670 4.280 ;
        RECT 456.510 0.010 457.970 4.280 ;
        RECT 458.810 0.010 460.270 4.280 ;
        RECT 461.110 0.010 462.570 4.280 ;
        RECT 463.410 0.010 464.870 4.280 ;
        RECT 465.710 0.010 467.170 4.280 ;
        RECT 468.010 0.010 469.470 4.280 ;
        RECT 470.310 0.010 471.770 4.280 ;
        RECT 472.610 0.010 474.070 4.280 ;
        RECT 474.910 0.010 476.370 4.280 ;
        RECT 477.210 0.010 478.670 4.280 ;
        RECT 479.510 0.010 480.970 4.280 ;
        RECT 481.810 0.010 483.270 4.280 ;
        RECT 484.110 0.010 485.570 4.280 ;
        RECT 486.410 0.010 487.870 4.280 ;
        RECT 488.710 0.010 490.170 4.280 ;
        RECT 491.010 0.010 492.470 4.280 ;
        RECT 493.310 0.010 494.770 4.280 ;
        RECT 495.610 0.010 497.070 4.280 ;
        RECT 497.910 0.010 499.370 4.280 ;
        RECT 500.210 0.010 501.670 4.280 ;
        RECT 502.510 0.010 503.970 4.280 ;
        RECT 504.810 0.010 506.270 4.280 ;
        RECT 507.110 0.010 508.570 4.280 ;
        RECT 509.410 0.010 510.870 4.280 ;
        RECT 511.710 0.010 513.170 4.280 ;
        RECT 514.010 0.010 515.470 4.280 ;
        RECT 516.310 0.010 517.770 4.280 ;
        RECT 518.610 0.010 520.070 4.280 ;
        RECT 520.910 0.010 522.370 4.280 ;
        RECT 523.210 0.010 524.670 4.280 ;
        RECT 525.510 0.010 526.970 4.280 ;
        RECT 527.810 0.010 529.270 4.280 ;
        RECT 530.110 0.010 531.570 4.280 ;
        RECT 532.410 0.010 533.870 4.280 ;
        RECT 534.710 0.010 536.170 4.280 ;
        RECT 537.010 0.010 538.470 4.280 ;
        RECT 539.310 0.010 540.770 4.280 ;
        RECT 541.610 0.010 543.070 4.280 ;
        RECT 543.910 0.010 545.370 4.280 ;
        RECT 546.210 0.010 547.670 4.280 ;
        RECT 548.510 0.010 549.970 4.280 ;
        RECT 550.810 0.010 552.270 4.280 ;
        RECT 553.110 0.010 554.570 4.280 ;
        RECT 555.410 0.010 556.870 4.280 ;
        RECT 557.710 0.010 559.170 4.280 ;
        RECT 560.010 0.010 561.470 4.280 ;
        RECT 562.310 0.010 563.770 4.280 ;
        RECT 564.610 0.010 566.070 4.280 ;
        RECT 566.910 0.010 568.370 4.280 ;
        RECT 569.210 0.010 570.670 4.280 ;
        RECT 571.510 0.010 572.970 4.280 ;
        RECT 573.810 0.010 575.270 4.280 ;
        RECT 576.110 0.010 577.570 4.280 ;
        RECT 578.410 0.010 579.870 4.280 ;
        RECT 580.710 0.010 582.170 4.280 ;
        RECT 583.010 0.010 584.470 4.280 ;
        RECT 585.310 0.010 586.770 4.280 ;
        RECT 587.610 0.010 589.070 4.280 ;
        RECT 589.910 0.010 591.370 4.280 ;
        RECT 592.210 0.010 593.670 4.280 ;
        RECT 594.510 0.010 595.970 4.280 ;
        RECT 596.810 0.010 598.270 4.280 ;
        RECT 599.110 0.010 600.570 4.280 ;
        RECT 601.410 0.010 602.870 4.280 ;
        RECT 603.710 0.010 605.170 4.280 ;
        RECT 606.010 0.010 607.470 4.280 ;
        RECT 608.310 0.010 609.770 4.280 ;
        RECT 610.610 0.010 612.070 4.280 ;
        RECT 612.910 0.010 614.370 4.280 ;
        RECT 615.210 0.010 616.670 4.280 ;
        RECT 617.510 0.010 618.970 4.280 ;
        RECT 619.810 0.010 621.270 4.280 ;
        RECT 622.110 0.010 623.570 4.280 ;
        RECT 624.410 0.010 625.870 4.280 ;
        RECT 626.710 0.010 628.170 4.280 ;
        RECT 629.010 0.010 630.470 4.280 ;
        RECT 631.310 0.010 632.770 4.280 ;
        RECT 633.610 0.010 635.070 4.280 ;
        RECT 635.910 0.010 637.370 4.280 ;
        RECT 638.210 0.010 639.670 4.280 ;
        RECT 640.510 0.010 641.970 4.280 ;
        RECT 642.810 0.010 644.270 4.280 ;
        RECT 645.110 0.010 646.570 4.280 ;
        RECT 647.410 0.010 648.870 4.280 ;
        RECT 649.710 0.010 651.170 4.280 ;
        RECT 652.010 0.010 653.470 4.280 ;
        RECT 654.310 0.010 655.770 4.280 ;
        RECT 656.610 0.010 658.070 4.280 ;
        RECT 658.910 0.010 660.370 4.280 ;
        RECT 661.210 0.010 662.670 4.280 ;
        RECT 663.510 0.010 664.970 4.280 ;
        RECT 665.810 0.010 667.270 4.280 ;
        RECT 668.110 0.010 669.570 4.280 ;
        RECT 670.410 0.010 671.870 4.280 ;
        RECT 672.710 0.010 674.170 4.280 ;
        RECT 675.010 0.010 676.470 4.280 ;
        RECT 677.310 0.010 678.770 4.280 ;
        RECT 679.610 0.010 681.070 4.280 ;
        RECT 681.910 0.010 683.370 4.280 ;
        RECT 684.210 0.010 685.670 4.280 ;
        RECT 686.510 0.010 687.970 4.280 ;
        RECT 688.810 0.010 690.270 4.280 ;
        RECT 691.110 0.010 692.570 4.280 ;
        RECT 693.410 0.010 694.870 4.280 ;
        RECT 695.710 0.010 697.170 4.280 ;
        RECT 698.010 0.010 699.470 4.280 ;
        RECT 700.310 0.010 701.770 4.280 ;
        RECT 702.610 0.010 704.070 4.280 ;
        RECT 704.910 0.010 706.370 4.280 ;
        RECT 707.210 0.010 708.670 4.280 ;
        RECT 709.510 0.010 710.970 4.280 ;
        RECT 711.810 0.010 713.270 4.280 ;
        RECT 714.110 0.010 715.570 4.280 ;
        RECT 716.410 0.010 717.870 4.280 ;
        RECT 718.710 0.010 720.170 4.280 ;
        RECT 721.010 0.010 722.470 4.280 ;
        RECT 723.310 0.010 724.770 4.280 ;
        RECT 725.610 0.010 727.070 4.280 ;
        RECT 727.910 0.010 729.370 4.280 ;
        RECT 730.210 0.010 731.670 4.280 ;
        RECT 732.510 0.010 733.970 4.280 ;
        RECT 734.810 0.010 736.270 4.280 ;
        RECT 737.110 0.010 738.570 4.280 ;
        RECT 739.410 0.010 740.870 4.280 ;
        RECT 741.710 0.010 743.170 4.280 ;
        RECT 744.010 0.010 745.470 4.280 ;
        RECT 746.310 0.010 747.770 4.280 ;
        RECT 748.610 0.010 750.070 4.280 ;
        RECT 750.910 0.010 752.370 4.280 ;
        RECT 753.210 0.010 754.670 4.280 ;
        RECT 755.510 0.010 756.970 4.280 ;
        RECT 757.810 0.010 759.270 4.280 ;
        RECT 760.110 0.010 761.570 4.280 ;
        RECT 762.410 0.010 763.870 4.280 ;
        RECT 764.710 0.010 766.170 4.280 ;
        RECT 767.010 0.010 768.470 4.280 ;
        RECT 769.310 0.010 770.770 4.280 ;
        RECT 771.610 0.010 773.070 4.280 ;
        RECT 773.910 0.010 775.370 4.280 ;
        RECT 776.210 0.010 777.670 4.280 ;
        RECT 778.510 0.010 779.970 4.280 ;
        RECT 780.810 0.010 782.270 4.280 ;
        RECT 783.110 0.010 784.570 4.280 ;
        RECT 785.410 0.010 786.870 4.280 ;
        RECT 787.710 0.010 789.170 4.280 ;
        RECT 790.010 0.010 791.470 4.280 ;
        RECT 792.310 0.010 793.770 4.280 ;
        RECT 794.610 0.010 796.070 4.280 ;
        RECT 796.910 0.010 798.370 4.280 ;
        RECT 799.210 0.010 800.670 4.280 ;
        RECT 801.510 0.010 802.970 4.280 ;
        RECT 803.810 0.010 805.270 4.280 ;
        RECT 806.110 0.010 807.570 4.280 ;
        RECT 808.410 0.010 809.870 4.280 ;
        RECT 810.710 0.010 812.170 4.280 ;
        RECT 813.010 0.010 814.470 4.280 ;
        RECT 815.310 0.010 816.770 4.280 ;
        RECT 817.610 0.010 819.070 4.280 ;
        RECT 819.910 0.010 821.370 4.280 ;
        RECT 822.210 0.010 823.670 4.280 ;
        RECT 824.510 0.010 825.970 4.280 ;
        RECT 826.810 0.010 828.270 4.280 ;
        RECT 829.110 0.010 830.570 4.280 ;
        RECT 831.410 0.010 832.870 4.280 ;
        RECT 833.710 0.010 835.170 4.280 ;
        RECT 836.010 0.010 837.470 4.280 ;
        RECT 838.310 0.010 839.770 4.280 ;
        RECT 840.610 0.010 842.070 4.280 ;
        RECT 842.910 0.010 844.370 4.280 ;
        RECT 845.210 0.010 846.670 4.280 ;
        RECT 847.510 0.010 848.970 4.280 ;
        RECT 849.810 0.010 851.270 4.280 ;
        RECT 852.110 0.010 853.570 4.280 ;
        RECT 854.410 0.010 855.870 4.280 ;
        RECT 856.710 0.010 858.170 4.280 ;
        RECT 859.010 0.010 860.470 4.280 ;
        RECT 861.310 0.010 862.770 4.280 ;
        RECT 863.610 0.010 865.070 4.280 ;
        RECT 865.910 0.010 867.370 4.280 ;
        RECT 868.210 0.010 869.670 4.280 ;
        RECT 870.510 0.010 871.970 4.280 ;
        RECT 872.810 0.010 874.270 4.280 ;
        RECT 875.110 0.010 876.570 4.280 ;
        RECT 877.410 0.010 878.870 4.280 ;
        RECT 879.710 0.010 881.170 4.280 ;
        RECT 882.010 0.010 883.470 4.280 ;
        RECT 884.310 0.010 885.770 4.280 ;
        RECT 886.610 0.010 888.070 4.280 ;
        RECT 888.910 0.010 890.370 4.280 ;
        RECT 891.210 0.010 892.670 4.280 ;
        RECT 893.510 0.010 894.970 4.280 ;
        RECT 895.810 0.010 897.270 4.280 ;
        RECT 898.110 0.010 899.570 4.280 ;
        RECT 900.410 0.010 901.870 4.280 ;
        RECT 902.710 0.010 904.170 4.280 ;
        RECT 905.010 0.010 906.470 4.280 ;
        RECT 907.310 0.010 908.770 4.280 ;
        RECT 909.610 0.010 911.070 4.280 ;
        RECT 911.910 0.010 913.370 4.280 ;
        RECT 914.210 0.010 915.670 4.280 ;
        RECT 916.510 0.010 917.970 4.280 ;
        RECT 918.810 0.010 920.270 4.280 ;
        RECT 921.110 0.010 922.570 4.280 ;
        RECT 923.410 0.010 924.870 4.280 ;
        RECT 925.710 0.010 927.170 4.280 ;
        RECT 928.010 0.010 929.470 4.280 ;
        RECT 930.310 0.010 931.770 4.280 ;
        RECT 932.610 0.010 934.070 4.280 ;
        RECT 934.910 0.010 936.370 4.280 ;
        RECT 937.210 0.010 938.670 4.280 ;
        RECT 939.510 0.010 940.970 4.280 ;
        RECT 941.810 0.010 943.270 4.280 ;
        RECT 944.110 0.010 945.570 4.280 ;
        RECT 946.410 0.010 947.870 4.280 ;
        RECT 948.710 0.010 950.170 4.280 ;
        RECT 951.010 0.010 952.470 4.280 ;
        RECT 953.310 0.010 954.770 4.280 ;
        RECT 955.610 0.010 957.070 4.280 ;
        RECT 957.910 0.010 959.370 4.280 ;
        RECT 960.210 0.010 961.670 4.280 ;
        RECT 962.510 0.010 963.970 4.280 ;
        RECT 964.810 0.010 966.270 4.280 ;
        RECT 967.110 0.010 968.570 4.280 ;
        RECT 969.410 0.010 970.870 4.280 ;
        RECT 971.710 0.010 973.170 4.280 ;
        RECT 974.010 0.010 975.470 4.280 ;
        RECT 976.310 0.010 977.770 4.280 ;
        RECT 978.610 0.010 980.070 4.280 ;
        RECT 980.910 0.010 982.370 4.280 ;
        RECT 983.210 0.010 984.670 4.280 ;
        RECT 985.510 0.010 986.970 4.280 ;
        RECT 987.810 0.010 989.270 4.280 ;
        RECT 990.110 0.010 991.570 4.280 ;
        RECT 992.410 0.010 993.870 4.280 ;
        RECT 994.710 0.010 996.170 4.280 ;
        RECT 997.010 0.010 998.470 4.280 ;
        RECT 999.310 0.010 1000.770 4.280 ;
        RECT 1001.610 0.010 1003.070 4.280 ;
        RECT 1003.910 0.010 1005.370 4.280 ;
        RECT 1006.210 0.010 1007.670 4.280 ;
        RECT 1008.510 0.010 1009.970 4.280 ;
        RECT 1010.810 0.010 1012.270 4.280 ;
        RECT 1013.110 0.010 1014.570 4.280 ;
        RECT 1015.410 0.010 1016.870 4.280 ;
        RECT 1017.710 0.010 1019.170 4.280 ;
        RECT 1020.010 0.010 1021.470 4.280 ;
        RECT 1022.310 0.010 1023.770 4.280 ;
        RECT 1024.610 0.010 1026.070 4.280 ;
        RECT 1026.910 0.010 1028.370 4.280 ;
        RECT 1029.210 0.010 1030.670 4.280 ;
        RECT 1031.510 0.010 1032.970 4.280 ;
        RECT 1033.810 0.010 1035.270 4.280 ;
        RECT 1036.110 0.010 1037.570 4.280 ;
        RECT 1038.410 0.010 1039.870 4.280 ;
        RECT 1040.710 0.010 1042.170 4.280 ;
        RECT 1043.010 0.010 1044.470 4.280 ;
        RECT 1045.310 0.010 1046.770 4.280 ;
        RECT 1047.610 0.010 1049.070 4.280 ;
        RECT 1049.910 0.010 1051.370 4.280 ;
        RECT 1052.210 0.010 1053.670 4.280 ;
        RECT 1054.510 0.010 1055.970 4.280 ;
        RECT 1056.810 0.010 1058.270 4.280 ;
        RECT 1059.110 0.010 1060.570 4.280 ;
        RECT 1061.410 0.010 1062.870 4.280 ;
        RECT 1063.710 0.010 1065.170 4.280 ;
        RECT 1066.010 0.010 1067.470 4.280 ;
        RECT 1068.310 0.010 1069.770 4.280 ;
        RECT 1070.610 0.010 1072.070 4.280 ;
        RECT 1072.910 0.010 1074.370 4.280 ;
        RECT 1075.210 0.010 1076.670 4.280 ;
        RECT 1077.510 0.010 1078.970 4.280 ;
        RECT 1079.810 0.010 1081.270 4.280 ;
        RECT 1082.110 0.010 1083.570 4.280 ;
        RECT 1084.410 0.010 1085.870 4.280 ;
        RECT 1086.710 0.010 1088.170 4.280 ;
        RECT 1089.010 0.010 1090.470 4.280 ;
        RECT 1091.310 0.010 1092.770 4.280 ;
        RECT 1093.610 0.010 1095.070 4.280 ;
        RECT 1095.910 0.010 1097.370 4.280 ;
        RECT 1098.210 0.010 1099.670 4.280 ;
        RECT 1100.510 0.010 1101.970 4.280 ;
        RECT 1102.810 0.010 1104.270 4.280 ;
        RECT 1105.110 0.010 1106.570 4.280 ;
        RECT 1107.410 0.010 1108.870 4.280 ;
        RECT 1109.710 0.010 1111.170 4.280 ;
        RECT 1112.010 0.010 1113.470 4.280 ;
        RECT 1114.310 0.010 1115.770 4.280 ;
        RECT 1116.610 0.010 1118.070 4.280 ;
        RECT 1118.910 0.010 1120.370 4.280 ;
        RECT 1121.210 0.010 1122.670 4.280 ;
        RECT 1123.510 0.010 1124.970 4.280 ;
        RECT 1125.810 0.010 1127.270 4.280 ;
        RECT 1128.110 0.010 1129.570 4.280 ;
        RECT 1130.410 0.010 1131.870 4.280 ;
        RECT 1132.710 0.010 1134.170 4.280 ;
        RECT 1135.010 0.010 1136.470 4.280 ;
        RECT 1137.310 0.010 1138.770 4.280 ;
        RECT 1139.610 0.010 1141.070 4.280 ;
        RECT 1141.910 0.010 1143.370 4.280 ;
        RECT 1144.210 0.010 1145.670 4.280 ;
        RECT 1146.510 0.010 1147.970 4.280 ;
        RECT 1148.810 0.010 1150.270 4.280 ;
        RECT 1151.110 0.010 1152.570 4.280 ;
        RECT 1153.410 0.010 1154.870 4.280 ;
        RECT 1155.710 0.010 1157.170 4.280 ;
        RECT 1158.010 0.010 1159.470 4.280 ;
        RECT 1160.310 0.010 1161.770 4.280 ;
        RECT 1162.610 0.010 1164.070 4.280 ;
        RECT 1164.910 0.010 1166.370 4.280 ;
        RECT 1167.210 0.010 1168.670 4.280 ;
        RECT 1169.510 0.010 1170.970 4.280 ;
        RECT 1171.810 0.010 1173.270 4.280 ;
        RECT 1174.110 0.010 1175.570 4.280 ;
        RECT 1176.410 0.010 1177.870 4.280 ;
        RECT 1178.710 0.010 1180.170 4.280 ;
        RECT 1181.010 0.010 1182.470 4.280 ;
        RECT 1183.310 0.010 1184.770 4.280 ;
        RECT 1185.610 0.010 1187.070 4.280 ;
        RECT 1187.910 0.010 1189.370 4.280 ;
        RECT 1190.210 0.010 1191.670 4.280 ;
        RECT 1192.510 0.010 1193.970 4.280 ;
        RECT 1194.810 0.010 1196.270 4.280 ;
        RECT 1197.110 0.010 1198.570 4.280 ;
        RECT 1199.410 0.010 1200.870 4.280 ;
        RECT 1201.710 0.010 1203.170 4.280 ;
        RECT 1204.010 0.010 1205.470 4.280 ;
        RECT 1206.310 0.010 1207.770 4.280 ;
        RECT 1208.610 0.010 1210.070 4.280 ;
        RECT 1210.910 0.010 1212.370 4.280 ;
        RECT 1213.210 0.010 1214.670 4.280 ;
        RECT 1215.510 0.010 1216.970 4.280 ;
        RECT 1217.810 0.010 1219.270 4.280 ;
        RECT 1220.110 0.010 1221.570 4.280 ;
        RECT 1222.410 0.010 1223.870 4.280 ;
        RECT 1224.710 0.010 1226.170 4.280 ;
        RECT 1227.010 0.010 1228.470 4.280 ;
        RECT 1229.310 0.010 1230.770 4.280 ;
        RECT 1231.610 0.010 1233.070 4.280 ;
        RECT 1233.910 0.010 1235.370 4.280 ;
        RECT 1236.210 0.010 1237.670 4.280 ;
        RECT 1238.510 0.010 1239.970 4.280 ;
        RECT 1240.810 0.010 1242.270 4.280 ;
        RECT 1243.110 0.010 1244.570 4.280 ;
        RECT 1245.410 0.010 1246.870 4.280 ;
        RECT 1247.710 0.010 1249.170 4.280 ;
        RECT 1250.010 0.010 1251.470 4.280 ;
        RECT 1252.310 0.010 1253.770 4.280 ;
        RECT 1254.610 0.010 1256.070 4.280 ;
        RECT 1256.910 0.010 1258.370 4.280 ;
        RECT 1259.210 0.010 1260.670 4.280 ;
        RECT 1261.510 0.010 1262.970 4.280 ;
        RECT 1263.810 0.010 1265.270 4.280 ;
        RECT 1266.110 0.010 1267.570 4.280 ;
        RECT 1268.410 0.010 1269.870 4.280 ;
        RECT 1270.710 0.010 1272.170 4.280 ;
        RECT 1273.010 0.010 1274.470 4.280 ;
        RECT 1275.310 0.010 1276.770 4.280 ;
        RECT 1277.610 0.010 1279.070 4.280 ;
        RECT 1279.910 0.010 1281.370 4.280 ;
        RECT 1282.210 0.010 1283.670 4.280 ;
        RECT 1284.510 0.010 1285.970 4.280 ;
        RECT 1286.810 0.010 1288.270 4.280 ;
        RECT 1289.110 0.010 1290.570 4.280 ;
        RECT 1291.410 0.010 1292.870 4.280 ;
        RECT 1293.710 0.010 1295.170 4.280 ;
        RECT 1296.010 0.010 1297.470 4.280 ;
        RECT 1298.310 0.010 1299.770 4.280 ;
        RECT 1300.610 0.010 1302.070 4.280 ;
        RECT 1302.910 0.010 1304.370 4.280 ;
        RECT 1305.210 0.010 1306.670 4.280 ;
        RECT 1307.510 0.010 1308.970 4.280 ;
        RECT 1309.810 0.010 1311.270 4.280 ;
        RECT 1312.110 0.010 1313.570 4.280 ;
        RECT 1314.410 0.010 1315.870 4.280 ;
        RECT 1316.710 0.010 1318.170 4.280 ;
        RECT 1319.010 0.010 1320.470 4.280 ;
        RECT 1321.310 0.010 1322.770 4.280 ;
        RECT 1323.610 0.010 1325.070 4.280 ;
        RECT 1325.910 0.010 1327.370 4.280 ;
        RECT 1328.210 0.010 1329.670 4.280 ;
        RECT 1330.510 0.010 1331.970 4.280 ;
        RECT 1332.810 0.010 1334.270 4.280 ;
        RECT 1335.110 0.010 1336.570 4.280 ;
        RECT 1337.410 0.010 1338.870 4.280 ;
        RECT 1339.710 0.010 1341.170 4.280 ;
        RECT 1342.010 0.010 1343.470 4.280 ;
        RECT 1344.310 0.010 1345.770 4.280 ;
        RECT 1346.610 0.010 1348.070 4.280 ;
        RECT 1348.910 0.010 1350.370 4.280 ;
        RECT 1351.210 0.010 1352.670 4.280 ;
        RECT 1353.510 0.010 1354.970 4.280 ;
        RECT 1355.810 0.010 1357.270 4.280 ;
        RECT 1358.110 0.010 1359.570 4.280 ;
        RECT 1360.410 0.010 1361.870 4.280 ;
        RECT 1362.710 0.010 1364.170 4.280 ;
        RECT 1365.010 0.010 1366.470 4.280 ;
        RECT 1367.310 0.010 1368.770 4.280 ;
        RECT 1369.610 0.010 1371.070 4.280 ;
        RECT 1371.910 0.010 1373.370 4.280 ;
        RECT 1374.210 0.010 1375.670 4.280 ;
        RECT 1376.510 0.010 1377.970 4.280 ;
        RECT 1378.810 0.010 1380.270 4.280 ;
        RECT 1381.110 0.010 1382.570 4.280 ;
        RECT 1383.410 0.010 1384.870 4.280 ;
        RECT 1385.710 0.010 1387.170 4.280 ;
        RECT 1388.010 0.010 1389.470 4.280 ;
        RECT 1390.310 0.010 1391.770 4.280 ;
        RECT 1392.610 0.010 1394.070 4.280 ;
        RECT 1394.910 0.010 1396.370 4.280 ;
        RECT 1397.210 0.010 1398.670 4.280 ;
        RECT 1399.510 0.010 1400.970 4.280 ;
        RECT 1401.810 0.010 1403.270 4.280 ;
        RECT 1404.110 0.010 1405.570 4.280 ;
        RECT 1406.410 0.010 1407.870 4.280 ;
        RECT 1408.710 0.010 1410.170 4.280 ;
        RECT 1411.010 0.010 1412.470 4.280 ;
        RECT 1413.310 0.010 1414.770 4.280 ;
        RECT 1415.610 0.010 1417.070 4.280 ;
        RECT 1417.910 0.010 1419.370 4.280 ;
        RECT 1420.210 0.010 1421.670 4.280 ;
        RECT 1422.510 0.010 1423.970 4.280 ;
        RECT 1424.810 0.010 1426.270 4.280 ;
        RECT 1427.110 0.010 1428.570 4.280 ;
        RECT 1429.410 0.010 1430.870 4.280 ;
        RECT 1431.710 0.010 1433.170 4.280 ;
        RECT 1434.010 0.010 1435.470 4.280 ;
        RECT 1436.310 0.010 1437.770 4.280 ;
        RECT 1438.610 0.010 1440.070 4.280 ;
        RECT 1440.910 0.010 1442.370 4.280 ;
        RECT 1443.210 0.010 1444.670 4.280 ;
        RECT 1445.510 0.010 1446.970 4.280 ;
        RECT 1447.810 0.010 1449.270 4.280 ;
        RECT 1450.110 0.010 1451.570 4.280 ;
        RECT 1452.410 0.010 1453.870 4.280 ;
        RECT 1454.710 0.010 1456.170 4.280 ;
        RECT 1457.010 0.010 1458.470 4.280 ;
        RECT 1459.310 0.010 1460.770 4.280 ;
        RECT 1461.610 0.010 1463.070 4.280 ;
        RECT 1463.910 0.010 1465.370 4.280 ;
        RECT 1466.210 0.010 1467.670 4.280 ;
        RECT 1468.510 0.010 1469.970 4.280 ;
        RECT 1470.810 0.010 1472.270 4.280 ;
        RECT 1473.110 0.010 1474.570 4.280 ;
        RECT 1475.410 0.010 1476.870 4.280 ;
        RECT 1477.710 0.010 1479.170 4.280 ;
        RECT 1480.010 0.010 1481.470 4.280 ;
        RECT 1482.310 0.010 1483.770 4.280 ;
        RECT 1484.610 0.010 1486.070 4.280 ;
        RECT 1486.910 0.010 1488.370 4.280 ;
        RECT 1489.210 0.010 1490.670 4.280 ;
        RECT 1491.510 0.010 1591.960 4.280 ;
      LAYER met3 ;
        RECT 21.050 0.175 1580.035 487.045 ;
      LAYER met4 ;
        RECT 262.495 2.215 327.840 465.625 ;
        RECT 330.240 2.215 331.140 465.625 ;
        RECT 333.540 2.215 481.440 465.625 ;
        RECT 483.840 2.215 484.740 465.625 ;
        RECT 487.140 2.215 635.040 465.625 ;
        RECT 637.440 2.215 638.340 465.625 ;
        RECT 640.740 2.215 788.640 465.625 ;
        RECT 791.040 2.215 791.940 465.625 ;
        RECT 794.340 2.215 942.240 465.625 ;
        RECT 944.640 2.215 945.540 465.625 ;
        RECT 947.940 2.215 1095.840 465.625 ;
        RECT 1098.240 2.215 1099.140 465.625 ;
        RECT 1101.540 2.215 1249.440 465.625 ;
        RECT 1251.840 2.215 1252.740 465.625 ;
        RECT 1255.140 2.215 1354.865 465.625 ;
  END
END shared_div_rasterizer_m
END LIBRARY

